VERSION 5.7 ;
  NOWIREEXTENSIONATPIN ON ;
  DIVIDERCHAR "/" ;
  BUSBITCHARS "[]" ;
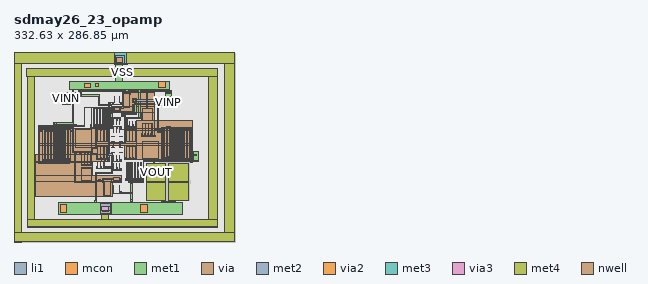
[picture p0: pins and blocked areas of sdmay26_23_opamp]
MACRO sdmay26_23_opamp
  CLASS BLOCK ;
  FOREIGN sdmay26_23_opamp ;
  ORIGIN -239.980 -7.060 ;
  SIZE 332.630 BY 286.850 ;
  PIN VINN
    ANTENNAGATEAREA 57.199997 ;
    PORT
      LAYER li1 ;
        RECT 468.290 235.120 477.470 235.240 ;
        RECT 313.390 213.970 324.780 232.110 ;
        RECT 468.120 231.680 477.470 235.120 ;
        RECT 468.290 227.210 477.470 231.680 ;
        RECT 386.770 166.690 388.770 166.860 ;
        RECT 389.060 166.690 391.060 166.860 ;
        RECT 386.770 158.990 388.770 159.160 ;
        RECT 389.060 158.990 391.060 159.160 ;
        RECT 399.120 150.270 401.120 150.440 ;
        RECT 401.410 150.270 403.410 150.440 ;
        RECT 399.120 142.570 401.120 142.740 ;
        RECT 401.410 142.570 403.410 142.740 ;
      LAYER mcon ;
        RECT 472.590 232.660 476.090 234.490 ;
        RECT 314.920 221.170 323.280 224.190 ;
        RECT 386.850 166.690 388.690 166.860 ;
        RECT 389.140 166.690 390.980 166.860 ;
        RECT 386.850 158.990 388.690 159.160 ;
        RECT 389.140 158.990 390.980 159.160 ;
        RECT 399.200 150.270 401.040 150.440 ;
        RECT 401.490 150.270 403.330 150.440 ;
        RECT 399.200 142.570 401.040 142.740 ;
        RECT 401.490 142.570 403.330 142.740 ;
      LAYER met1 ;
        RECT 468.290 235.120 477.470 235.240 ;
        RECT 313.260 214.170 324.650 232.310 ;
        RECT 336.240 229.550 342.060 233.160 ;
        RECT 468.120 231.680 477.470 235.120 ;
        RECT 367.100 229.550 369.750 229.670 ;
        RECT 335.990 226.930 369.750 229.550 ;
        RECT 468.290 227.210 477.470 231.680 ;
        RECT 336.240 226.680 342.060 226.930 ;
        RECT 367.100 214.120 369.750 226.930 ;
        RECT 366.830 212.790 387.880 214.120 ;
        RECT 366.830 212.610 387.910 212.790 ;
        RECT 367.100 212.560 369.750 212.610 ;
        RECT 387.070 202.290 387.910 212.610 ;
        RECT 387.040 201.620 387.910 202.290 ;
        RECT 387.040 201.300 387.870 201.620 ;
        RECT 385.220 195.590 388.570 201.300 ;
        RECT 385.220 184.180 386.030 195.590 ;
        RECT 385.170 184.120 386.030 184.180 ;
        RECT 385.170 179.770 385.980 184.120 ;
        RECT 382.850 178.880 385.990 179.770 ;
        RECT 382.890 157.330 383.970 178.880 ;
        RECT 386.790 166.660 388.750 166.890 ;
        RECT 389.080 166.660 391.040 166.890 ;
        RECT 386.790 159.150 388.750 159.190 ;
        RECT 389.080 159.150 391.040 159.190 ;
        RECT 386.790 158.960 391.040 159.150 ;
        RECT 382.900 156.790 383.970 157.330 ;
        RECT 387.480 158.860 388.810 158.960 ;
        RECT 387.480 156.940 387.880 158.860 ;
        RECT 387.470 156.790 387.880 156.940 ;
        RECT 399.450 156.790 400.660 157.410 ;
        RECT 382.900 156.780 388.780 156.790 ;
        RECT 397.140 156.780 400.660 156.790 ;
        RECT 382.900 156.770 400.660 156.780 ;
        RECT 382.900 156.350 400.670 156.770 ;
        RECT 382.900 156.340 397.730 156.350 ;
        RECT 382.900 156.330 388.780 156.340 ;
        RECT 399.450 156.330 400.670 156.350 ;
        RECT 382.900 156.320 384.820 156.330 ;
        RECT 399.540 153.430 400.750 154.610 ;
        RECT 399.770 153.390 400.380 153.430 ;
        RECT 399.780 152.270 400.380 153.390 ;
        RECT 399.770 151.500 400.380 152.270 ;
        RECT 399.770 150.470 400.370 151.500 ;
        RECT 399.140 150.460 401.100 150.470 ;
        RECT 401.430 150.460 403.390 150.470 ;
        RECT 399.140 150.250 403.390 150.460 ;
        RECT 399.140 150.240 401.100 150.250 ;
        RECT 401.430 150.240 403.390 150.250 ;
        RECT 399.140 142.540 401.100 142.770 ;
        RECT 401.430 142.540 403.390 142.770 ;
      LAYER via ;
        RECT 319.470 227.050 322.580 230.610 ;
        RECT 338.210 228.680 340.550 231.880 ;
        RECT 468.810 232.370 470.810 234.670 ;
        RECT 399.790 156.520 400.420 157.090 ;
        RECT 399.800 153.760 400.430 154.330 ;
      LAYER met2 ;
        RECT 337.620 233.800 471.730 235.290 ;
        RECT 337.680 233.160 340.990 233.800 ;
        RECT 317.820 232.020 324.530 232.060 ;
        RECT 336.240 232.020 342.060 233.160 ;
        RECT 317.820 228.720 342.060 232.020 ;
        RECT 468.120 231.680 471.730 233.800 ;
        RECT 317.820 225.600 324.530 228.720 ;
        RECT 336.240 226.680 342.060 228.720 ;
        RECT 399.450 155.940 400.660 157.410 ;
        RECT 399.700 154.910 400.230 155.940 ;
        RECT 399.550 154.900 400.900 154.910 ;
        RECT 399.540 154.360 400.900 154.900 ;
        RECT 399.540 153.430 400.860 154.360 ;
        RECT 399.550 153.400 400.860 153.430 ;
    END
  END VINN
  PIN VINP
    ANTENNAGATEAREA 57.199997 ;
    PORT
      LAYER li1 ;
        RECT 467.950 211.780 477.760 224.690 ;
        RECT 399.090 166.680 401.090 166.850 ;
        RECT 401.380 166.680 403.380 166.850 ;
        RECT 399.090 158.980 401.090 159.150 ;
        RECT 401.380 158.980 403.380 159.150 ;
        RECT 386.720 150.230 388.720 150.400 ;
        RECT 389.010 150.230 391.010 150.400 ;
        RECT 386.720 142.530 388.720 142.700 ;
        RECT 389.010 142.530 391.010 142.700 ;
      LAYER mcon ;
        RECT 468.710 220.920 476.500 223.600 ;
        RECT 399.170 166.680 401.010 166.850 ;
        RECT 401.460 166.680 403.300 166.850 ;
        RECT 399.170 158.980 401.010 159.150 ;
        RECT 401.460 158.980 403.300 159.150 ;
        RECT 386.800 150.230 388.640 150.400 ;
        RECT 389.090 150.230 390.930 150.400 ;
        RECT 386.800 142.530 388.640 142.700 ;
        RECT 389.090 142.530 390.930 142.700 ;
      LAYER met1 ;
        RECT 418.610 217.550 425.230 223.250 ;
        RECT 467.950 217.980 477.760 224.690 ;
        RECT 421.850 201.360 424.480 217.550 ;
        RECT 463.100 212.870 477.760 217.980 ;
        RECT 467.950 211.780 477.760 212.870 ;
        RECT 406.840 201.030 424.480 201.360 ;
        RECT 402.760 199.330 424.480 201.030 ;
        RECT 402.760 199.030 423.590 199.330 ;
        RECT 402.760 197.940 408.040 199.030 ;
        RECT 402.760 196.040 408.070 197.940 ;
        RECT 399.110 166.650 401.070 166.880 ;
        RECT 401.400 166.650 403.360 166.880 ;
        RECT 399.110 159.010 403.360 159.180 ;
        RECT 399.110 158.950 401.070 159.010 ;
        RECT 401.400 158.950 403.360 159.010 ;
        RECT 402.140 157.000 402.470 158.950 ;
        RECT 406.970 157.030 408.070 196.040 ;
        RECT 406.970 157.000 408.100 157.030 ;
        RECT 402.140 156.230 408.100 157.000 ;
        RECT 389.590 155.730 390.500 155.740 ;
        RECT 402.140 155.730 402.540 156.230 ;
        RECT 389.580 155.210 402.540 155.730 ;
        RECT 389.580 155.200 391.060 155.210 ;
        RECT 389.580 155.160 390.490 155.200 ;
        RECT 389.590 153.040 390.490 155.160 ;
        RECT 389.590 152.420 390.500 153.040 ;
        RECT 389.600 150.600 390.480 152.420 ;
        RECT 388.590 150.430 390.480 150.600 ;
        RECT 386.740 150.230 390.990 150.430 ;
        RECT 386.740 150.200 388.700 150.230 ;
        RECT 389.030 150.200 390.990 150.230 ;
        RECT 386.740 142.500 388.700 142.730 ;
        RECT 389.030 142.500 390.990 142.730 ;
      LAYER via ;
        RECT 420.280 218.840 423.400 222.370 ;
        RECT 464.600 213.710 469.040 216.560 ;
      LAYER met2 ;
        RECT 418.610 221.570 425.230 223.250 ;
        RECT 418.610 221.470 455.680 221.570 ;
        RECT 460.020 221.470 462.590 221.520 ;
        RECT 418.610 219.580 462.590 221.470 ;
        RECT 418.610 219.560 455.680 219.580 ;
        RECT 418.610 217.550 425.230 219.560 ;
        RECT 460.020 216.140 462.590 219.580 ;
        RECT 463.100 216.140 470.220 217.980 ;
        RECT 460.020 214.130 470.220 216.140 ;
        RECT 460.020 214.040 462.590 214.130 ;
        RECT 463.100 212.870 470.220 214.130 ;
    END
  END VINP
  PIN VSS
    USE GROUND ;
    ANTENNADIFFAREA 475.595184 ;
    PORT
      LAYER li1 ;
        RECT 391.225 217.115 391.395 227.155 ;
        RECT 399.805 217.115 399.975 227.155 ;
        RECT 357.360 182.170 357.530 207.920 ;
        RECT 361.940 182.170 362.110 207.920 ;
        RECT 366.520 182.170 366.690 207.920 ;
        RECT 371.100 182.170 371.270 207.920 ;
        RECT 375.680 182.170 375.850 207.920 ;
        RECT 380.260 182.170 380.430 207.920 ;
        RECT 390.640 184.290 390.810 191.470 ;
        RECT 395.220 184.290 395.390 191.470 ;
        RECT 399.800 184.290 399.970 191.470 ;
        RECT 414.420 182.200 414.590 189.380 ;
        RECT 419.000 182.200 419.170 189.380 ;
        RECT 423.580 182.200 423.750 189.380 ;
        RECT 390.640 172.450 390.810 179.630 ;
        RECT 395.220 172.450 395.390 179.630 ;
        RECT 399.800 172.450 399.970 179.630 ;
        RECT 390.640 129.780 390.810 136.960 ;
        RECT 395.220 129.780 395.390 136.960 ;
        RECT 399.800 129.780 399.970 136.960 ;
        RECT 366.540 120.020 366.710 127.200 ;
        RECT 371.120 120.020 371.290 127.200 ;
        RECT 375.700 120.020 375.870 127.200 ;
        RECT 390.640 117.940 390.810 125.120 ;
        RECT 395.220 117.940 395.390 125.120 ;
        RECT 399.800 117.940 399.970 125.120 ;
        RECT 409.730 101.510 409.900 127.260 ;
        RECT 414.310 101.510 414.480 127.260 ;
        RECT 418.890 101.510 419.060 127.260 ;
        RECT 423.470 101.510 423.640 127.260 ;
        RECT 428.050 101.510 428.220 127.260 ;
        RECT 432.630 101.510 432.800 127.260 ;
        RECT 390.645 82.245 390.815 92.285 ;
        RECT 399.225 82.245 399.395 92.285 ;
        RECT 306.930 66.710 379.870 66.860 ;
        RECT 397.480 66.730 494.780 66.860 ;
        RECT 391.610 66.710 494.780 66.730 ;
        RECT 306.930 48.590 494.780 66.710 ;
        RECT 376.920 48.580 393.320 48.590 ;
      LAYER mcon ;
        RECT 391.225 217.195 391.395 227.075 ;
        RECT 399.805 217.195 399.975 227.075 ;
        RECT 357.360 182.250 357.530 207.840 ;
        RECT 361.940 182.250 362.110 207.840 ;
        RECT 366.520 182.250 366.690 207.840 ;
        RECT 371.100 182.250 371.270 207.840 ;
        RECT 375.680 182.250 375.850 207.840 ;
        RECT 380.260 182.250 380.430 207.840 ;
        RECT 390.640 184.370 390.810 191.390 ;
        RECT 395.220 184.370 395.390 191.390 ;
        RECT 399.800 184.370 399.970 191.390 ;
        RECT 414.420 182.280 414.590 189.300 ;
        RECT 419.000 182.280 419.170 189.300 ;
        RECT 423.580 182.280 423.750 189.300 ;
        RECT 390.640 172.530 390.810 179.550 ;
        RECT 395.220 172.530 395.390 179.550 ;
        RECT 399.800 172.530 399.970 179.550 ;
        RECT 390.640 129.860 390.810 136.880 ;
        RECT 395.220 129.860 395.390 136.880 ;
        RECT 399.800 129.860 399.970 136.880 ;
        RECT 366.540 120.100 366.710 127.120 ;
        RECT 371.120 120.100 371.290 127.120 ;
        RECT 375.700 120.100 375.870 127.120 ;
        RECT 390.640 118.020 390.810 125.040 ;
        RECT 395.220 118.020 395.390 125.040 ;
        RECT 399.800 118.020 399.970 125.040 ;
        RECT 409.730 101.590 409.900 127.180 ;
        RECT 414.310 101.590 414.480 127.180 ;
        RECT 418.890 101.590 419.060 127.180 ;
        RECT 423.470 101.590 423.640 127.180 ;
        RECT 428.050 101.590 428.220 127.180 ;
        RECT 432.630 101.590 432.800 127.180 ;
        RECT 390.645 82.325 390.815 92.205 ;
        RECT 399.225 82.325 399.395 92.205 ;
        RECT 309.490 51.230 319.680 63.190 ;
        RECT 430.830 51.190 441.020 63.150 ;
      LAYER met1 ;
        RECT 391.195 217.980 391.425 227.135 ;
        RECT 384.850 217.940 391.425 217.980 ;
        RECT 383.270 217.600 391.425 217.940 ;
        RECT 382.830 217.150 391.425 217.600 ;
        RECT 382.830 215.490 385.400 217.150 ;
        RECT 389.020 214.360 389.560 217.150 ;
        RECT 391.195 217.135 391.425 217.150 ;
        RECT 399.775 218.020 400.005 227.135 ;
        RECT 399.775 217.990 401.330 218.020 ;
        RECT 399.775 217.560 401.560 217.990 ;
        RECT 399.775 217.135 400.005 217.560 ;
        RECT 400.950 214.360 401.560 217.560 ;
        RECT 389.020 214.030 401.560 214.360 ;
        RECT 390.030 214.020 401.560 214.030 ;
        RECT 355.200 183.930 356.210 184.020 ;
        RECT 355.200 183.890 356.700 183.930 ;
        RECT 357.330 183.890 357.560 207.900 ;
        RECT 355.200 182.970 357.560 183.890 ;
        RECT 355.200 182.850 356.210 182.970 ;
        RECT 356.390 182.930 357.560 182.970 ;
        RECT 355.930 182.820 356.210 182.850 ;
        RECT 355.930 182.790 356.070 182.820 ;
        RECT 357.330 182.190 357.560 182.930 ;
        RECT 361.910 183.680 362.140 207.900 ;
        RECT 362.600 183.680 363.220 183.830 ;
        RECT 361.910 183.060 363.220 183.680 ;
        RECT 366.490 183.790 366.720 207.900 ;
        RECT 367.260 183.790 367.880 183.930 ;
        RECT 366.490 183.160 367.880 183.790 ;
        RECT 371.070 183.840 371.300 207.900 ;
        RECT 371.750 183.840 372.370 183.950 ;
        RECT 371.070 183.810 372.370 183.840 ;
        RECT 375.650 183.890 375.880 207.900 ;
        RECT 380.230 185.340 380.460 207.900 ;
        RECT 395.850 194.450 397.110 194.460 ;
        RECT 387.620 193.300 401.330 194.450 ;
        RECT 387.620 191.340 389.000 193.300 ;
        RECT 395.850 193.280 397.110 193.300 ;
        RECT 390.610 191.340 390.840 191.450 ;
        RECT 387.620 191.220 390.840 191.340 ;
        RECT 387.600 189.980 390.840 191.220 ;
        RECT 382.370 185.340 384.110 186.710 ;
        RECT 380.230 184.500 384.110 185.340 ;
        RECT 380.230 184.480 381.970 184.500 ;
        RECT 382.370 184.480 384.110 184.500 ;
        RECT 376.410 183.930 377.030 184.060 ;
        RECT 376.170 183.890 377.030 183.930 ;
        RECT 371.070 183.220 372.380 183.810 ;
        RECT 375.650 183.280 377.030 183.890 ;
        RECT 375.650 183.270 376.390 183.280 ;
        RECT 366.490 183.150 367.780 183.160 ;
        RECT 361.910 183.050 363.200 183.060 ;
        RECT 361.910 182.190 362.140 183.050 ;
        RECT 366.490 182.190 366.720 183.150 ;
        RECT 371.070 182.190 371.300 183.220 ;
        RECT 371.750 183.180 372.370 183.220 ;
        RECT 375.650 182.190 375.880 183.270 ;
        RECT 380.230 182.190 380.460 184.480 ;
        RECT 387.600 181.440 389.000 189.980 ;
        RECT 390.610 184.310 390.840 189.980 ;
        RECT 395.190 190.890 395.420 191.450 ;
        RECT 399.770 191.380 400.000 191.450 ;
        RECT 400.330 191.380 401.330 193.300 ;
        RECT 395.870 190.890 396.840 191.080 ;
        RECT 395.190 190.140 396.840 190.890 ;
        RECT 399.770 190.730 401.330 191.380 ;
        RECT 395.190 190.130 396.590 190.140 ;
        RECT 395.190 184.310 395.420 190.130 ;
        RECT 399.770 184.310 400.000 190.730 ;
        RECT 414.390 183.510 414.620 189.360 ;
        RECT 412.980 183.020 414.620 183.510 ;
        RECT 387.580 179.390 389.010 181.440 ;
        RECT 412.980 180.520 413.410 183.020 ;
        RECT 414.390 182.220 414.620 183.020 ;
        RECT 418.970 183.530 419.200 189.360 ;
        RECT 419.760 183.530 420.490 183.830 ;
        RECT 418.970 183.000 420.490 183.530 ;
        RECT 418.970 182.990 420.140 183.000 ;
        RECT 418.970 182.220 419.200 182.990 ;
        RECT 423.550 182.820 423.780 189.360 ;
        RECT 424.910 182.820 425.500 182.850 ;
        RECT 423.550 182.490 425.500 182.820 ;
        RECT 423.550 182.220 423.780 182.490 ;
        RECT 419.550 180.850 420.650 181.100 ;
        RECT 424.910 180.850 425.500 182.490 ;
        RECT 413.720 180.680 415.430 180.710 ;
        RECT 419.550 180.680 425.500 180.850 ;
        RECT 413.720 180.520 425.500 180.680 ;
        RECT 412.980 180.280 425.500 180.520 ;
        RECT 412.980 180.120 420.840 180.280 ;
        RECT 424.910 180.260 425.500 180.280 ;
        RECT 412.980 179.960 415.430 180.120 ;
        RECT 413.110 179.920 415.430 179.960 ;
        RECT 390.610 179.390 390.840 179.610 ;
        RECT 387.580 178.620 390.840 179.390 ;
        RECT 388.700 178.610 390.840 178.620 ;
        RECT 390.610 172.470 390.840 178.610 ;
        RECT 395.190 179.170 395.420 179.610 ;
        RECT 395.190 179.150 396.380 179.170 ;
        RECT 395.190 178.700 396.610 179.150 ;
        RECT 395.190 172.470 395.420 178.700 ;
        RECT 395.800 178.410 396.610 178.700 ;
        RECT 399.770 179.020 400.000 179.610 ;
        RECT 413.720 179.280 415.430 179.920 ;
        RECT 401.070 179.020 402.120 179.150 ;
        RECT 399.770 178.370 402.120 179.020 ;
        RECT 399.770 172.470 400.000 178.370 ;
        RECT 401.070 178.340 402.120 178.370 ;
        RECT 387.910 130.850 389.570 130.860 ;
        RECT 387.670 130.650 389.570 130.850 ;
        RECT 387.140 130.550 389.570 130.650 ;
        RECT 390.610 130.550 390.840 136.940 ;
        RECT 387.140 130.050 390.840 130.550 ;
        RECT 387.140 129.440 389.570 130.050 ;
        RECT 390.610 129.800 390.840 130.050 ;
        RECT 395.190 131.270 395.420 136.940 ;
        RECT 395.850 131.270 396.670 131.650 ;
        RECT 395.190 130.900 396.670 131.270 ;
        RECT 395.190 129.800 395.420 130.900 ;
        RECT 395.850 130.880 396.670 130.900 ;
        RECT 399.770 131.400 400.000 136.940 ;
        RECT 400.950 131.400 401.810 131.420 ;
        RECT 399.770 130.800 401.810 131.400 ;
        RECT 399.770 129.800 400.000 130.800 ;
        RECT 400.950 130.530 401.810 130.800 ;
        RECT 366.510 120.710 366.740 127.180 ;
        RECT 364.820 120.270 366.740 120.710 ;
        RECT 364.820 118.640 365.500 120.270 ;
        RECT 366.510 120.040 366.740 120.270 ;
        RECT 371.090 121.110 371.320 127.180 ;
        RECT 371.510 121.110 372.210 121.370 ;
        RECT 371.090 120.600 372.210 121.110 ;
        RECT 371.090 120.040 371.320 120.600 ;
        RECT 375.670 120.560 375.900 127.180 ;
        RECT 387.140 120.780 388.690 129.440 ;
        RECT 376.930 120.560 388.760 120.780 ;
        RECT 375.670 120.180 388.760 120.560 ;
        RECT 375.670 120.040 375.900 120.180 ;
        RECT 376.840 118.940 388.760 120.180 ;
        RECT 390.610 118.940 390.840 125.100 ;
        RECT 395.190 119.370 395.420 125.100 ;
        RECT 395.820 119.370 396.770 119.810 ;
        RECT 371.450 118.640 372.260 118.650 ;
        RECT 376.840 118.640 390.900 118.940 ;
        RECT 395.180 118.680 396.770 119.370 ;
        RECT 395.180 118.670 396.530 118.680 ;
        RECT 364.820 118.360 390.900 118.640 ;
        RECT 364.820 118.240 377.400 118.360 ;
        RECT 371.450 117.900 372.260 118.240 ;
        RECT 387.140 118.040 390.900 118.360 ;
        RECT 387.140 115.970 388.690 118.040 ;
        RECT 390.610 117.960 390.840 118.040 ;
        RECT 395.190 117.960 395.420 118.670 ;
        RECT 399.770 118.640 400.000 125.100 ;
        RECT 401.060 118.640 401.940 118.650 ;
        RECT 399.750 118.180 401.940 118.640 ;
        RECT 399.770 117.960 400.000 118.180 ;
        RECT 401.060 116.510 401.940 118.180 ;
        RECT 401.060 115.970 401.930 116.510 ;
        RECT 387.140 115.020 401.930 115.970 ;
        RECT 387.140 112.070 388.690 115.020 ;
        RECT 363.020 111.950 388.690 112.070 ;
        RECT 362.310 109.930 388.690 111.950 ;
        RECT 362.310 71.610 364.460 109.930 ;
        RECT 387.140 109.890 388.690 109.930 ;
        RECT 409.700 102.300 409.930 127.240 ;
        RECT 408.750 102.290 409.930 102.300 ;
        RECT 408.690 101.900 409.930 102.290 ;
        RECT 408.690 100.300 409.210 101.900 ;
        RECT 409.700 101.530 409.930 101.900 ;
        RECT 414.280 102.610 414.510 127.240 ;
        RECT 414.760 102.610 415.360 102.630 ;
        RECT 414.280 102.040 415.360 102.610 ;
        RECT 418.860 102.510 419.090 127.240 ;
        RECT 419.460 102.510 420.350 102.640 ;
        RECT 418.860 102.050 420.350 102.510 ;
        RECT 423.440 102.580 423.670 127.240 ;
        RECT 424.080 102.580 424.970 102.700 ;
        RECT 423.440 102.120 424.970 102.580 ;
        RECT 414.280 102.000 415.260 102.040 ;
        RECT 414.280 101.530 414.510 102.000 ;
        RECT 418.860 101.530 419.090 102.050 ;
        RECT 423.440 101.530 423.670 102.120 ;
        RECT 424.080 102.110 424.970 102.120 ;
        RECT 428.020 102.570 428.250 127.240 ;
        RECT 428.660 102.570 429.550 102.690 ;
        RECT 428.020 102.110 429.550 102.570 ;
        RECT 428.020 101.530 428.250 102.110 ;
        RECT 428.660 102.100 429.550 102.110 ;
        RECT 432.600 102.320 432.830 127.240 ;
        RECT 433.580 102.320 433.950 102.350 ;
        RECT 432.600 101.930 433.950 102.320 ;
        RECT 432.600 101.530 432.830 101.930 ;
        RECT 414.710 100.300 415.600 100.360 ;
        RECT 419.300 100.300 420.190 100.340 ;
        RECT 424.180 100.300 425.070 100.410 ;
        RECT 428.600 100.300 429.490 100.380 ;
        RECT 433.580 100.300 433.950 101.930 ;
        RECT 408.690 99.890 433.950 100.300 ;
        RECT 408.710 99.850 433.950 99.890 ;
        RECT 408.710 99.810 433.900 99.850 ;
        RECT 414.710 99.770 415.600 99.810 ;
        RECT 416.430 99.060 418.140 99.810 ;
        RECT 419.300 99.750 420.190 99.810 ;
        RECT 428.600 99.790 429.490 99.810 ;
        RECT 416.430 97.620 418.360 99.060 ;
        RECT 416.450 95.120 418.360 97.620 ;
        RECT 388.360 83.450 388.990 83.530 ;
        RECT 390.615 83.450 390.845 92.265 ;
        RECT 388.360 82.900 390.845 83.450 ;
        RECT 388.360 80.320 388.990 82.900 ;
        RECT 390.615 82.265 390.845 82.900 ;
        RECT 399.195 83.760 399.425 92.265 ;
        RECT 401.070 83.760 401.670 83.780 ;
        RECT 399.195 83.130 401.670 83.760 ;
        RECT 399.195 82.265 399.425 83.130 ;
        RECT 401.070 81.850 401.670 83.130 ;
        RECT 416.550 81.850 418.360 95.120 ;
        RECT 401.070 80.750 418.360 81.850 ;
        RECT 401.070 80.320 401.670 80.750 ;
        RECT 388.280 80.010 401.670 80.320 ;
        RECT 416.550 71.610 418.360 80.750 ;
        RECT 362.310 70.080 364.760 71.610 ;
        RECT 416.550 71.420 418.660 71.610 ;
        RECT 362.170 66.860 364.760 70.080 ;
        RECT 416.460 68.310 418.660 71.420 ;
        RECT 416.550 68.000 418.660 68.310 ;
        RECT 416.600 67.770 418.660 68.000 ;
        RECT 416.550 67.300 418.660 67.770 ;
        RECT 416.600 66.860 418.660 67.300 ;
        RECT 306.930 66.710 379.870 66.860 ;
        RECT 397.480 66.730 494.780 66.860 ;
        RECT 391.610 66.710 494.780 66.730 ;
        RECT 306.930 48.590 494.780 66.710 ;
        RECT 376.920 48.580 393.320 48.590 ;
      LAYER via ;
        RECT 383.480 216.040 385.040 217.090 ;
        RECT 355.340 183.080 355.890 183.810 ;
        RECT 362.730 183.160 362.990 183.580 ;
        RECT 367.390 183.310 367.650 183.730 ;
        RECT 396.200 193.420 396.840 194.030 ;
        RECT 382.700 184.730 383.640 186.000 ;
        RECT 371.850 183.370 372.110 183.790 ;
        RECT 376.540 183.380 376.800 183.800 ;
        RECT 396.090 190.370 396.560 190.840 ;
        RECT 387.870 180.250 388.680 181.080 ;
        RECT 419.910 183.160 420.410 183.620 ;
        RECT 414.050 179.670 414.990 180.420 ;
        RECT 419.930 180.350 420.430 180.810 ;
        RECT 395.970 178.580 396.450 179.060 ;
        RECT 401.310 178.530 401.960 178.890 ;
        RECT 388.290 129.790 389.230 130.450 ;
        RECT 396.020 131.010 396.610 131.430 ;
        RECT 401.100 130.690 401.670 131.190 ;
        RECT 371.660 120.760 371.990 121.190 ;
        RECT 396.060 118.920 396.470 119.480 ;
        RECT 371.620 118.040 372.050 118.410 ;
        RECT 395.990 115.190 396.810 115.640 ;
        RECT 414.880 102.160 415.220 102.530 ;
        RECT 419.780 102.170 420.110 102.440 ;
        RECT 424.310 102.310 424.640 102.580 ;
        RECT 428.890 102.250 429.220 102.520 ;
        RECT 414.970 99.960 415.300 100.230 ;
        RECT 419.640 99.900 419.970 100.170 ;
        RECT 424.510 99.940 424.840 100.210 ;
        RECT 428.870 99.940 429.200 100.210 ;
        RECT 372.390 53.710 382.510 62.560 ;
        RECT 372.990 53.640 382.160 53.710 ;
      LAYER met2 ;
        RECT 382.830 215.490 385.400 217.600 ;
        RECT 395.850 193.280 397.110 194.460 ;
        RECT 396.120 191.080 396.690 193.280 ;
        RECT 395.870 190.140 396.840 191.080 ;
        RECT 382.370 184.480 384.110 186.710 ;
        RECT 355.200 182.820 356.210 184.020 ;
        RECT 362.600 183.060 363.220 183.830 ;
        RECT 367.260 183.160 367.880 183.930 ;
        RECT 371.750 183.180 372.370 183.950 ;
        RECT 376.410 183.610 377.030 184.060 ;
        RECT 376.390 183.290 377.030 183.610 ;
        RECT 355.320 180.910 356.050 182.820 ;
        RECT 355.310 180.660 356.050 180.910 ;
        RECT 355.310 180.640 356.390 180.660 ;
        RECT 362.720 180.640 363.050 183.060 ;
        RECT 367.320 180.640 367.650 183.160 ;
        RECT 371.810 180.640 372.140 183.180 ;
        RECT 376.390 180.640 376.720 183.290 ;
        RECT 419.760 183.000 420.490 183.830 ;
        RECT 395.920 181.440 396.600 181.450 ;
        RECT 397.180 181.440 402.050 181.460 ;
        RECT 387.590 180.980 402.050 181.440 ;
        RECT 419.970 181.110 420.200 183.000 ;
        RECT 419.590 181.100 420.840 181.110 ;
        RECT 387.590 180.960 397.700 180.980 ;
        RECT 387.590 180.940 396.600 180.960 ;
        RECT 378.470 180.640 380.040 180.930 ;
        RECT 355.310 179.860 380.040 180.640 ;
        RECT 387.590 180.900 396.580 180.940 ;
        RECT 387.590 180.020 388.970 180.900 ;
        RECT 395.920 180.690 396.580 180.900 ;
        RECT 355.310 179.840 361.360 179.860 ;
        RECT 356.230 179.820 361.360 179.840 ;
        RECT 378.470 179.470 380.040 179.860 ;
        RECT 395.920 179.150 396.600 180.690 ;
        RECT 401.220 179.190 402.040 180.980 ;
        RECT 407.620 180.550 408.510 180.580 ;
        RECT 413.720 180.550 415.430 180.710 ;
        RECT 407.620 179.750 415.430 180.550 ;
        RECT 419.550 180.410 420.840 181.100 ;
        RECT 419.590 180.180 420.840 180.410 ;
        RECT 401.150 179.150 402.090 179.190 ;
        RECT 395.800 178.410 396.610 179.150 ;
        RECT 401.070 178.340 402.120 179.150 ;
        RECT 401.150 177.480 402.090 178.340 ;
        RECT 407.620 178.290 408.510 179.750 ;
        RECT 413.720 179.280 415.430 179.750 ;
        RECT 407.560 177.770 408.510 178.290 ;
        RECT 407.560 177.480 408.500 177.770 ;
        RECT 401.150 176.470 408.550 177.480 ;
        RECT 407.560 176.370 408.500 176.470 ;
        RECT 382.260 141.390 384.300 143.590 ;
        RECT 382.340 140.010 383.910 141.390 ;
        RECT 382.340 138.110 389.170 140.010 ;
        RECT 387.480 136.670 389.170 138.110 ;
        RECT 387.580 134.710 389.170 136.670 ;
        RECT 387.660 130.860 389.170 134.710 ;
        RECT 395.850 130.880 396.670 131.650 ;
        RECT 387.660 129.550 389.570 130.860 ;
        RECT 387.670 129.530 389.570 129.550 ;
        RECT 387.680 129.450 389.570 129.530 ;
        RECT 387.910 129.440 389.570 129.450 ;
        RECT 388.900 128.450 389.530 129.440 ;
        RECT 388.880 128.440 390.370 128.450 ;
        RECT 396.050 128.440 396.430 130.880 ;
        RECT 400.950 130.530 401.810 131.420 ;
        RECT 401.100 128.440 401.550 130.530 ;
        RECT 388.880 127.900 401.570 128.440 ;
        RECT 390.080 127.880 401.570 127.900 ;
        RECT 401.100 127.870 401.550 127.880 ;
        RECT 371.510 120.600 372.210 121.370 ;
        RECT 371.660 118.650 372.000 120.600 ;
        RECT 395.820 118.680 396.770 119.810 ;
        RECT 371.450 117.900 372.260 118.650 ;
        RECT 395.990 116.010 396.660 118.680 ;
        RECT 395.670 115.040 397.110 116.010 ;
        RECT 414.760 102.040 415.360 102.630 ;
        RECT 419.460 102.050 420.350 102.640 ;
        RECT 424.080 102.110 424.970 102.700 ;
        RECT 414.930 100.360 415.220 102.040 ;
        RECT 414.710 99.770 415.600 100.360 ;
        RECT 419.710 100.340 420.010 102.050 ;
        RECT 424.480 100.410 424.780 102.110 ;
        RECT 428.660 102.100 429.550 102.690 ;
        RECT 419.300 99.750 420.190 100.340 ;
        RECT 424.180 99.820 425.070 100.410 ;
        RECT 428.900 100.380 429.200 102.100 ;
        RECT 428.600 99.790 429.490 100.380 ;
        RECT 370.640 60.350 385.850 64.490 ;
        RECT 370.300 53.970 385.850 60.350 ;
        RECT 370.640 50.730 385.850 53.970 ;
      LAYER via2 ;
        RECT 383.480 216.040 385.040 217.090 ;
        RECT 382.700 184.730 383.640 186.000 ;
        RECT 378.820 179.820 379.590 180.580 ;
        RECT 387.870 180.250 388.680 181.080 ;
        RECT 382.710 141.820 383.820 142.950 ;
        RECT 372.390 53.710 382.510 62.560 ;
        RECT 372.990 53.640 382.160 53.710 ;
      LAYER met3 ;
        RECT 382.830 216.260 385.400 217.600 ;
        RECT 382.810 215.490 385.400 216.260 ;
        RECT 382.810 186.710 383.920 215.490 ;
        RECT 382.370 184.480 384.110 186.710 ;
        RECT 383.110 181.400 383.950 184.480 ;
        RECT 387.210 181.400 389.050 181.460 ;
        RECT 382.880 181.130 389.050 181.400 ;
        RECT 378.470 180.520 380.040 180.930 ;
        RECT 382.790 180.520 389.050 181.130 ;
        RECT 378.470 180.000 389.050 180.520 ;
        RECT 378.470 179.540 384.380 180.000 ;
        RECT 385.830 179.970 389.050 180.000 ;
        RECT 387.210 179.960 389.050 179.970 ;
        RECT 378.470 179.470 380.040 179.540 ;
        RECT 382.790 176.180 384.350 179.540 ;
        RECT 382.760 143.590 384.350 176.180 ;
        RECT 382.260 141.840 384.350 143.590 ;
        RECT 382.260 141.390 384.300 141.840 ;
        RECT 370.570 60.350 386.530 64.980 ;
        RECT 370.300 53.970 386.530 60.350 ;
        RECT 370.570 50.520 386.530 53.970 ;
        RECT 372.690 48.160 381.490 50.520 ;
      LAYER via3 ;
        RECT 372.390 53.710 382.510 62.560 ;
      LAYER met4 ;
        RECT 259.490 268.430 547.440 268.440 ;
        RECT 259.490 256.510 547.820 268.430 ;
        RECT 259.710 40.280 270.210 256.510 ;
        RECT 370.570 50.520 386.530 64.980 ;
        RECT 371.980 40.280 382.800 50.520 ;
        RECT 533.890 40.280 547.820 256.510 ;
        RECT 259.710 30.760 547.820 40.280 ;
        RECT 259.710 30.190 547.910 30.760 ;
        RECT 259.910 29.380 547.910 30.190 ;
        RECT 536.830 29.250 547.910 29.380 ;
    END
  END VSS
  PIN VOUT
    ANTENNADIFFAREA 306.535797 ;
    PORT
      LAYER li1 ;
        RECT 359.650 182.170 359.820 207.920 ;
        RECT 364.230 182.170 364.400 207.920 ;
        RECT 368.810 182.170 368.980 207.920 ;
        RECT 373.390 182.170 373.560 207.920 ;
        RECT 377.970 182.170 378.140 207.920 ;
        RECT 285.680 131.585 285.850 176.065 ;
        RECT 290.260 131.585 290.430 176.065 ;
        RECT 294.840 131.585 295.010 176.065 ;
        RECT 299.420 131.585 299.590 176.065 ;
        RECT 304.000 131.585 304.170 176.065 ;
        RECT 308.580 131.585 308.750 176.065 ;
        RECT 313.160 131.585 313.330 176.065 ;
        RECT 317.740 131.585 317.910 176.065 ;
        RECT 322.320 131.585 322.490 176.065 ;
        RECT 467.660 133.365 467.830 177.845 ;
        RECT 472.240 133.365 472.410 177.845 ;
        RECT 476.820 133.365 476.990 177.845 ;
        RECT 481.400 133.365 481.570 177.845 ;
        RECT 485.980 133.365 486.150 177.845 ;
        RECT 490.560 133.365 490.730 177.845 ;
        RECT 495.140 133.365 495.310 177.845 ;
        RECT 499.720 133.365 499.890 177.845 ;
        RECT 504.300 133.365 504.470 177.845 ;
        RECT 511.390 130.180 518.810 143.420 ;
        RECT 510.530 129.870 518.810 130.180 ;
        RECT 508.520 129.620 518.810 129.870 ;
        RECT 508.360 128.470 518.810 129.620 ;
        RECT 508.360 128.150 516.690 128.470 ;
        RECT 511.500 128.100 516.690 128.150 ;
        RECT 412.020 101.510 412.190 127.260 ;
        RECT 416.600 101.510 416.770 127.260 ;
        RECT 421.180 101.510 421.350 127.260 ;
        RECT 425.760 101.510 425.930 127.260 ;
        RECT 430.340 101.510 430.510 127.260 ;
      LAYER mcon ;
        RECT 359.650 182.250 359.820 207.840 ;
        RECT 364.230 182.250 364.400 207.840 ;
        RECT 368.810 182.250 368.980 207.840 ;
        RECT 373.390 182.250 373.560 207.840 ;
        RECT 377.970 182.250 378.140 207.840 ;
        RECT 285.680 131.665 285.850 175.985 ;
        RECT 290.260 131.665 290.430 175.985 ;
        RECT 294.840 131.665 295.010 175.985 ;
        RECT 299.420 131.665 299.590 175.985 ;
        RECT 304.000 131.665 304.170 175.985 ;
        RECT 308.580 131.665 308.750 175.985 ;
        RECT 313.160 131.665 313.330 175.985 ;
        RECT 317.740 131.665 317.910 175.985 ;
        RECT 322.320 131.665 322.490 175.985 ;
        RECT 467.660 133.445 467.830 177.765 ;
        RECT 472.240 133.445 472.410 177.765 ;
        RECT 476.820 133.445 476.990 177.765 ;
        RECT 481.400 133.445 481.570 177.765 ;
        RECT 485.980 133.445 486.150 177.765 ;
        RECT 490.560 133.445 490.730 177.765 ;
        RECT 495.140 133.445 495.310 177.765 ;
        RECT 499.720 133.445 499.890 177.765 ;
        RECT 504.300 133.445 504.470 177.765 ;
        RECT 512.300 137.560 515.790 139.290 ;
        RECT 412.020 101.590 412.190 127.180 ;
        RECT 416.600 101.590 416.770 127.180 ;
        RECT 421.180 101.590 421.350 127.180 ;
        RECT 425.760 101.590 425.930 127.180 ;
        RECT 430.340 101.590 430.510 127.180 ;
      LAYER met1 ;
        RECT 377.070 210.170 379.520 210.450 ;
        RECT 377.070 210.160 385.060 210.170 ;
        RECT 360.570 210.150 360.870 210.160 ;
        RECT 363.560 210.150 366.780 210.160 ;
        RECT 369.610 210.150 385.060 210.160 ;
        RECT 345.860 210.030 346.840 210.080 ;
        RECT 360.570 210.030 385.060 210.150 ;
        RECT 345.860 209.550 385.060 210.030 ;
        RECT 345.860 209.520 379.570 209.550 ;
        RECT 345.860 209.400 379.520 209.520 ;
        RECT 345.860 204.350 346.840 209.400 ;
        RECT 360.600 209.230 364.940 209.400 ;
        RECT 365.750 209.390 370.510 209.400 ;
        RECT 377.070 209.350 379.520 209.400 ;
        RECT 359.620 207.430 359.850 207.900 ;
        RECT 360.320 207.430 361.240 207.600 ;
        RECT 359.580 206.580 361.240 207.430 ;
        RECT 331.950 183.200 334.990 184.610 ;
        RECT 345.790 183.200 346.840 204.350 ;
        RECT 331.950 181.270 346.840 183.200 ;
        RECT 359.620 182.190 359.850 206.580 ;
        RECT 360.320 206.450 361.240 206.580 ;
        RECT 364.200 207.470 364.430 207.900 ;
        RECT 364.990 207.470 365.910 207.650 ;
        RECT 364.200 206.620 365.910 207.470 ;
        RECT 364.200 182.190 364.430 206.620 ;
        RECT 364.990 206.500 365.910 206.620 ;
        RECT 368.780 207.310 369.010 207.900 ;
        RECT 369.380 207.310 370.300 207.560 ;
        RECT 368.780 206.460 370.300 207.310 ;
        RECT 368.780 182.190 369.010 206.460 ;
        RECT 369.380 206.410 370.300 206.460 ;
        RECT 373.360 207.350 373.590 207.900 ;
        RECT 373.970 207.350 374.890 207.540 ;
        RECT 373.360 206.500 374.890 207.350 ;
        RECT 373.360 182.190 373.590 206.500 ;
        RECT 373.970 206.390 374.890 206.500 ;
        RECT 377.940 207.430 378.170 207.900 ;
        RECT 377.940 207.420 379.260 207.430 ;
        RECT 377.940 206.580 379.510 207.420 ;
        RECT 377.940 182.190 378.170 206.580 ;
        RECT 378.590 206.270 379.510 206.580 ;
        RECT 384.260 204.970 384.970 209.550 ;
        RECT 383.970 202.310 386.070 204.970 ;
        RECT 331.950 181.240 346.420 181.270 ;
        RECT 331.950 181.170 334.990 181.240 ;
        RECT 285.650 133.190 285.880 176.045 ;
        RECT 286.310 133.190 287.300 133.600 ;
        RECT 285.650 132.380 287.300 133.190 ;
        RECT 290.230 133.230 290.460 176.045 ;
        RECT 290.850 133.230 291.840 133.580 ;
        RECT 290.230 132.380 291.840 133.230 ;
        RECT 285.650 132.340 286.910 132.380 ;
        RECT 285.650 131.605 285.880 132.340 ;
        RECT 290.230 131.605 290.460 132.380 ;
        RECT 290.850 132.360 291.840 132.380 ;
        RECT 294.810 133.210 295.040 176.045 ;
        RECT 295.560 133.210 296.410 133.600 ;
        RECT 294.810 132.360 296.410 133.210 ;
        RECT 294.810 131.605 295.040 132.360 ;
        RECT 295.560 132.290 296.410 132.360 ;
        RECT 299.390 133.230 299.620 176.045 ;
        RECT 299.940 133.230 300.790 133.650 ;
        RECT 299.390 132.380 300.790 133.230 ;
        RECT 299.390 131.605 299.620 132.380 ;
        RECT 299.940 132.340 300.790 132.380 ;
        RECT 303.970 133.350 304.200 176.045 ;
        RECT 304.480 133.350 305.330 133.790 ;
        RECT 303.970 132.500 305.330 133.350 ;
        RECT 303.970 131.605 304.200 132.500 ;
        RECT 304.480 132.480 305.330 132.500 ;
        RECT 308.550 133.320 308.780 176.045 ;
        RECT 308.990 133.320 310.180 133.500 ;
        RECT 308.550 132.470 310.180 133.320 ;
        RECT 308.550 131.605 308.780 132.470 ;
        RECT 308.990 132.410 310.180 132.470 ;
        RECT 313.130 133.350 313.360 176.045 ;
        RECT 317.710 133.480 317.940 176.045 ;
        RECT 318.420 133.480 319.180 133.800 ;
        RECT 313.690 133.350 314.880 133.420 ;
        RECT 313.130 132.500 314.880 133.350 ;
        RECT 313.130 131.605 313.360 132.500 ;
        RECT 313.690 132.330 314.880 132.500 ;
        RECT 317.710 132.590 319.180 133.480 ;
        RECT 322.290 133.760 322.520 176.045 ;
        RECT 467.630 135.050 467.860 177.825 ;
        RECT 468.230 135.050 469.050 135.280 ;
        RECT 467.630 134.380 469.050 135.050 ;
        RECT 322.290 132.690 323.790 133.760 ;
        RECT 467.630 133.385 467.860 134.380 ;
        RECT 468.230 134.370 469.050 134.380 ;
        RECT 472.210 135.200 472.440 177.825 ;
        RECT 472.950 135.200 473.770 135.390 ;
        RECT 472.210 134.530 473.770 135.200 ;
        RECT 472.210 133.385 472.440 134.530 ;
        RECT 472.950 134.480 473.770 134.530 ;
        RECT 476.790 135.210 477.020 177.825 ;
        RECT 477.410 135.210 478.230 135.410 ;
        RECT 476.790 134.540 478.230 135.210 ;
        RECT 476.790 133.385 477.020 134.540 ;
        RECT 477.410 134.500 478.230 134.540 ;
        RECT 481.370 135.250 481.600 177.825 ;
        RECT 482.070 135.250 482.890 135.460 ;
        RECT 481.370 134.580 482.890 135.250 ;
        RECT 481.370 133.385 481.600 134.580 ;
        RECT 482.070 134.550 482.890 134.580 ;
        RECT 485.950 135.290 486.180 177.825 ;
        RECT 486.520 135.290 487.340 135.530 ;
        RECT 485.950 134.620 487.340 135.290 ;
        RECT 490.530 135.320 490.760 177.825 ;
        RECT 491.070 135.320 491.890 135.590 ;
        RECT 490.530 134.680 491.890 135.320 ;
        RECT 495.110 135.450 495.340 177.825 ;
        RECT 495.680 135.450 496.500 135.670 ;
        RECT 495.110 134.780 496.500 135.450 ;
        RECT 490.530 134.650 491.720 134.680 ;
        RECT 485.950 133.385 486.180 134.620 ;
        RECT 490.530 133.385 490.760 134.650 ;
        RECT 495.110 133.385 495.340 134.780 ;
        RECT 495.680 134.760 496.500 134.780 ;
        RECT 499.690 135.480 499.920 177.825 ;
        RECT 500.350 135.480 501.170 135.690 ;
        RECT 499.690 134.810 501.170 135.480 ;
        RECT 499.690 133.385 499.920 134.810 ;
        RECT 500.350 134.780 501.170 134.810 ;
        RECT 504.270 135.600 504.500 177.825 ;
        RECT 504.870 135.600 505.690 135.730 ;
        RECT 504.270 134.930 505.690 135.600 ;
        RECT 504.270 133.385 504.500 134.930 ;
        RECT 504.870 134.820 505.690 134.930 ;
        RECT 317.710 132.570 318.790 132.590 ;
        RECT 317.710 132.560 318.710 132.570 ;
        RECT 317.710 131.605 317.940 132.560 ;
        RECT 322.290 131.605 322.520 132.690 ;
        RECT 506.640 130.290 509.170 130.340 ;
        RECT 506.600 129.870 509.170 130.290 ;
        RECT 511.390 130.180 518.810 143.420 ;
        RECT 510.530 129.870 518.810 130.180 ;
        RECT 506.600 128.470 518.810 129.870 ;
        RECT 506.600 128.160 516.690 128.470 ;
        RECT 506.600 127.400 509.170 128.160 ;
        RECT 511.500 128.100 516.690 128.160 ;
        RECT 506.600 127.380 509.130 127.400 ;
        RECT 411.990 102.690 412.220 127.240 ;
        RECT 412.520 102.690 413.300 102.900 ;
        RECT 411.990 102.050 413.300 102.690 ;
        RECT 411.990 101.530 412.220 102.050 ;
        RECT 412.520 102.000 413.300 102.050 ;
        RECT 416.570 102.710 416.800 127.240 ;
        RECT 417.080 102.710 418.000 102.980 ;
        RECT 416.570 102.300 418.000 102.710 ;
        RECT 416.570 101.530 416.800 102.300 ;
        RECT 417.080 102.210 418.000 102.300 ;
        RECT 421.150 102.660 421.380 127.240 ;
        RECT 421.730 102.660 422.650 102.830 ;
        RECT 421.150 102.250 422.650 102.660 ;
        RECT 421.150 101.530 421.380 102.250 ;
        RECT 421.730 102.060 422.650 102.250 ;
        RECT 425.730 102.660 425.960 127.240 ;
        RECT 426.440 102.660 427.360 102.850 ;
        RECT 425.730 102.250 427.360 102.660 ;
        RECT 425.730 101.530 425.960 102.250 ;
        RECT 426.440 102.080 427.360 102.250 ;
        RECT 430.310 102.570 430.540 127.240 ;
        RECT 431.050 102.570 431.970 102.900 ;
        RECT 430.310 102.160 431.970 102.570 ;
        RECT 430.310 101.530 430.540 102.160 ;
        RECT 431.050 102.130 431.970 102.160 ;
      LAYER via ;
        RECT 377.550 209.610 379.000 210.090 ;
        RECT 360.530 206.720 360.930 207.400 ;
        RECT 332.930 181.870 334.300 183.870 ;
        RECT 365.160 206.720 365.560 207.400 ;
        RECT 369.600 206.640 370.000 207.320 ;
        RECT 374.180 206.580 374.580 207.260 ;
        RECT 378.830 206.580 379.230 207.260 ;
        RECT 384.400 203.120 385.640 204.690 ;
        RECT 286.470 132.730 287.070 133.300 ;
        RECT 291.020 132.660 291.620 133.230 ;
        RECT 295.620 132.570 296.220 133.140 ;
        RECT 300.190 132.570 300.790 133.140 ;
        RECT 304.640 132.770 305.240 133.340 ;
        RECT 309.420 132.680 309.900 133.290 ;
        RECT 314.060 132.610 314.540 133.220 ;
        RECT 318.490 132.780 319.090 133.350 ;
        RECT 468.370 134.490 468.750 135.050 ;
        RECT 322.940 132.880 323.590 133.490 ;
        RECT 473.220 134.650 473.600 135.210 ;
        RECT 477.580 134.700 477.960 135.260 ;
        RECT 482.250 134.750 482.630 135.310 ;
        RECT 486.670 134.820 487.050 135.380 ;
        RECT 491.330 134.860 491.710 135.420 ;
        RECT 495.810 134.920 496.190 135.480 ;
        RECT 500.590 135.010 500.970 135.570 ;
        RECT 505.120 135.030 505.500 135.590 ;
        RECT 507.210 128.100 508.450 129.280 ;
        RECT 412.670 102.150 413.060 102.630 ;
        RECT 417.270 102.370 417.740 102.690 ;
        RECT 421.910 102.300 422.380 102.620 ;
        RECT 426.680 102.270 427.150 102.590 ;
        RECT 431.290 102.270 431.760 102.590 ;
      LAYER met2 ;
        RECT 454.650 215.410 458.100 215.420 ;
        RECT 421.360 215.400 458.100 215.410 ;
        RECT 418.670 214.600 458.100 215.400 ;
        RECT 377.070 210.160 379.520 210.450 ;
        RECT 360.500 210.150 360.870 210.160 ;
        RECT 363.560 210.150 379.570 210.160 ;
        RECT 360.500 209.260 379.570 210.150 ;
        RECT 360.550 209.230 364.940 209.260 ;
        RECT 360.550 207.600 361.030 209.230 ;
        RECT 365.140 207.650 365.820 209.260 ;
        RECT 360.320 206.450 361.240 207.600 ;
        RECT 364.990 206.500 365.910 207.650 ;
        RECT 369.670 207.560 370.350 209.260 ;
        RECT 369.380 206.880 370.350 207.560 ;
        RECT 374.180 207.540 374.860 209.260 ;
        RECT 369.380 206.410 370.300 206.880 ;
        RECT 373.970 206.390 374.890 207.540 ;
        RECT 378.860 207.420 379.540 209.260 ;
        RECT 378.590 206.770 379.540 207.420 ;
        RECT 378.590 206.270 379.510 206.770 ;
        RECT 383.970 203.800 386.070 204.970 ;
        RECT 418.670 203.800 419.850 214.600 ;
        RECT 456.500 214.560 458.100 214.600 ;
        RECT 456.530 209.170 458.060 214.560 ;
        RECT 383.970 202.950 419.850 203.800 ;
        RECT 383.970 202.880 419.810 202.950 ;
        RECT 383.970 202.310 386.070 202.880 ;
        RECT 331.950 182.960 334.990 184.610 ;
        RECT 282.960 182.930 334.990 182.960 ;
        RECT 276.480 181.870 334.990 182.930 ;
        RECT 276.480 181.840 327.710 181.870 ;
        RECT 276.550 127.590 277.880 181.840 ;
        RECT 331.950 181.170 334.990 181.870 ;
        RECT 456.430 178.580 458.060 209.170 ;
        RECT 456.430 173.650 457.960 178.580 ;
        RECT 456.430 173.640 458.170 173.650 ;
        RECT 456.430 172.290 463.370 173.640 ;
        RECT 456.430 172.220 457.960 172.290 ;
        RECT 286.310 132.380 287.300 133.600 ;
        RECT 286.640 127.590 287.190 132.380 ;
        RECT 290.850 132.360 291.840 133.580 ;
        RECT 291.290 127.590 291.840 132.360 ;
        RECT 295.560 132.290 296.410 133.600 ;
        RECT 299.940 132.340 300.790 133.650 ;
        RECT 304.480 132.480 305.330 133.790 ;
        RECT 295.600 127.590 296.150 132.290 ;
        RECT 300.190 127.590 300.740 132.340 ;
        RECT 304.750 127.590 305.300 132.480 ;
        RECT 308.990 132.410 310.180 133.500 ;
        RECT 309.410 127.590 309.960 132.410 ;
        RECT 313.690 132.330 314.880 133.420 ;
        RECT 318.420 132.590 319.180 133.800 ;
        RECT 322.770 132.650 323.800 133.740 ;
        RECT 314.110 127.590 314.660 132.330 ;
        RECT 318.560 127.590 319.110 132.590 ;
        RECT 323.060 127.590 323.610 132.650 ;
        RECT 450.200 129.480 453.250 129.730 ;
        RECT 450.200 129.370 456.330 129.480 ;
        RECT 462.020 129.370 463.370 172.290 ;
        RECT 468.230 134.370 469.050 135.280 ;
        RECT 472.950 134.480 473.770 135.390 ;
        RECT 477.410 134.500 478.230 135.410 ;
        RECT 482.070 134.550 482.890 135.460 ;
        RECT 486.520 134.620 487.340 135.530 ;
        RECT 491.070 134.680 491.890 135.590 ;
        RECT 495.680 134.760 496.500 135.670 ;
        RECT 500.350 134.780 501.170 135.690 ;
        RECT 504.870 134.820 505.690 135.730 ;
        RECT 468.390 129.470 468.940 134.370 ;
        RECT 473.040 129.470 473.590 134.480 ;
        RECT 477.610 129.470 478.160 134.500 ;
        RECT 482.220 129.470 482.770 134.550 ;
        RECT 486.560 129.470 487.110 134.620 ;
        RECT 491.230 129.470 491.780 134.680 ;
        RECT 495.830 129.470 496.380 134.760 ;
        RECT 500.510 129.470 501.060 134.780 ;
        RECT 504.890 129.470 505.440 134.820 ;
        RECT 468.310 129.450 505.450 129.470 ;
        RECT 506.640 129.450 509.170 130.340 ;
        RECT 468.310 129.370 509.170 129.450 ;
        RECT 435.290 128.230 509.170 129.370 ;
        RECT 276.550 126.330 323.730 127.590 ;
        RECT 276.860 126.300 323.730 126.330 ;
        RECT 412.520 102.000 413.300 102.900 ;
        RECT 417.080 102.210 418.000 102.980 ;
        RECT 412.700 98.130 413.140 102.000 ;
        RECT 417.300 98.130 417.980 102.210 ;
        RECT 421.730 102.060 422.650 102.830 ;
        RECT 426.440 102.080 427.360 102.850 ;
        RECT 431.050 102.830 431.970 102.900 ;
        RECT 431.050 102.130 431.990 102.830 ;
        RECT 421.880 98.130 422.560 102.060 ;
        RECT 426.570 98.130 427.250 102.080 ;
        RECT 431.310 98.130 431.990 102.130 ;
        RECT 435.290 98.130 435.980 128.230 ;
        RECT 450.200 127.990 453.250 128.230 ;
        RECT 468.310 128.210 509.170 128.230 ;
        RECT 468.310 128.170 472.210 128.210 ;
        RECT 476.660 128.170 509.170 128.210 ;
        RECT 471.660 128.160 472.210 128.170 ;
        RECT 503.200 128.140 509.170 128.170 ;
        RECT 506.640 127.400 509.170 128.140 ;
        RECT 412.700 97.590 435.980 98.130 ;
        RECT 412.730 97.560 435.980 97.590 ;
        RECT 412.730 97.540 435.960 97.560 ;
      LAYER via2 ;
        RECT 450.860 128.490 452.510 129.330 ;
      LAYER met3 ;
        RECT 450.200 127.990 453.250 129.730 ;
      LAYER via3 ;
        RECT 450.860 128.490 452.510 129.330 ;
      LAYER met4 ;
        RECT 450.200 127.990 453.250 129.730 ;
        RECT 450.800 127.110 452.230 127.990 ;
        RECT 450.870 125.255 452.230 127.110 ;
        RECT 439.645 98.645 469.255 125.255 ;
        RECT 457.920 96.505 463.040 98.645 ;
        RECT 473.695 98.555 503.305 125.165 ;
        RECT 439.665 69.895 469.275 96.505 ;
        RECT 486.500 96.385 490.740 98.555 ;
        RECT 462.170 68.730 463.750 69.895 ;
        RECT 473.735 69.775 503.345 96.385 ;
        RECT 481.500 68.730 483.620 69.775 ;
        RECT 462.050 67.610 483.620 68.730 ;
    END
  END VOUT
  PIN VDD
    USE POWER ;
    ANTENNADIFFAREA 617.268005 ;
    PORT
      LAYER nwell ;
        RECT 404.490 233.510 415.970 234.460 ;
        RECT 404.490 232.840 448.830 233.510 ;
        RECT 404.490 211.440 451.620 232.840 ;
        RECT 387.970 203.180 451.620 211.440 ;
        RECT 411.430 202.990 451.620 203.180 ;
        RECT 432.640 189.780 451.620 202.990 ;
        RECT 345.790 178.720 384.720 178.870 ;
        RECT 276.560 156.010 384.720 178.720 ;
        RECT 425.170 178.120 509.710 189.780 ;
        RECT 407.230 176.120 509.710 178.120 ;
        RECT 406.990 156.010 509.710 176.120 ;
        RECT 276.560 152.450 509.710 156.010 ;
        RECT 276.560 138.510 384.720 152.450 ;
        RECT 273.090 128.770 384.720 138.510 ;
        RECT 406.990 131.460 509.710 152.450 ;
        RECT 406.990 131.150 428.350 131.460 ;
        RECT 273.090 126.510 358.610 128.770 ;
        RECT 273.090 107.100 358.670 126.510 ;
        RECT 273.090 106.850 394.290 107.100 ;
        RECT 273.090 97.880 403.000 106.850 ;
        RECT 273.090 75.870 388.770 97.880 ;
        RECT 273.090 75.670 371.820 75.870 ;
        RECT 273.090 75.110 355.490 75.670 ;
      LAYER li1 ;
        RECT 324.420 249.880 474.060 250.090 ;
        RECT 324.420 237.120 474.460 249.880 ;
        RECT 325.190 236.900 474.460 237.120 ;
        RECT 409.620 232.100 412.830 236.900 ;
        RECT 404.900 231.930 414.790 232.100 ;
        RECT 404.900 210.440 405.070 231.930 ;
        RECT 409.620 231.910 412.830 231.930 ;
        RECT 405.470 211.165 405.640 231.205 ;
        RECT 414.050 211.165 414.220 231.205 ;
        RECT 414.620 210.440 414.790 231.930 ;
        RECT 440.070 214.570 442.080 236.900 ;
        RECT 404.900 210.270 414.790 210.440 ;
        RECT 390.650 209.740 400.540 209.910 ;
        RECT 390.650 204.850 390.820 209.740 ;
        RECT 391.220 205.575 391.390 209.015 ;
        RECT 399.800 205.575 399.970 209.015 ;
        RECT 400.370 204.850 400.540 209.740 ;
        RECT 440.100 209.030 442.030 214.570 ;
        RECT 390.650 204.680 400.540 204.850 ;
        RECT 433.730 208.860 448.780 209.030 ;
        RECT 433.730 190.700 433.900 208.860 ;
        RECT 448.610 190.700 448.780 208.860 ;
        RECT 433.730 190.530 448.780 190.700 ;
        RECT 299.060 183.990 304.070 187.450 ;
        RECT 433.730 186.000 448.780 186.170 ;
        RECT 299.090 176.960 301.580 183.990 ;
        RECT 282.820 176.790 325.350 176.960 ;
        RECT 282.820 130.860 282.990 176.790 ;
        RECT 283.390 131.585 283.560 176.065 ;
        RECT 287.970 131.585 288.140 176.065 ;
        RECT 292.550 131.585 292.720 176.065 ;
        RECT 297.130 131.585 297.300 176.065 ;
        RECT 301.710 131.585 301.880 176.065 ;
        RECT 306.290 131.585 306.460 176.065 ;
        RECT 310.870 131.585 311.040 176.065 ;
        RECT 315.450 131.585 315.620 176.065 ;
        RECT 320.030 131.585 320.200 176.065 ;
        RECT 324.610 131.585 324.780 176.065 ;
        RECT 325.180 130.860 325.350 176.790 ;
        RECT 332.220 176.800 356.430 176.970 ;
        RECT 332.220 150.310 332.390 176.800 ;
        RECT 356.260 150.310 356.430 176.800 ;
        RECT 365.960 176.800 381.010 176.970 ;
        RECT 365.960 158.640 366.130 176.800 ;
        RECT 366.530 159.365 366.700 176.075 ;
        RECT 371.110 159.365 371.280 176.075 ;
        RECT 375.690 159.365 375.860 176.075 ;
        RECT 380.270 159.365 380.440 176.075 ;
        RECT 380.840 158.640 381.010 176.800 ;
        RECT 365.960 158.470 381.010 158.640 ;
        RECT 409.270 176.820 424.320 176.990 ;
        RECT 409.270 158.660 409.440 176.820 ;
        RECT 409.840 159.385 410.010 176.095 ;
        RECT 414.420 159.385 414.590 176.095 ;
        RECT 419.000 159.385 419.170 176.095 ;
        RECT 423.580 159.385 423.750 176.095 ;
        RECT 424.150 158.660 424.320 176.820 ;
        RECT 433.730 167.840 433.900 186.000 ;
        RECT 434.300 168.565 434.470 185.275 ;
        RECT 438.880 168.565 439.050 185.275 ;
        RECT 443.460 168.565 443.630 185.275 ;
        RECT 448.040 168.565 448.210 185.275 ;
        RECT 448.610 167.840 448.780 186.000 ;
        RECT 433.730 167.670 448.780 167.840 ;
        RECT 464.800 178.570 507.330 178.740 ;
        RECT 409.270 158.490 424.320 158.660 ;
        RECT 433.730 159.130 457.940 159.300 ;
        RECT 332.220 150.140 356.430 150.310 ;
        RECT 365.970 150.740 381.020 150.910 ;
        RECT 282.820 130.690 325.350 130.860 ;
        RECT 341.380 141.610 356.430 141.780 ;
        RECT 341.380 123.450 341.550 141.610 ;
        RECT 341.950 124.175 342.120 140.885 ;
        RECT 346.530 124.175 346.700 140.885 ;
        RECT 351.110 124.175 351.280 140.885 ;
        RECT 355.690 124.175 355.860 140.885 ;
        RECT 356.260 123.450 356.430 141.610 ;
        RECT 365.970 132.580 366.140 150.740 ;
        RECT 366.540 133.305 366.710 150.015 ;
        RECT 371.120 133.305 371.290 150.015 ;
        RECT 375.700 133.305 375.870 150.015 ;
        RECT 380.280 133.305 380.450 150.015 ;
        RECT 380.850 132.580 381.020 150.740 ;
        RECT 365.970 132.410 381.020 132.580 ;
        RECT 409.160 150.800 424.210 150.970 ;
        RECT 409.160 132.640 409.330 150.800 ;
        RECT 409.730 133.365 409.900 150.075 ;
        RECT 414.310 133.365 414.480 150.075 ;
        RECT 418.890 133.365 419.060 150.075 ;
        RECT 423.470 133.365 423.640 150.075 ;
        RECT 424.040 132.640 424.210 150.800 ;
        RECT 409.160 132.470 424.210 132.640 ;
        RECT 433.730 132.640 433.900 159.130 ;
        RECT 457.770 132.640 457.940 159.130 ;
        RECT 433.730 132.470 457.940 132.640 ;
        RECT 464.800 132.640 464.970 178.570 ;
        RECT 465.370 133.365 465.540 177.845 ;
        RECT 469.950 133.365 470.120 177.845 ;
        RECT 474.530 133.365 474.700 177.845 ;
        RECT 479.110 133.365 479.280 177.845 ;
        RECT 483.690 133.365 483.860 177.845 ;
        RECT 488.270 133.365 488.440 177.845 ;
        RECT 492.850 133.365 493.020 177.845 ;
        RECT 497.430 133.365 497.600 177.845 ;
        RECT 502.010 133.365 502.180 177.845 ;
        RECT 506.590 133.365 506.760 177.845 ;
        RECT 507.160 132.640 507.330 178.570 ;
        RECT 464.800 132.470 507.330 132.640 ;
        RECT 341.380 123.280 356.430 123.450 ;
        RECT 341.380 118.750 356.430 118.920 ;
        RECT 341.380 100.590 341.550 118.750 ;
        RECT 356.260 100.590 356.430 118.750 ;
        RECT 341.380 100.420 356.430 100.590 ;
        RECT 390.070 104.560 399.960 104.730 ;
        RECT 390.070 99.670 390.240 104.560 ;
        RECT 390.640 100.395 390.810 103.835 ;
        RECT 399.220 100.395 399.390 103.835 ;
        RECT 399.790 99.670 399.960 104.560 ;
        RECT 390.070 99.500 399.960 99.670 ;
        RECT 375.830 98.960 385.720 99.130 ;
        RECT 375.830 77.470 376.000 98.960 ;
        RECT 376.400 78.195 376.570 98.235 ;
        RECT 384.980 78.195 385.150 98.235 ;
        RECT 385.550 77.470 385.720 98.960 ;
        RECT 375.830 77.300 385.720 77.470 ;
      LAYER mcon ;
        RECT 346.940 240.200 355.890 246.200 ;
        RECT 363.400 241.110 367.570 246.870 ;
        RECT 458.750 240.150 469.220 249.070 ;
        RECT 405.470 211.245 405.640 231.125 ;
        RECT 414.050 211.245 414.220 231.125 ;
        RECT 440.290 211.270 441.880 211.990 ;
        RECT 391.220 205.655 391.390 208.935 ;
        RECT 399.800 205.655 399.970 208.935 ;
        RECT 300.000 184.590 301.030 186.900 ;
        RECT 283.390 131.665 283.560 175.985 ;
        RECT 287.970 131.665 288.140 175.985 ;
        RECT 292.550 131.665 292.720 175.985 ;
        RECT 297.130 131.665 297.300 175.985 ;
        RECT 301.710 131.665 301.880 175.985 ;
        RECT 306.290 131.665 306.460 175.985 ;
        RECT 310.870 131.665 311.040 175.985 ;
        RECT 315.450 131.665 315.620 175.985 ;
        RECT 320.030 131.665 320.200 175.985 ;
        RECT 324.610 131.665 324.780 175.985 ;
        RECT 366.530 159.445 366.700 175.995 ;
        RECT 371.110 159.445 371.280 175.995 ;
        RECT 375.690 159.445 375.860 175.995 ;
        RECT 380.270 159.445 380.440 175.995 ;
        RECT 409.840 159.465 410.010 176.015 ;
        RECT 414.420 159.465 414.590 176.015 ;
        RECT 419.000 159.465 419.170 176.015 ;
        RECT 423.580 159.465 423.750 176.015 ;
        RECT 434.300 168.645 434.470 185.195 ;
        RECT 438.880 168.645 439.050 185.195 ;
        RECT 443.460 168.645 443.630 185.195 ;
        RECT 448.040 168.645 448.210 185.195 ;
        RECT 341.950 124.255 342.120 140.805 ;
        RECT 346.530 124.255 346.700 140.805 ;
        RECT 351.110 124.255 351.280 140.805 ;
        RECT 355.690 124.255 355.860 140.805 ;
        RECT 366.540 133.385 366.710 149.935 ;
        RECT 371.120 133.385 371.290 149.935 ;
        RECT 375.700 133.385 375.870 149.935 ;
        RECT 380.280 133.385 380.450 149.935 ;
        RECT 409.730 133.445 409.900 149.995 ;
        RECT 414.310 133.445 414.480 149.995 ;
        RECT 418.890 133.445 419.060 149.995 ;
        RECT 423.470 133.445 423.640 149.995 ;
        RECT 465.370 133.445 465.540 177.765 ;
        RECT 469.950 133.445 470.120 177.765 ;
        RECT 474.530 133.445 474.700 177.765 ;
        RECT 479.110 133.445 479.280 177.765 ;
        RECT 483.690 133.445 483.860 177.765 ;
        RECT 488.270 133.445 488.440 177.765 ;
        RECT 492.850 133.445 493.020 177.765 ;
        RECT 497.430 133.445 497.600 177.765 ;
        RECT 502.010 133.445 502.180 177.765 ;
        RECT 506.590 133.445 506.760 177.765 ;
        RECT 390.640 100.475 390.810 103.755 ;
        RECT 399.220 100.475 399.390 103.755 ;
        RECT 376.400 78.275 376.570 98.155 ;
        RECT 384.980 78.275 385.150 98.155 ;
      LAYER met1 ;
        RECT 392.850 274.680 406.330 288.170 ;
        RECT 392.850 250.090 403.520 274.680 ;
        RECT 324.420 249.880 474.060 250.090 ;
        RECT 324.420 237.120 474.460 249.880 ;
        RECT 325.190 236.900 474.460 237.120 ;
        RECT 327.640 231.700 329.800 236.900 ;
        RECT 408.770 234.720 412.830 236.900 ;
        RECT 327.590 215.130 329.800 231.700 ;
        RECT 403.610 234.400 416.100 234.720 ;
        RECT 403.610 230.940 404.260 234.400 ;
        RECT 409.620 231.910 412.830 234.400 ;
        RECT 405.440 230.940 405.670 231.185 ;
        RECT 414.020 231.060 414.250 231.185 ;
        RECT 415.480 231.060 416.080 234.400 ;
        RECT 403.610 229.910 405.670 230.940 ;
        RECT 413.990 230.310 416.080 231.060 ;
        RECT 403.950 229.890 405.670 229.910 ;
        RECT 299.060 187.430 304.070 187.450 ;
        RECT 327.610 187.430 329.690 215.130 ;
        RECT 405.440 213.110 405.670 229.890 ;
        RECT 389.740 211.320 401.890 211.830 ;
        RECT 389.740 208.590 390.170 211.320 ;
        RECT 391.190 208.590 391.420 208.995 ;
        RECT 399.770 208.710 400.000 208.995 ;
        RECT 401.290 208.750 401.890 211.320 ;
        RECT 404.890 211.185 405.670 213.110 ;
        RECT 414.020 211.185 414.250 230.310 ;
        RECT 404.890 211.170 405.540 211.185 ;
        RECT 401.290 208.710 402.450 208.750 ;
        RECT 404.890 208.710 405.340 211.170 ;
        RECT 389.740 207.760 391.440 208.590 ;
        RECT 389.900 207.650 391.440 207.760 ;
        RECT 399.770 207.870 405.340 208.710 ;
        RECT 391.190 205.595 391.420 207.650 ;
        RECT 399.770 205.595 400.000 207.870 ;
        RECT 299.060 184.020 329.690 187.430 ;
        RECT 299.060 183.990 304.070 184.020 ;
        RECT 280.150 179.340 281.020 179.370 ;
        RECT 327.610 179.340 329.690 184.020 ;
        RECT 280.150 178.210 329.690 179.340 ;
        RECT 409.480 195.470 411.540 195.570 ;
        RECT 427.650 195.470 430.310 236.900 ;
        RECT 440.070 216.370 442.080 236.900 ;
        RECT 450.690 232.180 452.570 236.900 ;
        RECT 451.410 216.370 452.570 232.180 ;
        RECT 440.070 214.570 442.180 216.370 ;
        RECT 440.110 211.150 442.180 214.570 ;
        RECT 451.410 213.520 452.630 216.370 ;
        RECT 409.480 193.630 430.310 195.470 ;
        RECT 409.480 193.520 429.800 193.630 ;
        RECT 280.150 174.850 281.020 178.210 ;
        RECT 283.360 174.850 283.590 176.045 ;
        RECT 280.120 173.250 283.610 174.850 ;
        RECT 287.940 174.610 288.170 176.045 ;
        RECT 288.610 174.610 289.580 174.860 ;
        RECT 287.940 173.590 289.580 174.610 ;
        RECT 292.520 174.670 292.750 176.045 ;
        RECT 293.280 174.670 294.250 174.900 ;
        RECT 292.520 173.640 294.250 174.670 ;
        RECT 287.940 173.580 289.400 173.590 ;
        RECT 283.360 131.605 283.590 173.250 ;
        RECT 287.940 131.605 288.170 173.580 ;
        RECT 292.520 131.605 292.750 173.640 ;
        RECT 293.280 173.630 294.250 173.640 ;
        RECT 297.100 174.690 297.330 176.045 ;
        RECT 297.800 174.690 298.770 174.880 ;
        RECT 297.100 173.660 298.770 174.690 ;
        RECT 297.100 131.605 297.330 173.660 ;
        RECT 297.800 173.610 298.770 173.660 ;
        RECT 301.680 174.670 301.910 176.045 ;
        RECT 302.350 174.670 303.320 174.830 ;
        RECT 301.680 173.640 303.320 174.670 ;
        RECT 301.680 131.605 301.910 173.640 ;
        RECT 302.350 173.560 303.320 173.640 ;
        RECT 306.260 174.740 306.490 176.045 ;
        RECT 306.970 174.740 307.940 175.050 ;
        RECT 306.260 173.780 307.940 174.740 ;
        RECT 310.840 174.670 311.070 176.045 ;
        RECT 311.450 174.670 312.420 174.810 ;
        RECT 306.260 173.710 307.710 173.780 ;
        RECT 306.260 131.605 306.490 173.710 ;
        RECT 310.840 173.640 312.420 174.670 ;
        RECT 310.840 131.605 311.070 173.640 ;
        RECT 311.450 173.540 312.420 173.640 ;
        RECT 315.420 174.560 315.650 176.045 ;
        RECT 316.130 174.560 317.100 174.800 ;
        RECT 315.420 173.530 317.100 174.560 ;
        RECT 320.000 174.540 320.230 176.045 ;
        RECT 324.580 175.740 324.810 176.045 ;
        RECT 327.610 175.740 329.690 178.210 ;
        RECT 320.720 174.540 321.690 174.710 ;
        RECT 315.420 131.605 315.650 173.530 ;
        RECT 320.000 173.510 321.690 174.540 ;
        RECT 320.000 131.605 320.230 173.510 ;
        RECT 320.720 173.440 321.690 173.510 ;
        RECT 324.580 173.860 329.690 175.740 ;
        RECT 324.580 131.605 324.810 173.860 ;
        RECT 327.610 143.820 329.690 173.860 ;
        RECT 363.620 177.870 381.940 178.980 ;
        RECT 409.480 178.960 411.540 193.520 ;
        RECT 409.490 178.520 411.540 178.960 ;
        RECT 363.620 177.840 365.660 177.870 ;
        RECT 366.790 177.860 381.940 177.870 ;
        RECT 363.620 177.260 364.940 177.840 ;
        RECT 371.730 177.830 372.800 177.860 ;
        RECT 376.200 177.850 377.710 177.860 ;
        RECT 376.240 177.840 377.620 177.850 ;
        RECT 363.620 176.040 364.930 177.260 ;
        RECT 363.620 176.010 365.660 176.040 ;
        RECT 366.500 176.010 366.730 176.055 ;
        RECT 363.620 175.240 366.730 176.010 ;
        RECT 363.620 174.560 364.680 175.240 ;
        RECT 363.620 151.700 364.660 174.560 ;
        RECT 366.500 159.385 366.730 175.240 ;
        RECT 371.080 175.560 371.310 176.055 ;
        RECT 371.600 175.560 372.430 175.830 ;
        RECT 371.080 175.220 372.430 175.560 ;
        RECT 371.080 159.385 371.310 175.220 ;
        RECT 371.600 175.070 372.430 175.220 ;
        RECT 375.660 175.530 375.890 176.055 ;
        RECT 380.240 175.950 380.470 176.055 ;
        RECT 381.300 175.950 381.940 177.860 ;
        RECT 376.220 175.530 377.050 175.870 ;
        RECT 375.660 175.220 377.050 175.530 ;
        RECT 380.240 175.500 381.940 175.950 ;
        RECT 408.690 178.490 411.540 178.520 ;
        RECT 419.820 178.490 420.640 178.530 ;
        RECT 408.690 177.720 425.660 178.490 ;
        RECT 408.690 177.710 409.800 177.720 ;
        RECT 415.010 177.710 415.830 177.720 ;
        RECT 419.820 177.710 420.640 177.720 ;
        RECT 408.690 176.590 409.110 177.710 ;
        RECT 408.690 175.900 409.070 176.590 ;
        RECT 409.810 175.900 410.040 176.075 ;
        RECT 408.690 175.530 410.040 175.900 ;
        RECT 408.690 175.520 409.070 175.530 ;
        RECT 375.660 175.190 376.650 175.220 ;
        RECT 375.660 159.385 375.890 175.190 ;
        RECT 380.240 159.385 380.470 175.500 ;
        RECT 381.460 175.490 381.940 175.500 ;
        RECT 409.810 159.405 410.040 175.530 ;
        RECT 414.390 175.770 414.620 176.075 ;
        RECT 415.070 175.770 415.770 175.860 ;
        RECT 414.390 175.380 415.770 175.770 ;
        RECT 414.390 159.405 414.620 175.380 ;
        RECT 415.070 175.230 415.770 175.380 ;
        RECT 418.970 175.770 419.200 176.075 ;
        RECT 419.840 175.770 420.540 175.870 ;
        RECT 418.970 175.380 420.540 175.770 ;
        RECT 418.970 159.405 419.200 175.380 ;
        RECT 419.840 175.240 420.540 175.380 ;
        RECT 423.550 175.500 423.780 176.075 ;
        RECT 424.800 175.500 425.640 177.720 ;
        RECT 423.550 174.570 425.640 175.500 ;
        RECT 423.550 159.405 423.780 174.570 ;
        RECT 363.620 150.140 364.540 151.700 ;
        RECT 363.620 149.570 364.500 150.140 ;
        RECT 363.340 149.540 364.500 149.570 ;
        RECT 360.890 149.500 364.500 149.540 ;
        RECT 356.850 148.320 364.500 149.500 ;
        RECT 356.910 148.290 358.250 148.320 ;
        RECT 360.890 148.290 364.500 148.320 ;
        RECT 356.910 145.110 358.220 148.290 ;
        RECT 356.980 144.550 358.220 145.110 ;
        RECT 327.610 143.550 329.700 143.820 ;
        RECT 331.530 143.550 334.420 144.430 ;
        RECT 327.610 143.520 334.420 143.550 ;
        RECT 347.330 143.540 348.260 143.790 ;
        RECT 351.960 143.540 352.890 143.800 ;
        RECT 356.980 143.540 358.260 144.550 ;
        RECT 341.700 143.520 358.260 143.540 ;
        RECT 327.610 142.860 358.260 143.520 ;
        RECT 327.610 142.740 358.210 142.860 ;
        RECT 327.610 142.200 340.800 142.740 ;
        RECT 331.530 141.310 334.420 142.200 ;
        RECT 339.530 140.530 340.800 142.200 ;
        RECT 341.920 140.530 342.150 140.865 ;
        RECT 339.530 139.570 342.150 140.530 ;
        RECT 340.970 139.520 342.150 139.570 ;
        RECT 341.920 124.195 342.150 139.520 ;
        RECT 346.500 140.220 346.730 140.865 ;
        RECT 347.260 140.220 348.200 140.470 ;
        RECT 346.500 139.480 348.200 140.220 ;
        RECT 351.080 140.150 351.310 140.865 ;
        RECT 351.760 140.150 352.700 140.390 ;
        RECT 346.500 124.195 346.730 139.480 ;
        RECT 351.080 139.410 352.700 140.150 ;
        RECT 351.080 124.195 351.310 139.410 ;
        RECT 351.760 139.400 352.700 139.410 ;
        RECT 355.660 140.280 355.890 140.865 ;
        RECT 357.290 140.320 358.210 142.740 ;
        RECT 357.030 140.290 364.180 140.320 ;
        RECT 357.030 140.280 364.590 140.290 ;
        RECT 355.660 139.610 364.590 140.280 ;
        RECT 355.660 139.570 357.860 139.610 ;
        RECT 355.660 124.195 355.890 139.570 ;
        RECT 363.940 136.470 364.590 139.610 ;
        RECT 366.510 136.490 366.740 149.995 ;
        RECT 365.860 136.480 366.740 136.490 ;
        RECT 365.000 136.470 366.740 136.480 ;
        RECT 363.940 135.620 366.740 136.470 ;
        RECT 364.330 135.020 366.740 135.620 ;
        RECT 364.330 131.510 365.390 135.020 ;
        RECT 366.510 133.325 366.740 135.020 ;
        RECT 371.090 135.040 371.320 149.995 ;
        RECT 371.630 135.040 372.540 135.260 ;
        RECT 371.090 134.400 372.540 135.040 ;
        RECT 371.090 133.325 371.320 134.400 ;
        RECT 371.630 134.360 372.540 134.400 ;
        RECT 375.670 134.880 375.900 149.995 ;
        RECT 376.390 134.880 377.300 135.140 ;
        RECT 375.670 134.240 377.300 134.880 ;
        RECT 380.250 134.860 380.480 149.995 ;
        RECT 381.560 134.860 382.850 134.920 ;
        RECT 380.250 134.240 382.850 134.860 ;
        RECT 375.670 133.325 375.900 134.240 ;
        RECT 380.250 133.325 380.480 134.240 ;
        RECT 381.560 133.720 382.850 134.240 ;
        RECT 407.350 134.340 408.350 134.660 ;
        RECT 409.700 134.380 409.930 150.055 ;
        RECT 409.400 134.340 409.930 134.380 ;
        RECT 407.350 133.890 409.930 134.340 ;
        RECT 407.350 133.530 408.350 133.890 ;
        RECT 409.400 133.870 409.930 133.890 ;
        RECT 409.700 133.385 409.930 133.870 ;
        RECT 414.280 134.750 414.510 150.055 ;
        RECT 414.280 134.740 414.790 134.750 ;
        RECT 414.280 133.760 415.270 134.740 ;
        RECT 418.860 134.640 419.090 150.055 ;
        RECT 423.440 134.900 423.670 150.055 ;
        RECT 424.800 148.170 425.640 174.570 ;
        RECT 432.640 170.420 433.380 170.440 ;
        RECT 434.270 170.420 434.500 185.255 ;
        RECT 432.640 169.480 434.500 170.420 ;
        RECT 432.640 167.230 433.380 169.480 ;
        RECT 434.270 168.585 434.500 169.480 ;
        RECT 437.240 170.130 438.250 170.420 ;
        RECT 438.850 170.130 439.080 185.255 ;
        RECT 437.240 169.400 439.080 170.130 ;
        RECT 441.790 170.210 442.830 170.430 ;
        RECT 443.430 170.210 443.660 185.255 ;
        RECT 441.790 170.090 443.660 170.210 ;
        RECT 446.460 170.190 447.500 170.520 ;
        RECT 448.010 170.190 448.240 185.255 ;
        RECT 446.460 170.160 448.240 170.190 ;
        RECT 437.240 169.280 438.250 169.400 ;
        RECT 437.240 169.270 438.150 169.280 ;
        RECT 438.850 168.585 439.080 169.400 ;
        RECT 441.760 169.480 443.660 170.090 ;
        RECT 441.760 169.290 442.830 169.480 ;
        RECT 443.430 168.585 443.660 169.480 ;
        RECT 446.430 169.460 448.240 170.160 ;
        RECT 446.430 169.380 447.500 169.460 ;
        RECT 446.430 169.360 447.320 169.380 ;
        RECT 448.010 168.585 448.240 169.460 ;
        RECT 451.510 177.580 452.630 213.520 ;
        RECT 470.070 180.460 475.980 181.270 ;
        RECT 470.070 180.400 476.750 180.460 ;
        RECT 462.540 179.860 508.680 180.400 ;
        RECT 462.540 177.580 463.280 179.860 ;
        RECT 471.870 179.760 476.750 179.860 ;
        RECT 465.340 177.580 465.570 177.825 ;
        RECT 451.510 176.460 465.590 177.580 ;
        RECT 469.920 177.300 470.150 177.825 ;
        RECT 470.650 177.300 471.580 177.560 ;
        RECT 451.510 168.120 452.630 176.460 ;
        RECT 451.030 167.230 452.900 168.120 ;
        RECT 432.640 166.510 452.900 167.230 ;
        RECT 432.640 166.470 433.380 166.510 ;
        RECT 451.030 166.410 452.900 166.510 ;
        RECT 424.800 147.230 425.430 148.170 ;
        RECT 424.510 134.900 425.430 147.230 ;
        RECT 423.440 134.870 425.430 134.900 ;
        RECT 418.860 134.630 419.310 134.640 ;
        RECT 418.860 134.030 419.810 134.630 ;
        RECT 423.440 134.220 425.440 134.870 ;
        RECT 423.440 134.210 424.420 134.220 ;
        RECT 414.280 133.750 414.790 133.760 ;
        RECT 414.280 133.385 414.510 133.750 ;
        RECT 418.860 133.385 419.090 134.030 ;
        RECT 423.440 133.385 423.670 134.210 ;
        RECT 424.800 132.120 425.440 134.220 ;
        RECT 465.340 133.385 465.570 176.460 ;
        RECT 469.920 176.330 471.580 177.300 ;
        RECT 469.920 133.385 470.150 176.330 ;
        RECT 470.650 176.280 471.580 176.330 ;
        RECT 474.500 177.070 474.730 177.825 ;
        RECT 475.340 177.070 476.270 177.510 ;
        RECT 474.500 176.230 476.270 177.070 ;
        RECT 479.080 177.080 479.310 177.825 ;
        RECT 479.840 177.080 480.900 177.480 ;
        RECT 479.080 176.280 480.900 177.080 ;
        RECT 483.660 177.000 483.890 177.825 ;
        RECT 484.510 177.000 485.570 177.300 ;
        RECT 488.240 177.000 488.470 177.825 ;
        RECT 489.050 177.000 490.110 177.340 ;
        RECT 479.080 176.240 480.570 176.280 ;
        RECT 474.500 133.385 474.730 176.230 ;
        RECT 479.080 133.385 479.310 176.240 ;
        RECT 483.660 176.160 485.570 177.000 ;
        RECT 488.160 176.160 490.110 177.000 ;
        RECT 483.660 133.385 483.890 176.160 ;
        RECT 484.510 176.100 485.570 176.160 ;
        RECT 488.240 133.385 488.470 176.160 ;
        RECT 489.050 176.140 490.110 176.160 ;
        RECT 492.820 177.000 493.050 177.825 ;
        RECT 493.520 177.000 494.580 177.340 ;
        RECT 492.820 176.160 494.580 177.000 ;
        RECT 492.820 133.385 493.050 176.160 ;
        RECT 493.520 176.140 494.580 176.160 ;
        RECT 497.400 176.900 497.630 177.825 ;
        RECT 498.190 176.900 499.250 177.250 ;
        RECT 497.400 176.060 499.250 176.900 ;
        RECT 497.400 133.385 497.630 176.060 ;
        RECT 498.190 176.050 499.250 176.060 ;
        RECT 501.980 177.020 502.210 177.825 ;
        RECT 502.790 177.020 503.850 177.260 ;
        RECT 501.980 176.180 503.850 177.020 ;
        RECT 501.980 133.385 502.210 176.180 ;
        RECT 502.790 176.060 503.850 176.180 ;
        RECT 506.560 177.230 506.790 177.825 ;
        RECT 507.970 177.230 508.680 179.860 ;
        RECT 506.560 176.760 508.680 177.230 ;
        RECT 506.560 133.385 506.790 176.760 ;
        RECT 507.970 176.740 508.680 176.760 ;
        RECT 381.630 131.530 382.920 131.790 ;
        RECT 424.810 131.600 425.440 132.120 ;
        RECT 371.630 131.510 372.540 131.520 ;
        RECT 380.710 131.510 382.920 131.530 ;
        RECT 364.330 130.900 382.920 131.510 ;
        RECT 407.490 131.020 425.440 131.600 ;
        RECT 407.490 130.980 423.710 131.020 ;
        RECT 407.520 130.970 423.710 130.980 ;
        RECT 366.710 130.890 382.920 130.900 ;
        RECT 371.630 130.620 372.540 130.890 ;
        RECT 376.490 130.600 377.400 130.890 ;
        RECT 380.710 130.870 382.920 130.890 ;
        RECT 381.630 130.590 382.920 130.870 ;
        RECT 374.030 102.880 387.940 102.910 ;
        RECT 390.610 102.880 390.840 103.815 ;
        RECT 374.030 102.790 390.840 102.880 ;
        RECT 374.030 102.730 390.910 102.790 ;
        RECT 373.810 101.800 390.910 102.730 ;
        RECT 399.190 102.480 399.420 103.815 ;
        RECT 400.770 102.480 401.880 102.600 ;
        RECT 399.190 101.860 401.880 102.480 ;
        RECT 373.810 101.770 387.440 101.800 ;
        RECT 368.070 100.450 369.960 101.190 ;
        RECT 373.810 100.450 375.230 101.770 ;
        RECT 368.070 99.350 375.230 100.450 ;
        RECT 368.070 98.920 369.960 99.350 ;
        RECT 373.810 97.400 375.230 99.350 ;
        RECT 386.660 99.580 387.440 101.770 ;
        RECT 390.610 100.415 390.840 101.800 ;
        RECT 399.190 100.415 399.420 101.860 ;
        RECT 386.660 98.290 387.480 99.580 ;
        RECT 400.770 98.290 401.880 101.860 ;
        RECT 376.370 97.400 376.600 98.215 ;
        RECT 373.810 96.190 376.660 97.400 ;
        RECT 384.950 97.180 385.180 98.215 ;
        RECT 386.660 98.200 401.950 98.290 ;
        RECT 386.660 97.920 402.000 98.200 ;
        RECT 386.660 97.610 401.950 97.920 ;
        RECT 386.660 97.180 387.560 97.610 ;
        RECT 384.950 96.220 387.560 97.180 ;
        RECT 373.810 96.150 375.230 96.190 ;
        RECT 376.370 78.215 376.600 96.190 ;
        RECT 384.950 78.215 385.180 96.220 ;
      LAYER via ;
        RECT 394.680 277.250 404.190 285.840 ;
        RECT 318.210 178.540 320.600 179.110 ;
        RECT 288.710 173.790 289.260 174.540 ;
        RECT 293.650 173.810 294.200 174.560 ;
        RECT 298.050 173.780 298.600 174.530 ;
        RECT 302.570 173.780 303.120 174.530 ;
        RECT 307.320 173.940 307.870 174.690 ;
        RECT 311.800 173.730 312.350 174.480 ;
        RECT 316.430 173.740 316.980 174.490 ;
        RECT 320.950 173.640 321.500 174.390 ;
        RECT 371.880 178.050 372.630 178.530 ;
        RECT 376.460 177.970 377.020 178.590 ;
        RECT 371.840 175.170 372.210 175.670 ;
        RECT 376.420 175.320 376.790 175.820 ;
        RECT 415.150 177.860 415.600 178.220 ;
        RECT 419.970 177.950 420.420 178.310 ;
        RECT 415.190 175.350 415.660 175.680 ;
        RECT 420.010 175.390 420.480 175.720 ;
        RECT 331.930 142.220 334.060 143.880 ;
        RECT 347.580 142.910 348.060 143.310 ;
        RECT 352.290 142.930 352.770 143.330 ;
        RECT 347.520 139.850 348.020 140.330 ;
        RECT 352.050 139.670 352.550 140.150 ;
        RECT 371.760 134.550 372.330 135.030 ;
        RECT 376.570 134.480 377.140 134.960 ;
        RECT 381.880 134.000 382.460 134.560 ;
        RECT 407.580 134.330 408.060 134.410 ;
        RECT 407.580 133.810 408.090 134.330 ;
        RECT 407.660 133.790 408.090 133.810 ;
        RECT 414.600 134.020 415.010 134.560 ;
        RECT 437.470 169.430 437.920 170.090 ;
        RECT 442.040 169.480 442.490 170.140 ;
        RECT 446.850 169.560 447.300 170.220 ;
        RECT 472.890 180.100 474.820 180.890 ;
        RECT 470.880 176.540 471.360 177.280 ;
        RECT 451.530 166.780 452.620 167.540 ;
        RECT 419.310 134.140 419.730 134.500 ;
        RECT 475.540 176.510 476.020 177.250 ;
        RECT 480.150 176.540 480.630 177.280 ;
        RECT 484.790 176.410 485.270 177.150 ;
        RECT 489.390 176.390 489.870 177.130 ;
        RECT 493.760 176.380 494.240 177.120 ;
        RECT 498.520 176.330 499.000 177.070 ;
        RECT 503.150 176.260 503.630 177.000 ;
        RECT 371.850 130.870 372.430 131.430 ;
        RECT 376.680 130.750 377.260 131.310 ;
        RECT 382.090 130.910 382.670 131.470 ;
        RECT 407.690 131.200 408.100 131.470 ;
        RECT 414.700 131.170 415.260 131.520 ;
        RECT 419.170 131.210 419.960 131.530 ;
        RECT 368.550 99.510 369.260 100.510 ;
      LAYER met2 ;
        RECT 392.850 274.680 406.330 288.170 ;
        RECT 470.070 180.460 475.980 181.270 ;
        RECT 470.070 180.430 476.750 180.460 ;
        RECT 480.060 180.430 480.390 180.450 ;
        RECT 470.070 179.990 504.140 180.430 ;
        RECT 470.140 179.760 504.140 179.990 ;
        RECT 307.310 179.270 307.800 179.310 ;
        RECT 321.070 179.270 321.560 179.290 ;
        RECT 288.760 179.070 321.560 179.270 ;
        RECT 288.730 178.240 321.560 179.070 ;
        RECT 288.730 174.860 289.220 178.240 ;
        RECT 293.500 174.900 293.990 178.240 ;
        RECT 288.610 173.590 289.580 174.860 ;
        RECT 293.280 173.630 294.250 174.900 ;
        RECT 298.100 174.880 298.590 178.240 ;
        RECT 297.800 173.610 298.770 174.880 ;
        RECT 302.570 174.830 303.060 178.240 ;
        RECT 307.310 175.050 307.800 178.240 ;
        RECT 302.350 173.560 303.320 174.830 ;
        RECT 306.970 173.780 307.940 175.050 ;
        RECT 311.700 174.810 312.190 178.240 ;
        RECT 311.450 173.540 312.420 174.810 ;
        RECT 316.470 174.800 316.960 178.240 ;
        RECT 316.130 173.530 317.100 174.800 ;
        RECT 321.070 174.710 321.560 178.240 ;
        RECT 371.730 177.830 372.800 178.920 ;
        RECT 376.230 177.850 377.250 178.870 ;
        RECT 371.920 175.830 372.310 177.830 ;
        RECT 376.440 175.870 376.800 177.850 ;
        RECT 415.010 177.710 415.830 178.420 ;
        RECT 419.820 177.710 420.640 178.530 ;
        RECT 371.600 175.070 372.430 175.830 ;
        RECT 376.220 175.220 377.050 175.870 ;
        RECT 415.220 175.830 415.660 177.710 ;
        RECT 420.010 175.860 420.450 177.710 ;
        RECT 470.970 177.560 471.300 179.760 ;
        RECT 475.620 179.450 475.960 179.760 ;
        RECT 470.650 176.280 471.580 177.560 ;
        RECT 475.630 177.510 475.960 179.450 ;
        RECT 475.340 176.230 476.270 177.510 ;
        RECT 480.060 177.480 480.390 179.760 ;
        RECT 479.840 176.280 480.900 177.480 ;
        RECT 484.770 177.300 485.100 179.760 ;
        RECT 489.410 177.340 489.740 179.760 ;
        RECT 493.750 177.340 494.080 179.760 ;
        RECT 484.510 176.100 485.570 177.300 ;
        RECT 489.050 176.140 490.110 177.340 ;
        RECT 493.520 176.140 494.580 177.340 ;
        RECT 498.560 177.250 498.890 179.760 ;
        RECT 503.250 177.260 503.580 179.760 ;
        RECT 498.190 176.050 499.250 177.250 ;
        RECT 502.790 176.060 503.850 177.260 ;
        RECT 415.060 175.200 415.760 175.830 ;
        RECT 419.840 175.230 420.540 175.860 ;
        RECT 320.720 173.440 321.690 174.710 ;
        RECT 437.240 169.280 438.250 170.420 ;
        RECT 441.790 169.290 442.830 170.430 ;
        RECT 446.460 169.380 447.500 170.520 ;
        RECT 437.440 167.190 437.960 169.280 ;
        RECT 441.970 167.190 442.490 169.290 ;
        RECT 446.790 167.190 447.310 169.380 ;
        RECT 437.420 167.120 447.310 167.190 ;
        RECT 451.030 167.120 452.900 168.120 ;
        RECT 437.420 166.500 452.900 167.120 ;
        RECT 437.420 166.470 447.280 166.500 ;
        RECT 451.030 166.410 452.900 166.500 ;
        RECT 331.530 141.310 334.420 144.430 ;
        RECT 347.330 142.770 348.260 143.790 ;
        RECT 351.960 142.780 352.890 143.800 ;
        RECT 331.530 136.720 332.990 141.310 ;
        RECT 347.500 140.470 347.970 142.770 ;
        RECT 347.260 139.480 348.200 140.470 ;
        RECT 352.030 140.390 352.500 142.780 ;
        RECT 351.760 139.400 352.700 140.390 ;
        RECT 331.370 135.910 332.990 136.720 ;
        RECT 331.470 135.690 332.990 135.910 ;
        RECT 331.470 97.300 332.710 135.690 ;
        RECT 371.630 134.360 372.540 135.260 ;
        RECT 371.940 131.520 372.360 134.360 ;
        RECT 376.390 134.240 377.300 135.140 ;
        RECT 371.630 130.620 372.540 131.520 ;
        RECT 376.770 131.500 377.190 134.240 ;
        RECT 381.560 133.720 382.850 134.920 ;
        RECT 414.530 134.670 415.160 134.700 ;
        RECT 407.440 133.720 408.280 134.460 ;
        RECT 414.530 133.730 415.240 134.670 ;
        RECT 419.200 134.630 419.610 134.650 ;
        RECT 419.200 134.040 419.810 134.630 ;
        RECT 419.210 134.030 419.810 134.040 ;
        RECT 419.210 134.010 419.770 134.030 ;
        RECT 381.960 131.790 382.710 133.720 ;
        RECT 376.490 130.600 377.400 131.500 ;
        RECT 381.630 130.590 382.920 131.790 ;
        RECT 407.510 131.650 408.120 133.720 ;
        RECT 414.550 133.360 415.070 133.730 ;
        RECT 419.260 133.360 419.770 134.010 ;
        RECT 414.550 132.630 415.050 133.360 ;
        RECT 419.260 132.630 419.760 133.360 ;
        RECT 414.550 131.860 415.070 132.630 ;
        RECT 419.260 132.400 419.770 132.630 ;
        RECT 414.570 131.650 415.070 131.860 ;
        RECT 419.280 131.650 419.770 132.400 ;
        RECT 407.500 130.990 408.170 131.650 ;
        RECT 414.460 130.990 415.390 131.650 ;
        RECT 419.000 130.990 419.960 131.650 ;
        RECT 363.140 100.290 364.320 100.440 ;
        RECT 368.070 100.420 369.960 101.190 ;
        RECT 367.070 100.290 369.960 100.420 ;
        RECT 363.080 98.980 369.960 100.290 ;
        RECT 363.140 97.360 364.320 98.980 ;
        RECT 368.070 98.920 369.960 98.980 ;
        RECT 355.490 97.300 364.440 97.360 ;
        RECT 331.470 96.710 364.440 97.300 ;
        RECT 331.530 96.520 364.440 96.710 ;
        RECT 355.490 96.300 364.440 96.520 ;
      LAYER via2 ;
        RECT 394.520 277.330 404.220 285.920 ;
        RECT 394.680 277.250 404.190 277.330 ;
      LAYER met3 ;
        RECT 391.080 274.910 409.880 293.910 ;
        RECT 392.850 274.680 406.330 274.910 ;
      LAYER via3 ;
        RECT 394.520 277.330 404.220 285.920 ;
        RECT 394.680 277.250 404.190 277.330 ;
      LAYER met4 ;
        RECT 391.080 293.610 409.880 293.910 ;
        RECT 557.960 293.610 572.310 293.810 ;
        RECT 239.980 277.030 572.610 293.610 ;
        RECT 239.980 20.810 250.790 277.030 ;
        RECT 391.080 274.910 410.590 277.030 ;
        RECT 557.960 20.810 572.310 277.030 ;
        RECT 239.980 7.370 572.310 20.810 ;
        RECT 239.980 7.060 250.790 7.370 ;
    END
  END VDD
  OBS
      LAYER pwell ;
        RECT 239.980 7.060 574.650 292 ;
        RECT 390.475 216.085 400.725 228.185 ;
        RECT 356.610 181.140 381.180 208.950 ;
        RECT 389.890 183.260 400.720 192.500 ;
        RECT 413.670 181.170 424.500 190.410 ;
        RECT 389.890 171.420 400.720 180.660 ;
        RECT 385.790 158.300 392.040 167.550 ;
        RECT 398.110 158.290 404.360 167.540 ;
        RECT 385.740 141.840 391.990 151.090 ;
        RECT 398.140 141.880 404.390 151.130 ;
        RECT 389.890 128.750 400.720 137.990 ;
        RECT 365.790 118.990 376.620 128.230 ;
        RECT 389.890 116.910 400.720 126.150 ;
        RECT 408.980 100.480 433.550 128.290 ;
        RECT 389.895 81.215 400.145 93.315 ;
      LAYER li1 ;
        RECT 239.980 7.060 574.650 292 ;
        RECT 405.700 231.420 409.700 231.590 ;
        RECT 409.990 231.420 413.990 231.590 ;
        RECT 390.655 227.835 400.545 228.005 ;
        RECT 390.655 216.435 390.825 227.835 ;
        RECT 391.455 227.325 395.455 227.495 ;
        RECT 395.745 227.325 399.745 227.495 ;
        RECT 395.515 217.115 395.685 227.155 ;
        RECT 391.455 216.775 395.455 216.945 ;
        RECT 395.745 216.775 399.745 216.945 ;
        RECT 400.375 216.435 400.545 227.835 ;
        RECT 390.655 216.265 400.545 216.435 ;
        RECT 409.760 211.165 409.930 231.205 ;
        RECT 405.700 210.780 409.700 210.950 ;
        RECT 409.990 210.780 413.990 210.950 ;
        RECT 391.450 209.230 395.450 209.400 ;
        RECT 395.740 209.230 399.740 209.400 ;
        RECT 356.790 208.600 381.000 208.770 ;
        RECT 356.790 181.490 356.960 208.600 ;
        RECT 357.590 208.090 359.590 208.260 ;
        RECT 359.880 208.090 361.880 208.260 ;
        RECT 362.170 208.090 364.170 208.260 ;
        RECT 364.460 208.090 366.460 208.260 ;
        RECT 366.750 208.090 368.750 208.260 ;
        RECT 369.040 208.090 371.040 208.260 ;
        RECT 371.330 208.090 373.330 208.260 ;
        RECT 373.620 208.090 375.620 208.260 ;
        RECT 375.910 208.090 377.910 208.260 ;
        RECT 378.200 208.090 380.200 208.260 ;
        RECT 357.590 181.830 359.590 182.000 ;
        RECT 359.880 181.830 361.880 182.000 ;
        RECT 362.170 181.830 364.170 182.000 ;
        RECT 364.460 181.830 366.460 182.000 ;
        RECT 366.750 181.830 368.750 182.000 ;
        RECT 369.040 181.830 371.040 182.000 ;
        RECT 371.330 181.830 373.330 182.000 ;
        RECT 373.620 181.830 375.620 182.000 ;
        RECT 375.910 181.830 377.910 182.000 ;
        RECT 378.200 181.830 380.200 182.000 ;
        RECT 380.830 181.490 381.000 208.600 ;
        RECT 395.510 205.575 395.680 209.015 ;
        RECT 434.530 208.350 436.530 208.520 ;
        RECT 436.820 208.350 438.820 208.520 ;
        RECT 439.110 208.350 441.110 208.520 ;
        RECT 441.400 208.350 443.400 208.520 ;
        RECT 443.690 208.350 445.690 208.520 ;
        RECT 445.980 208.350 447.980 208.520 ;
        RECT 391.450 205.190 395.450 205.360 ;
        RECT 395.740 205.190 399.740 205.360 ;
        RECT 390.070 192.150 400.540 192.320 ;
        RECT 390.070 183.610 390.240 192.150 ;
        RECT 390.870 191.640 392.870 191.810 ;
        RECT 393.160 191.640 395.160 191.810 ;
        RECT 395.450 191.640 397.450 191.810 ;
        RECT 397.740 191.640 399.740 191.810 ;
        RECT 392.930 184.290 393.100 191.470 ;
        RECT 397.510 184.290 397.680 191.470 ;
        RECT 390.870 183.950 392.870 184.120 ;
        RECT 393.160 183.950 395.160 184.120 ;
        RECT 395.450 183.950 397.450 184.120 ;
        RECT 397.740 183.950 399.740 184.120 ;
        RECT 400.370 183.610 400.540 192.150 ;
        RECT 434.300 191.425 434.470 208.135 ;
        RECT 436.590 191.425 436.760 208.135 ;
        RECT 438.880 191.425 439.050 208.135 ;
        RECT 441.170 191.425 441.340 208.135 ;
        RECT 443.460 191.425 443.630 208.135 ;
        RECT 445.750 191.425 445.920 208.135 ;
        RECT 448.040 191.425 448.210 208.135 ;
        RECT 434.530 191.040 436.530 191.210 ;
        RECT 436.820 191.040 438.820 191.210 ;
        RECT 439.110 191.040 441.110 191.210 ;
        RECT 441.400 191.040 443.400 191.210 ;
        RECT 443.690 191.040 445.690 191.210 ;
        RECT 445.980 191.040 447.980 191.210 ;
        RECT 390.070 183.440 400.540 183.610 ;
        RECT 413.850 190.060 424.320 190.230 ;
        RECT 356.790 181.320 381.000 181.490 ;
        RECT 413.850 181.520 414.020 190.060 ;
        RECT 414.650 189.550 416.650 189.720 ;
        RECT 416.940 189.550 418.940 189.720 ;
        RECT 419.230 189.550 421.230 189.720 ;
        RECT 421.520 189.550 423.520 189.720 ;
        RECT 416.710 182.200 416.880 189.380 ;
        RECT 421.290 182.200 421.460 189.380 ;
        RECT 414.650 181.860 416.650 182.030 ;
        RECT 416.940 181.860 418.940 182.030 ;
        RECT 419.230 181.860 421.230 182.030 ;
        RECT 421.520 181.860 423.520 182.030 ;
        RECT 424.150 181.520 424.320 190.060 ;
        RECT 434.530 185.490 436.530 185.660 ;
        RECT 436.820 185.490 438.820 185.660 ;
        RECT 439.110 185.490 441.110 185.660 ;
        RECT 441.400 185.490 443.400 185.660 ;
        RECT 443.690 185.490 445.690 185.660 ;
        RECT 445.980 185.490 447.980 185.660 ;
        RECT 413.850 181.350 424.320 181.520 ;
        RECT 390.070 180.310 400.540 180.480 ;
        RECT 283.620 176.280 285.620 176.450 ;
        RECT 285.910 176.280 287.910 176.450 ;
        RECT 288.200 176.280 290.200 176.450 ;
        RECT 290.490 176.280 292.490 176.450 ;
        RECT 292.780 176.280 294.780 176.450 ;
        RECT 295.070 176.280 297.070 176.450 ;
        RECT 297.360 176.280 299.360 176.450 ;
        RECT 299.650 176.280 301.650 176.450 ;
        RECT 301.940 176.280 303.940 176.450 ;
        RECT 304.230 176.280 306.230 176.450 ;
        RECT 306.520 176.280 308.520 176.450 ;
        RECT 308.810 176.280 310.810 176.450 ;
        RECT 311.100 176.280 313.100 176.450 ;
        RECT 313.390 176.280 315.390 176.450 ;
        RECT 315.680 176.280 317.680 176.450 ;
        RECT 317.970 176.280 319.970 176.450 ;
        RECT 320.260 176.280 322.260 176.450 ;
        RECT 322.550 176.280 324.550 176.450 ;
        RECT 333.020 176.290 335.020 176.460 ;
        RECT 335.310 176.290 337.310 176.460 ;
        RECT 337.600 176.290 339.600 176.460 ;
        RECT 339.890 176.290 341.890 176.460 ;
        RECT 342.180 176.290 344.180 176.460 ;
        RECT 344.470 176.290 346.470 176.460 ;
        RECT 346.760 176.290 348.760 176.460 ;
        RECT 349.050 176.290 351.050 176.460 ;
        RECT 351.340 176.290 353.340 176.460 ;
        RECT 353.630 176.290 355.630 176.460 ;
        RECT 366.760 176.290 368.760 176.460 ;
        RECT 369.050 176.290 371.050 176.460 ;
        RECT 371.340 176.290 373.340 176.460 ;
        RECT 373.630 176.290 375.630 176.460 ;
        RECT 375.920 176.290 377.920 176.460 ;
        RECT 378.210 176.290 380.210 176.460 ;
        RECT 332.790 151.035 332.960 176.075 ;
        RECT 335.080 151.035 335.250 176.075 ;
        RECT 337.370 151.035 337.540 176.075 ;
        RECT 339.660 151.035 339.830 176.075 ;
        RECT 341.950 151.035 342.120 176.075 ;
        RECT 344.240 151.035 344.410 176.075 ;
        RECT 346.530 151.035 346.700 176.075 ;
        RECT 348.820 151.035 348.990 176.075 ;
        RECT 351.110 151.035 351.280 176.075 ;
        RECT 353.400 151.035 353.570 176.075 ;
        RECT 355.690 151.035 355.860 176.075 ;
        RECT 368.820 159.365 368.990 176.075 ;
        RECT 373.400 159.365 373.570 176.075 ;
        RECT 377.980 159.365 378.150 176.075 ;
        RECT 390.070 171.770 390.240 180.310 ;
        RECT 390.870 179.800 392.870 179.970 ;
        RECT 393.160 179.800 395.160 179.970 ;
        RECT 395.450 179.800 397.450 179.970 ;
        RECT 397.740 179.800 399.740 179.970 ;
        RECT 392.930 172.450 393.100 179.630 ;
        RECT 397.510 172.450 397.680 179.630 ;
        RECT 390.870 172.110 392.870 172.280 ;
        RECT 393.160 172.110 395.160 172.280 ;
        RECT 395.450 172.110 397.450 172.280 ;
        RECT 397.740 172.110 399.740 172.280 ;
        RECT 400.370 171.770 400.540 180.310 ;
        RECT 410.070 176.310 412.070 176.480 ;
        RECT 412.360 176.310 414.360 176.480 ;
        RECT 414.650 176.310 416.650 176.480 ;
        RECT 416.940 176.310 418.940 176.480 ;
        RECT 419.230 176.310 421.230 176.480 ;
        RECT 421.520 176.310 423.520 176.480 ;
        RECT 390.070 171.600 400.540 171.770 ;
        RECT 385.970 167.200 391.860 167.370 ;
        RECT 366.760 158.980 368.760 159.150 ;
        RECT 369.050 158.980 371.050 159.150 ;
        RECT 371.340 158.980 373.340 159.150 ;
        RECT 373.630 158.980 375.630 159.150 ;
        RECT 375.920 158.980 377.920 159.150 ;
        RECT 378.210 158.980 380.210 159.150 ;
        RECT 385.970 158.650 386.140 167.200 ;
        RECT 386.540 159.330 386.710 166.520 ;
        RECT 388.830 159.330 389.000 166.520 ;
        RECT 391.120 159.330 391.290 166.520 ;
        RECT 391.690 158.650 391.860 167.200 ;
        RECT 385.970 158.480 391.860 158.650 ;
        RECT 398.290 167.190 404.180 167.360 ;
        RECT 398.290 158.640 398.460 167.190 ;
        RECT 398.860 159.320 399.030 166.510 ;
        RECT 401.150 159.320 401.320 166.510 ;
        RECT 403.440 159.320 403.610 166.510 ;
        RECT 404.010 158.640 404.180 167.190 ;
        RECT 412.130 159.385 412.300 176.095 ;
        RECT 416.710 159.385 416.880 176.095 ;
        RECT 421.290 159.385 421.460 176.095 ;
        RECT 436.590 168.565 436.760 185.275 ;
        RECT 441.170 168.565 441.340 185.275 ;
        RECT 445.750 168.565 445.920 185.275 ;
        RECT 465.600 178.060 467.600 178.230 ;
        RECT 467.890 178.060 469.890 178.230 ;
        RECT 470.180 178.060 472.180 178.230 ;
        RECT 472.470 178.060 474.470 178.230 ;
        RECT 474.760 178.060 476.760 178.230 ;
        RECT 477.050 178.060 479.050 178.230 ;
        RECT 479.340 178.060 481.340 178.230 ;
        RECT 481.630 178.060 483.630 178.230 ;
        RECT 483.920 178.060 485.920 178.230 ;
        RECT 486.210 178.060 488.210 178.230 ;
        RECT 488.500 178.060 490.500 178.230 ;
        RECT 490.790 178.060 492.790 178.230 ;
        RECT 493.080 178.060 495.080 178.230 ;
        RECT 495.370 178.060 497.370 178.230 ;
        RECT 497.660 178.060 499.660 178.230 ;
        RECT 499.950 178.060 501.950 178.230 ;
        RECT 502.240 178.060 504.240 178.230 ;
        RECT 504.530 178.060 506.530 178.230 ;
        RECT 434.530 168.180 436.530 168.350 ;
        RECT 436.820 168.180 438.820 168.350 ;
        RECT 439.110 168.180 441.110 168.350 ;
        RECT 441.400 168.180 443.400 168.350 ;
        RECT 443.690 168.180 445.690 168.350 ;
        RECT 445.980 168.180 447.980 168.350 ;
        RECT 410.070 159.000 412.070 159.170 ;
        RECT 412.360 159.000 414.360 159.170 ;
        RECT 414.650 159.000 416.650 159.170 ;
        RECT 416.940 159.000 418.940 159.170 ;
        RECT 419.230 159.000 421.230 159.170 ;
        RECT 421.520 159.000 423.520 159.170 ;
        RECT 398.290 158.470 404.180 158.640 ;
        RECT 434.530 158.620 436.530 158.790 ;
        RECT 436.820 158.620 438.820 158.790 ;
        RECT 439.110 158.620 441.110 158.790 ;
        RECT 441.400 158.620 443.400 158.790 ;
        RECT 443.690 158.620 445.690 158.790 ;
        RECT 445.980 158.620 447.980 158.790 ;
        RECT 448.270 158.620 450.270 158.790 ;
        RECT 450.560 158.620 452.560 158.790 ;
        RECT 452.850 158.620 454.850 158.790 ;
        RECT 455.140 158.620 457.140 158.790 ;
        RECT 333.020 150.650 335.020 150.820 ;
        RECT 335.310 150.650 337.310 150.820 ;
        RECT 337.600 150.650 339.600 150.820 ;
        RECT 339.890 150.650 341.890 150.820 ;
        RECT 342.180 150.650 344.180 150.820 ;
        RECT 344.470 150.650 346.470 150.820 ;
        RECT 346.760 150.650 348.760 150.820 ;
        RECT 349.050 150.650 351.050 150.820 ;
        RECT 351.340 150.650 353.340 150.820 ;
        RECT 353.630 150.650 355.630 150.820 ;
        RECT 385.920 150.740 391.810 150.910 ;
        RECT 366.770 150.230 368.770 150.400 ;
        RECT 369.060 150.230 371.060 150.400 ;
        RECT 371.350 150.230 373.350 150.400 ;
        RECT 373.640 150.230 375.640 150.400 ;
        RECT 375.930 150.230 377.930 150.400 ;
        RECT 378.220 150.230 380.220 150.400 ;
        RECT 342.180 141.100 344.180 141.270 ;
        RECT 344.470 141.100 346.470 141.270 ;
        RECT 346.760 141.100 348.760 141.270 ;
        RECT 349.050 141.100 351.050 141.270 ;
        RECT 351.340 141.100 353.340 141.270 ;
        RECT 353.630 141.100 355.630 141.270 ;
        RECT 283.620 131.200 285.620 131.370 ;
        RECT 285.910 131.200 287.910 131.370 ;
        RECT 288.200 131.200 290.200 131.370 ;
        RECT 290.490 131.200 292.490 131.370 ;
        RECT 292.780 131.200 294.780 131.370 ;
        RECT 295.070 131.200 297.070 131.370 ;
        RECT 297.360 131.200 299.360 131.370 ;
        RECT 299.650 131.200 301.650 131.370 ;
        RECT 301.940 131.200 303.940 131.370 ;
        RECT 304.230 131.200 306.230 131.370 ;
        RECT 306.520 131.200 308.520 131.370 ;
        RECT 308.810 131.200 310.810 131.370 ;
        RECT 311.100 131.200 313.100 131.370 ;
        RECT 313.390 131.200 315.390 131.370 ;
        RECT 315.680 131.200 317.680 131.370 ;
        RECT 317.970 131.200 319.970 131.370 ;
        RECT 320.260 131.200 322.260 131.370 ;
        RECT 322.550 131.200 324.550 131.370 ;
        RECT 344.240 124.175 344.410 140.885 ;
        RECT 348.820 124.175 348.990 140.885 ;
        RECT 353.400 124.175 353.570 140.885 ;
        RECT 368.830 133.305 369.000 150.015 ;
        RECT 373.410 133.305 373.580 150.015 ;
        RECT 377.990 133.305 378.160 150.015 ;
        RECT 385.920 142.190 386.090 150.740 ;
        RECT 386.490 142.870 386.660 150.060 ;
        RECT 388.780 142.870 388.950 150.060 ;
        RECT 391.070 142.870 391.240 150.060 ;
        RECT 391.640 142.190 391.810 150.740 ;
        RECT 385.920 142.020 391.810 142.190 ;
        RECT 398.320 150.780 404.210 150.950 ;
        RECT 398.320 142.230 398.490 150.780 ;
        RECT 398.890 142.910 399.060 150.100 ;
        RECT 401.180 142.910 401.350 150.100 ;
        RECT 403.470 142.910 403.640 150.100 ;
        RECT 404.040 142.230 404.210 150.780 ;
        RECT 409.960 150.440 411.960 150.460 ;
        RECT 412.250 150.440 414.250 150.460 ;
        RECT 414.540 150.440 416.540 150.460 ;
        RECT 416.830 150.440 418.830 150.460 ;
        RECT 419.120 150.440 421.120 150.460 ;
        RECT 421.410 150.440 423.410 150.460 ;
        RECT 409.960 150.290 423.410 150.440 ;
        RECT 410.050 150.270 423.320 150.290 ;
        RECT 398.320 142.060 404.210 142.230 ;
        RECT 390.070 137.640 400.540 137.810 ;
        RECT 366.770 132.920 368.770 133.090 ;
        RECT 369.060 132.920 371.060 133.090 ;
        RECT 371.350 132.920 373.350 133.090 ;
        RECT 373.640 132.920 375.640 133.090 ;
        RECT 375.930 132.920 377.930 133.090 ;
        RECT 378.220 132.920 380.220 133.090 ;
        RECT 390.070 129.100 390.240 137.640 ;
        RECT 390.870 137.130 392.870 137.300 ;
        RECT 393.160 137.130 395.160 137.300 ;
        RECT 395.450 137.130 397.450 137.300 ;
        RECT 397.740 137.130 399.740 137.300 ;
        RECT 392.930 129.780 393.100 136.960 ;
        RECT 397.510 129.780 397.680 136.960 ;
        RECT 390.870 129.440 392.870 129.610 ;
        RECT 393.160 129.440 395.160 129.610 ;
        RECT 395.450 129.440 397.450 129.610 ;
        RECT 397.740 129.440 399.740 129.610 ;
        RECT 400.370 129.100 400.540 137.640 ;
        RECT 412.020 133.365 412.190 150.075 ;
        RECT 416.600 133.365 416.770 150.075 ;
        RECT 421.180 133.365 421.350 150.075 ;
        RECT 434.300 133.365 434.470 158.405 ;
        RECT 436.590 133.365 436.760 158.405 ;
        RECT 438.880 133.365 439.050 158.405 ;
        RECT 441.170 133.365 441.340 158.405 ;
        RECT 443.460 133.365 443.630 158.405 ;
        RECT 445.750 133.365 445.920 158.405 ;
        RECT 448.040 133.365 448.210 158.405 ;
        RECT 450.330 133.365 450.500 158.405 ;
        RECT 452.620 133.365 452.790 158.405 ;
        RECT 454.910 133.365 455.080 158.405 ;
        RECT 457.200 133.365 457.370 158.405 ;
        RECT 409.960 132.980 411.960 133.150 ;
        RECT 412.250 132.980 414.250 133.150 ;
        RECT 414.540 132.980 416.540 133.150 ;
        RECT 416.830 132.980 418.830 133.150 ;
        RECT 419.120 132.980 421.120 133.150 ;
        RECT 421.410 132.980 423.410 133.150 ;
        RECT 434.530 132.980 436.530 133.150 ;
        RECT 436.820 132.980 438.820 133.150 ;
        RECT 439.110 132.980 441.110 133.150 ;
        RECT 441.400 132.980 443.400 133.150 ;
        RECT 443.690 132.980 445.690 133.150 ;
        RECT 445.980 132.980 447.980 133.150 ;
        RECT 448.270 132.980 450.270 133.150 ;
        RECT 450.560 132.980 452.560 133.150 ;
        RECT 452.850 132.980 454.850 133.150 ;
        RECT 455.140 132.980 457.140 133.150 ;
        RECT 465.600 132.980 467.600 133.150 ;
        RECT 467.890 132.980 469.890 133.150 ;
        RECT 470.180 132.980 472.180 133.150 ;
        RECT 472.470 132.980 474.470 133.150 ;
        RECT 474.760 132.980 476.760 133.150 ;
        RECT 477.050 132.980 479.050 133.150 ;
        RECT 479.340 132.980 481.340 133.150 ;
        RECT 481.630 132.980 483.630 133.150 ;
        RECT 483.920 132.980 485.920 133.150 ;
        RECT 486.210 132.980 488.210 133.150 ;
        RECT 488.500 132.980 490.500 133.150 ;
        RECT 490.790 132.980 492.790 133.150 ;
        RECT 493.080 132.980 495.080 133.150 ;
        RECT 495.370 132.980 497.370 133.150 ;
        RECT 497.660 132.980 499.660 133.150 ;
        RECT 499.950 132.980 501.950 133.150 ;
        RECT 502.240 132.980 504.240 133.150 ;
        RECT 504.530 132.980 506.530 133.150 ;
        RECT 390.070 128.930 400.540 129.100 ;
        RECT 365.970 127.880 376.440 128.050 ;
        RECT 342.180 123.790 344.180 123.960 ;
        RECT 344.470 123.790 346.470 123.960 ;
        RECT 346.760 123.790 348.760 123.960 ;
        RECT 349.050 123.790 351.050 123.960 ;
        RECT 351.340 123.790 353.340 123.960 ;
        RECT 353.630 123.790 355.630 123.960 ;
        RECT 365.970 119.340 366.140 127.880 ;
        RECT 366.770 127.370 368.770 127.540 ;
        RECT 369.060 127.370 371.060 127.540 ;
        RECT 371.350 127.370 373.350 127.540 ;
        RECT 373.640 127.370 375.640 127.540 ;
        RECT 368.830 120.020 369.000 127.200 ;
        RECT 373.410 120.020 373.580 127.200 ;
        RECT 366.770 119.680 368.770 119.850 ;
        RECT 369.060 119.680 371.060 119.850 ;
        RECT 371.350 119.680 373.350 119.850 ;
        RECT 373.640 119.680 375.640 119.850 ;
        RECT 376.270 119.340 376.440 127.880 ;
        RECT 409.160 127.940 433.370 128.110 ;
        RECT 365.970 119.170 376.440 119.340 ;
        RECT 390.070 125.800 400.540 125.970 ;
        RECT 342.180 118.240 344.180 118.410 ;
        RECT 344.470 118.240 346.470 118.410 ;
        RECT 346.760 118.240 348.760 118.410 ;
        RECT 349.050 118.240 351.050 118.410 ;
        RECT 351.340 118.240 353.340 118.410 ;
        RECT 353.630 118.240 355.630 118.410 ;
        RECT 341.950 101.315 342.120 118.025 ;
        RECT 344.240 101.315 344.410 118.025 ;
        RECT 346.530 101.315 346.700 118.025 ;
        RECT 348.820 101.315 348.990 118.025 ;
        RECT 351.110 101.315 351.280 118.025 ;
        RECT 353.400 101.315 353.570 118.025 ;
        RECT 355.690 101.315 355.860 118.025 ;
        RECT 390.070 117.260 390.240 125.800 ;
        RECT 390.870 125.290 392.870 125.460 ;
        RECT 393.160 125.290 395.160 125.460 ;
        RECT 395.450 125.290 397.450 125.460 ;
        RECT 397.740 125.290 399.740 125.460 ;
        RECT 392.930 117.940 393.100 125.120 ;
        RECT 397.510 117.940 397.680 125.120 ;
        RECT 390.870 117.600 392.870 117.770 ;
        RECT 393.160 117.600 395.160 117.770 ;
        RECT 395.450 117.600 397.450 117.770 ;
        RECT 397.740 117.600 399.740 117.770 ;
        RECT 400.370 117.260 400.540 125.800 ;
        RECT 390.070 117.090 400.540 117.260 ;
        RECT 397.450 110.210 403.920 111.440 ;
        RECT 397.450 107.980 403.980 110.210 ;
        RECT 397.450 106.850 403.920 107.980 ;
        RECT 390.870 104.050 394.870 104.220 ;
        RECT 395.160 104.050 399.160 104.220 ;
        RECT 342.180 100.930 344.180 101.100 ;
        RECT 344.470 100.930 346.470 101.100 ;
        RECT 346.760 100.930 348.760 101.100 ;
        RECT 349.050 100.930 351.050 101.100 ;
        RECT 351.340 100.930 353.340 101.100 ;
        RECT 353.630 100.930 355.630 101.100 ;
        RECT 394.930 100.395 395.100 103.835 ;
        RECT 409.160 100.830 409.330 127.940 ;
        RECT 409.960 127.430 411.960 127.600 ;
        RECT 412.250 127.430 414.250 127.600 ;
        RECT 414.540 127.430 416.540 127.600 ;
        RECT 416.830 127.430 418.830 127.600 ;
        RECT 419.120 127.430 421.120 127.600 ;
        RECT 421.410 127.430 423.410 127.600 ;
        RECT 423.700 127.430 425.700 127.600 ;
        RECT 425.990 127.430 427.990 127.600 ;
        RECT 428.280 127.430 430.280 127.600 ;
        RECT 430.570 127.430 432.570 127.600 ;
        RECT 409.960 101.170 411.960 101.340 ;
        RECT 412.250 101.170 414.250 101.340 ;
        RECT 414.540 101.170 416.540 101.340 ;
        RECT 416.830 101.170 418.830 101.340 ;
        RECT 419.120 101.170 421.120 101.340 ;
        RECT 421.410 101.170 423.410 101.340 ;
        RECT 423.700 101.170 425.700 101.340 ;
        RECT 425.990 101.170 427.990 101.340 ;
        RECT 428.280 101.170 430.280 101.340 ;
        RECT 430.570 101.170 432.570 101.340 ;
        RECT 433.200 100.830 433.370 127.940 ;
        RECT 409.160 100.660 433.370 100.830 ;
        RECT 390.870 100.010 394.870 100.180 ;
        RECT 395.160 100.010 399.160 100.180 ;
        RECT 376.630 98.450 380.630 98.620 ;
        RECT 380.920 98.450 384.920 98.620 ;
        RECT 380.690 78.195 380.860 98.235 ;
        RECT 390.075 92.965 399.965 93.135 ;
        RECT 390.075 81.565 390.245 92.965 ;
        RECT 390.875 92.455 394.875 92.625 ;
        RECT 395.165 92.455 399.165 92.625 ;
        RECT 394.935 82.245 395.105 92.285 ;
        RECT 390.875 81.905 394.875 82.075 ;
        RECT 395.165 81.905 399.165 82.075 ;
        RECT 399.795 81.565 399.965 92.965 ;
        RECT 390.075 81.395 399.965 81.565 ;
        RECT 376.630 77.810 380.630 77.980 ;
        RECT 380.920 77.810 384.920 77.980 ;
      LAYER mcon ;
        RECT 239.980 7.060 574.650 292 ;
        RECT 405.780 231.420 409.620 231.590 ;
        RECT 410.070 231.420 413.910 231.590 ;
        RECT 391.535 227.325 395.375 227.495 ;
        RECT 395.825 227.325 399.665 227.495 ;
        RECT 395.515 217.195 395.685 227.075 ;
        RECT 391.535 216.775 395.375 216.945 ;
        RECT 395.825 216.775 399.665 216.945 ;
        RECT 409.760 211.245 409.930 231.125 ;
        RECT 405.780 210.780 409.620 210.950 ;
        RECT 410.070 210.780 413.910 210.950 ;
        RECT 391.530 209.230 395.370 209.400 ;
        RECT 395.820 209.230 399.660 209.400 ;
        RECT 357.670 208.090 359.510 208.260 ;
        RECT 359.960 208.090 361.800 208.260 ;
        RECT 362.250 208.090 364.090 208.260 ;
        RECT 364.540 208.090 366.380 208.260 ;
        RECT 366.830 208.090 368.670 208.260 ;
        RECT 369.120 208.090 370.960 208.260 ;
        RECT 371.410 208.090 373.250 208.260 ;
        RECT 373.700 208.090 375.540 208.260 ;
        RECT 375.990 208.090 377.830 208.260 ;
        RECT 378.280 208.090 380.120 208.260 ;
        RECT 357.670 181.830 359.510 182.000 ;
        RECT 359.960 181.830 361.800 182.000 ;
        RECT 362.250 181.830 364.090 182.000 ;
        RECT 364.540 181.830 366.380 182.000 ;
        RECT 366.830 181.830 368.670 182.000 ;
        RECT 369.120 181.830 370.960 182.000 ;
        RECT 371.410 181.830 373.250 182.000 ;
        RECT 373.700 181.830 375.540 182.000 ;
        RECT 375.990 181.830 377.830 182.000 ;
        RECT 378.280 181.830 380.120 182.000 ;
        RECT 395.510 205.655 395.680 208.935 ;
        RECT 434.610 208.350 436.450 208.520 ;
        RECT 436.900 208.350 438.740 208.520 ;
        RECT 439.190 208.350 441.030 208.520 ;
        RECT 441.480 208.350 443.320 208.520 ;
        RECT 443.770 208.350 445.610 208.520 ;
        RECT 446.060 208.350 447.900 208.520 ;
        RECT 391.530 205.190 395.370 205.360 ;
        RECT 395.820 205.190 399.660 205.360 ;
        RECT 390.950 191.640 392.790 191.810 ;
        RECT 393.240 191.640 395.080 191.810 ;
        RECT 395.530 191.640 397.370 191.810 ;
        RECT 397.820 191.640 399.660 191.810 ;
        RECT 392.930 184.370 393.100 191.390 ;
        RECT 397.510 184.370 397.680 191.390 ;
        RECT 390.950 183.950 392.790 184.120 ;
        RECT 393.240 183.950 395.080 184.120 ;
        RECT 395.530 183.950 397.370 184.120 ;
        RECT 397.820 183.950 399.660 184.120 ;
        RECT 434.300 191.505 434.470 208.055 ;
        RECT 436.590 191.505 436.760 208.055 ;
        RECT 438.880 191.505 439.050 208.055 ;
        RECT 441.170 191.505 441.340 208.055 ;
        RECT 443.460 191.505 443.630 208.055 ;
        RECT 445.750 191.505 445.920 208.055 ;
        RECT 448.040 191.505 448.210 208.055 ;
        RECT 434.610 191.040 436.450 191.210 ;
        RECT 436.900 191.040 438.740 191.210 ;
        RECT 439.190 191.040 441.030 191.210 ;
        RECT 441.480 191.040 443.320 191.210 ;
        RECT 443.770 191.040 445.610 191.210 ;
        RECT 446.060 191.040 447.900 191.210 ;
        RECT 414.730 189.550 416.570 189.720 ;
        RECT 417.020 189.550 418.860 189.720 ;
        RECT 419.310 189.550 421.150 189.720 ;
        RECT 421.600 189.550 423.440 189.720 ;
        RECT 416.710 182.280 416.880 189.300 ;
        RECT 421.290 182.280 421.460 189.300 ;
        RECT 414.730 181.860 416.570 182.030 ;
        RECT 417.020 181.860 418.860 182.030 ;
        RECT 419.310 181.860 421.150 182.030 ;
        RECT 421.600 181.860 423.440 182.030 ;
        RECT 434.610 185.490 436.450 185.660 ;
        RECT 436.900 185.490 438.740 185.660 ;
        RECT 439.190 185.490 441.030 185.660 ;
        RECT 441.480 185.490 443.320 185.660 ;
        RECT 443.770 185.490 445.610 185.660 ;
        RECT 446.060 185.490 447.900 185.660 ;
        RECT 283.700 176.280 285.540 176.450 ;
        RECT 285.990 176.280 287.830 176.450 ;
        RECT 288.280 176.280 290.120 176.450 ;
        RECT 290.570 176.280 292.410 176.450 ;
        RECT 292.860 176.280 294.700 176.450 ;
        RECT 295.150 176.280 296.990 176.450 ;
        RECT 297.440 176.280 299.280 176.450 ;
        RECT 299.730 176.280 301.570 176.450 ;
        RECT 302.020 176.280 303.860 176.450 ;
        RECT 304.310 176.280 306.150 176.450 ;
        RECT 306.600 176.280 308.440 176.450 ;
        RECT 308.890 176.280 310.730 176.450 ;
        RECT 311.180 176.280 313.020 176.450 ;
        RECT 313.470 176.280 315.310 176.450 ;
        RECT 315.760 176.280 317.600 176.450 ;
        RECT 318.050 176.280 319.890 176.450 ;
        RECT 320.340 176.280 322.180 176.450 ;
        RECT 322.630 176.280 324.470 176.450 ;
        RECT 333.100 176.290 334.940 176.460 ;
        RECT 335.390 176.290 337.230 176.460 ;
        RECT 337.680 176.290 339.520 176.460 ;
        RECT 339.970 176.290 341.810 176.460 ;
        RECT 342.260 176.290 344.100 176.460 ;
        RECT 344.550 176.290 346.390 176.460 ;
        RECT 346.840 176.290 348.680 176.460 ;
        RECT 349.130 176.290 350.970 176.460 ;
        RECT 351.420 176.290 353.260 176.460 ;
        RECT 353.710 176.290 355.550 176.460 ;
        RECT 366.840 176.290 368.680 176.460 ;
        RECT 369.130 176.290 370.970 176.460 ;
        RECT 371.420 176.290 373.260 176.460 ;
        RECT 373.710 176.290 375.550 176.460 ;
        RECT 376.000 176.290 377.840 176.460 ;
        RECT 378.290 176.290 380.130 176.460 ;
        RECT 332.790 151.115 332.960 175.995 ;
        RECT 335.080 151.115 335.250 175.995 ;
        RECT 337.370 151.115 337.540 175.995 ;
        RECT 339.660 151.115 339.830 175.995 ;
        RECT 341.950 151.115 342.120 175.995 ;
        RECT 344.240 151.115 344.410 175.995 ;
        RECT 346.530 151.115 346.700 175.995 ;
        RECT 348.820 151.115 348.990 175.995 ;
        RECT 351.110 151.115 351.280 175.995 ;
        RECT 353.400 151.115 353.570 175.995 ;
        RECT 355.690 151.115 355.860 175.995 ;
        RECT 368.820 159.445 368.990 175.995 ;
        RECT 373.400 159.445 373.570 175.995 ;
        RECT 377.980 159.445 378.150 175.995 ;
        RECT 390.950 179.800 392.790 179.970 ;
        RECT 393.240 179.800 395.080 179.970 ;
        RECT 395.530 179.800 397.370 179.970 ;
        RECT 397.820 179.800 399.660 179.970 ;
        RECT 392.930 172.530 393.100 179.550 ;
        RECT 397.510 172.530 397.680 179.550 ;
        RECT 390.950 172.110 392.790 172.280 ;
        RECT 393.240 172.110 395.080 172.280 ;
        RECT 395.530 172.110 397.370 172.280 ;
        RECT 397.820 172.110 399.660 172.280 ;
        RECT 410.150 176.310 411.990 176.480 ;
        RECT 412.440 176.310 414.280 176.480 ;
        RECT 414.730 176.310 416.570 176.480 ;
        RECT 417.020 176.310 418.860 176.480 ;
        RECT 419.310 176.310 421.150 176.480 ;
        RECT 421.600 176.310 423.440 176.480 ;
        RECT 366.840 158.980 368.680 159.150 ;
        RECT 369.130 158.980 370.970 159.150 ;
        RECT 371.420 158.980 373.260 159.150 ;
        RECT 373.710 158.980 375.550 159.150 ;
        RECT 376.000 158.980 377.840 159.150 ;
        RECT 378.290 158.980 380.130 159.150 ;
        RECT 386.540 159.410 386.710 166.440 ;
        RECT 388.830 159.410 389.000 166.440 ;
        RECT 391.120 159.410 391.290 166.440 ;
        RECT 398.860 159.400 399.030 166.430 ;
        RECT 401.150 159.400 401.320 166.430 ;
        RECT 403.440 159.400 403.610 166.430 ;
        RECT 412.130 159.465 412.300 176.015 ;
        RECT 416.710 159.465 416.880 176.015 ;
        RECT 421.290 159.465 421.460 176.015 ;
        RECT 436.590 168.645 436.760 185.195 ;
        RECT 441.170 168.645 441.340 185.195 ;
        RECT 445.750 168.645 445.920 185.195 ;
        RECT 465.680 178.060 467.520 178.230 ;
        RECT 467.970 178.060 469.810 178.230 ;
        RECT 470.260 178.060 472.100 178.230 ;
        RECT 472.550 178.060 474.390 178.230 ;
        RECT 474.840 178.060 476.680 178.230 ;
        RECT 477.130 178.060 478.970 178.230 ;
        RECT 479.420 178.060 481.260 178.230 ;
        RECT 481.710 178.060 483.550 178.230 ;
        RECT 484.000 178.060 485.840 178.230 ;
        RECT 486.290 178.060 488.130 178.230 ;
        RECT 488.580 178.060 490.420 178.230 ;
        RECT 490.870 178.060 492.710 178.230 ;
        RECT 493.160 178.060 495.000 178.230 ;
        RECT 495.450 178.060 497.290 178.230 ;
        RECT 497.740 178.060 499.580 178.230 ;
        RECT 500.030 178.060 501.870 178.230 ;
        RECT 502.320 178.060 504.160 178.230 ;
        RECT 504.610 178.060 506.450 178.230 ;
        RECT 434.610 168.180 436.450 168.350 ;
        RECT 436.900 168.180 438.740 168.350 ;
        RECT 439.190 168.180 441.030 168.350 ;
        RECT 441.480 168.180 443.320 168.350 ;
        RECT 443.770 168.180 445.610 168.350 ;
        RECT 446.060 168.180 447.900 168.350 ;
        RECT 410.150 159.000 411.990 159.170 ;
        RECT 412.440 159.000 414.280 159.170 ;
        RECT 414.730 159.000 416.570 159.170 ;
        RECT 417.020 159.000 418.860 159.170 ;
        RECT 419.310 159.000 421.150 159.170 ;
        RECT 421.600 159.000 423.440 159.170 ;
        RECT 434.610 158.620 436.450 158.790 ;
        RECT 436.900 158.620 438.740 158.790 ;
        RECT 439.190 158.620 441.030 158.790 ;
        RECT 441.480 158.620 443.320 158.790 ;
        RECT 443.770 158.620 445.610 158.790 ;
        RECT 446.060 158.620 447.900 158.790 ;
        RECT 448.350 158.620 450.190 158.790 ;
        RECT 450.640 158.620 452.480 158.790 ;
        RECT 452.930 158.620 454.770 158.790 ;
        RECT 455.220 158.620 457.060 158.790 ;
        RECT 333.100 150.650 334.940 150.820 ;
        RECT 335.390 150.650 337.230 150.820 ;
        RECT 337.680 150.650 339.520 150.820 ;
        RECT 339.970 150.650 341.810 150.820 ;
        RECT 342.260 150.650 344.100 150.820 ;
        RECT 344.550 150.650 346.390 150.820 ;
        RECT 346.840 150.650 348.680 150.820 ;
        RECT 349.130 150.650 350.970 150.820 ;
        RECT 351.420 150.650 353.260 150.820 ;
        RECT 353.710 150.650 355.550 150.820 ;
        RECT 366.850 150.230 368.690 150.400 ;
        RECT 369.140 150.230 370.980 150.400 ;
        RECT 371.430 150.230 373.270 150.400 ;
        RECT 373.720 150.230 375.560 150.400 ;
        RECT 376.010 150.230 377.850 150.400 ;
        RECT 378.300 150.230 380.140 150.400 ;
        RECT 342.260 141.100 344.100 141.270 ;
        RECT 344.550 141.100 346.390 141.270 ;
        RECT 346.840 141.100 348.680 141.270 ;
        RECT 349.130 141.100 350.970 141.270 ;
        RECT 351.420 141.100 353.260 141.270 ;
        RECT 353.710 141.100 355.550 141.270 ;
        RECT 283.700 131.200 285.540 131.370 ;
        RECT 285.990 131.200 287.830 131.370 ;
        RECT 288.280 131.200 290.120 131.370 ;
        RECT 290.570 131.200 292.410 131.370 ;
        RECT 292.860 131.200 294.700 131.370 ;
        RECT 295.150 131.200 296.990 131.370 ;
        RECT 297.440 131.200 299.280 131.370 ;
        RECT 299.730 131.200 301.570 131.370 ;
        RECT 302.020 131.200 303.860 131.370 ;
        RECT 304.310 131.200 306.150 131.370 ;
        RECT 306.600 131.200 308.440 131.370 ;
        RECT 308.890 131.200 310.730 131.370 ;
        RECT 311.180 131.200 313.020 131.370 ;
        RECT 313.470 131.200 315.310 131.370 ;
        RECT 315.760 131.200 317.600 131.370 ;
        RECT 318.050 131.200 319.890 131.370 ;
        RECT 320.340 131.200 322.180 131.370 ;
        RECT 322.630 131.200 324.470 131.370 ;
        RECT 344.240 124.255 344.410 140.805 ;
        RECT 348.820 124.255 348.990 140.805 ;
        RECT 353.400 124.255 353.570 140.805 ;
        RECT 368.830 133.385 369.000 149.935 ;
        RECT 373.410 133.385 373.580 149.935 ;
        RECT 377.990 133.385 378.160 149.935 ;
        RECT 386.490 142.950 386.660 149.980 ;
        RECT 388.780 142.950 388.950 149.980 ;
        RECT 391.070 142.950 391.240 149.980 ;
        RECT 398.890 142.990 399.060 150.020 ;
        RECT 401.180 142.990 401.350 150.020 ;
        RECT 403.470 142.990 403.640 150.020 ;
        RECT 410.040 150.290 411.880 150.460 ;
        RECT 412.330 150.290 414.170 150.460 ;
        RECT 414.620 150.290 416.460 150.460 ;
        RECT 416.910 150.290 418.750 150.460 ;
        RECT 419.200 150.290 421.040 150.460 ;
        RECT 421.490 150.290 423.330 150.460 ;
        RECT 366.850 132.920 368.690 133.090 ;
        RECT 369.140 132.920 370.980 133.090 ;
        RECT 371.430 132.920 373.270 133.090 ;
        RECT 373.720 132.920 375.560 133.090 ;
        RECT 376.010 132.920 377.850 133.090 ;
        RECT 378.300 132.920 380.140 133.090 ;
        RECT 390.950 137.130 392.790 137.300 ;
        RECT 393.240 137.130 395.080 137.300 ;
        RECT 395.530 137.130 397.370 137.300 ;
        RECT 397.820 137.130 399.660 137.300 ;
        RECT 392.930 129.860 393.100 136.880 ;
        RECT 397.510 129.860 397.680 136.880 ;
        RECT 390.950 129.440 392.790 129.610 ;
        RECT 393.240 129.440 395.080 129.610 ;
        RECT 395.530 129.440 397.370 129.610 ;
        RECT 397.820 129.440 399.660 129.610 ;
        RECT 412.020 133.445 412.190 149.995 ;
        RECT 416.600 133.445 416.770 149.995 ;
        RECT 421.180 133.445 421.350 149.995 ;
        RECT 434.300 133.445 434.470 158.325 ;
        RECT 436.590 133.445 436.760 158.325 ;
        RECT 438.880 133.445 439.050 158.325 ;
        RECT 441.170 133.445 441.340 158.325 ;
        RECT 443.460 133.445 443.630 158.325 ;
        RECT 445.750 133.445 445.920 158.325 ;
        RECT 448.040 133.445 448.210 158.325 ;
        RECT 450.330 133.445 450.500 158.325 ;
        RECT 452.620 133.445 452.790 158.325 ;
        RECT 454.910 133.445 455.080 158.325 ;
        RECT 457.200 133.445 457.370 158.325 ;
        RECT 410.040 132.980 411.880 133.150 ;
        RECT 412.330 132.980 414.170 133.150 ;
        RECT 414.620 132.980 416.460 133.150 ;
        RECT 416.910 132.980 418.750 133.150 ;
        RECT 419.200 132.980 421.040 133.150 ;
        RECT 421.490 132.980 423.330 133.150 ;
        RECT 434.610 132.980 436.450 133.150 ;
        RECT 436.900 132.980 438.740 133.150 ;
        RECT 439.190 132.980 441.030 133.150 ;
        RECT 441.480 132.980 443.320 133.150 ;
        RECT 443.770 132.980 445.610 133.150 ;
        RECT 446.060 132.980 447.900 133.150 ;
        RECT 448.350 132.980 450.190 133.150 ;
        RECT 450.640 132.980 452.480 133.150 ;
        RECT 452.930 132.980 454.770 133.150 ;
        RECT 455.220 132.980 457.060 133.150 ;
        RECT 465.680 132.980 467.520 133.150 ;
        RECT 467.970 132.980 469.810 133.150 ;
        RECT 470.260 132.980 472.100 133.150 ;
        RECT 472.550 132.980 474.390 133.150 ;
        RECT 474.840 132.980 476.680 133.150 ;
        RECT 477.130 132.980 478.970 133.150 ;
        RECT 479.420 132.980 481.260 133.150 ;
        RECT 481.710 132.980 483.550 133.150 ;
        RECT 484.000 132.980 485.840 133.150 ;
        RECT 486.290 132.980 488.130 133.150 ;
        RECT 488.580 132.980 490.420 133.150 ;
        RECT 490.870 132.980 492.710 133.150 ;
        RECT 493.160 132.980 495.000 133.150 ;
        RECT 495.450 132.980 497.290 133.150 ;
        RECT 497.740 132.980 499.580 133.150 ;
        RECT 500.030 132.980 501.870 133.150 ;
        RECT 502.320 132.980 504.160 133.150 ;
        RECT 504.610 132.980 506.450 133.150 ;
        RECT 342.260 123.790 344.100 123.960 ;
        RECT 344.550 123.790 346.390 123.960 ;
        RECT 346.840 123.790 348.680 123.960 ;
        RECT 349.130 123.790 350.970 123.960 ;
        RECT 351.420 123.790 353.260 123.960 ;
        RECT 353.710 123.790 355.550 123.960 ;
        RECT 366.850 127.370 368.690 127.540 ;
        RECT 369.140 127.370 370.980 127.540 ;
        RECT 371.430 127.370 373.270 127.540 ;
        RECT 373.720 127.370 375.560 127.540 ;
        RECT 368.830 120.100 369.000 127.120 ;
        RECT 373.410 120.100 373.580 127.120 ;
        RECT 366.850 119.680 368.690 119.850 ;
        RECT 369.140 119.680 370.980 119.850 ;
        RECT 371.430 119.680 373.270 119.850 ;
        RECT 373.720 119.680 375.560 119.850 ;
        RECT 342.260 118.240 344.100 118.410 ;
        RECT 344.550 118.240 346.390 118.410 ;
        RECT 346.840 118.240 348.680 118.410 ;
        RECT 349.130 118.240 350.970 118.410 ;
        RECT 351.420 118.240 353.260 118.410 ;
        RECT 353.710 118.240 355.550 118.410 ;
        RECT 341.950 101.395 342.120 117.945 ;
        RECT 344.240 101.395 344.410 117.945 ;
        RECT 346.530 101.395 346.700 117.945 ;
        RECT 348.820 101.395 348.990 117.945 ;
        RECT 351.110 101.395 351.280 117.945 ;
        RECT 353.400 101.395 353.570 117.945 ;
        RECT 355.690 101.395 355.860 117.945 ;
        RECT 390.950 125.290 392.790 125.460 ;
        RECT 393.240 125.290 395.080 125.460 ;
        RECT 395.530 125.290 397.370 125.460 ;
        RECT 397.820 125.290 399.660 125.460 ;
        RECT 392.930 118.020 393.100 125.040 ;
        RECT 397.510 118.020 397.680 125.040 ;
        RECT 390.950 117.600 392.790 117.770 ;
        RECT 393.240 117.600 395.080 117.770 ;
        RECT 395.530 117.600 397.370 117.770 ;
        RECT 397.820 117.600 399.660 117.770 ;
        RECT 399.610 108.640 402.630 109.350 ;
        RECT 390.950 104.050 394.790 104.220 ;
        RECT 395.240 104.050 399.080 104.220 ;
        RECT 342.260 100.930 344.100 101.100 ;
        RECT 344.550 100.930 346.390 101.100 ;
        RECT 346.840 100.930 348.680 101.100 ;
        RECT 349.130 100.930 350.970 101.100 ;
        RECT 351.420 100.930 353.260 101.100 ;
        RECT 353.710 100.930 355.550 101.100 ;
        RECT 394.930 100.475 395.100 103.755 ;
        RECT 410.040 127.430 411.880 127.600 ;
        RECT 412.330 127.430 414.170 127.600 ;
        RECT 414.620 127.430 416.460 127.600 ;
        RECT 416.910 127.430 418.750 127.600 ;
        RECT 419.200 127.430 421.040 127.600 ;
        RECT 421.490 127.430 423.330 127.600 ;
        RECT 423.780 127.430 425.620 127.600 ;
        RECT 426.070 127.430 427.910 127.600 ;
        RECT 428.360 127.430 430.200 127.600 ;
        RECT 430.650 127.430 432.490 127.600 ;
        RECT 410.040 101.170 411.880 101.340 ;
        RECT 412.330 101.170 414.170 101.340 ;
        RECT 414.620 101.170 416.460 101.340 ;
        RECT 416.910 101.170 418.750 101.340 ;
        RECT 419.200 101.170 421.040 101.340 ;
        RECT 421.490 101.170 423.330 101.340 ;
        RECT 423.780 101.170 425.620 101.340 ;
        RECT 426.070 101.170 427.910 101.340 ;
        RECT 428.360 101.170 430.200 101.340 ;
        RECT 430.650 101.170 432.490 101.340 ;
        RECT 390.950 100.010 394.790 100.180 ;
        RECT 395.240 100.010 399.080 100.180 ;
        RECT 376.710 98.450 380.550 98.620 ;
        RECT 381.000 98.450 384.840 98.620 ;
        RECT 380.690 78.275 380.860 98.155 ;
        RECT 390.955 92.455 394.795 92.625 ;
        RECT 395.245 92.455 399.085 92.625 ;
        RECT 394.935 82.325 395.105 92.205 ;
        RECT 390.955 81.905 394.795 82.075 ;
        RECT 395.245 81.905 399.085 82.075 ;
        RECT 376.710 77.810 380.550 77.980 ;
        RECT 381.000 77.810 384.840 77.980 ;
      LAYER met1 ;
        RECT 239.980 7.060 574.650 292 ;
        RECT 395.090 229.840 397.400 231.860 ;
        RECT 405.720 231.390 409.680 231.620 ;
        RECT 410.010 231.390 413.970 231.620 ;
        RECT 395.150 227.580 396.170 229.840 ;
        RECT 407.800 228.390 409.200 228.490 ;
        RECT 409.730 228.390 409.960 231.185 ;
        RECT 394.980 227.570 396.340 227.580 ;
        RECT 394.750 227.525 396.340 227.570 ;
        RECT 391.475 227.295 399.725 227.525 ;
        RECT 394.750 227.230 396.340 227.295 ;
        RECT 394.980 226.330 396.340 227.230 ;
        RECT 407.790 227.110 409.970 228.390 ;
        RECT 395.485 217.135 395.715 226.330 ;
        RECT 391.475 216.745 395.435 216.975 ;
        RECT 395.765 216.745 399.725 216.975 ;
        RECT 409.730 212.260 409.960 227.110 ;
        RECT 409.210 210.980 411.040 212.260 ;
        RECT 405.720 210.950 413.970 210.980 ;
        RECT 395.370 210.860 396.510 210.940 ;
        RECT 395.340 210.240 396.510 210.860 ;
        RECT 405.720 210.750 414.010 210.950 ;
        RECT 391.470 209.280 399.770 210.240 ;
        RECT 405.760 210.230 414.010 210.750 ;
        RECT 408.930 210.010 414.010 210.230 ;
        RECT 391.470 209.210 399.720 209.280 ;
        RECT 391.470 209.200 395.430 209.210 ;
        RECT 395.760 209.200 399.720 209.210 ;
        RECT 357.610 208.060 359.570 208.290 ;
        RECT 359.900 208.060 361.860 208.290 ;
        RECT 362.190 208.060 364.150 208.290 ;
        RECT 364.480 208.060 366.440 208.290 ;
        RECT 366.770 208.060 368.730 208.290 ;
        RECT 369.060 208.060 371.020 208.290 ;
        RECT 371.350 208.060 373.310 208.290 ;
        RECT 373.640 208.060 375.600 208.290 ;
        RECT 375.930 208.060 377.890 208.290 ;
        RECT 378.220 208.060 380.180 208.290 ;
        RECT 395.480 206.830 395.710 208.995 ;
        RECT 408.930 208.650 411.070 210.010 ;
        RECT 433.330 209.650 447.980 210.740 ;
        RECT 434.550 208.550 447.950 209.650 ;
        RECT 434.550 208.340 447.960 208.550 ;
        RECT 434.550 208.320 436.510 208.340 ;
        RECT 436.840 208.320 438.800 208.340 ;
        RECT 439.130 208.320 441.090 208.340 ;
        RECT 441.420 208.320 443.380 208.340 ;
        RECT 443.710 208.320 445.670 208.340 ;
        RECT 446.000 208.320 447.960 208.340 ;
        RECT 396.400 206.830 397.610 207.590 ;
        RECT 395.480 206.250 397.640 206.830 ;
        RECT 395.480 205.595 395.710 206.250 ;
        RECT 396.400 206.170 397.610 206.250 ;
        RECT 401.460 205.430 403.700 207.030 ;
        RECT 391.470 205.160 395.430 205.390 ;
        RECT 395.760 205.160 399.720 205.390 ;
        RECT 401.960 202.920 402.920 205.430 ;
        RECT 396.980 202.840 402.990 202.920 ;
        RECT 395.380 202.120 402.990 202.840 ;
        RECT 395.380 202.060 397.280 202.120 ;
        RECT 401.960 202.060 402.920 202.120 ;
        RECT 395.380 198.370 396.570 202.060 ;
        RECT 395.380 198.070 396.530 198.370 ;
        RECT 395.420 196.240 396.530 198.070 ;
        RECT 395.420 196.020 396.540 196.240 ;
        RECT 395.430 195.810 396.540 196.020 ;
        RECT 393.660 195.040 396.570 195.810 ;
        RECT 390.890 191.610 392.850 191.840 ;
        RECT 393.180 191.610 395.140 191.840 ;
        RECT 395.470 191.610 397.430 191.840 ;
        RECT 397.760 191.610 399.720 191.840 ;
        RECT 392.900 186.180 393.130 191.450 ;
        RECT 392.900 186.160 393.900 186.180 ;
        RECT 392.900 185.700 394.150 186.160 ;
        RECT 392.900 184.310 393.130 185.700 ;
        RECT 393.370 185.490 394.150 185.700 ;
        RECT 397.480 186.080 397.710 191.450 ;
        RECT 413.900 191.290 415.500 192.680 ;
        RECT 434.270 192.060 434.500 208.115 ;
        RECT 432.970 191.620 434.500 192.060 ;
        RECT 414.950 189.770 415.470 191.290 ;
        RECT 432.970 189.970 433.400 191.620 ;
        RECT 434.270 191.445 434.500 191.620 ;
        RECT 436.560 207.580 436.790 208.115 ;
        RECT 437.170 207.580 438.130 207.700 ;
        RECT 436.560 206.890 438.130 207.580 ;
        RECT 436.560 191.445 436.790 206.890 ;
        RECT 437.170 206.880 438.130 206.890 ;
        RECT 438.850 192.680 439.080 208.115 ;
        RECT 441.140 207.460 441.370 208.115 ;
        RECT 441.860 207.460 442.820 207.620 ;
        RECT 441.140 206.800 442.820 207.460 ;
        RECT 441.140 206.770 442.560 206.800 ;
        RECT 439.350 192.680 440.080 192.770 ;
        RECT 438.850 192.120 440.080 192.680 ;
        RECT 438.850 191.445 439.080 192.120 ;
        RECT 441.140 191.445 441.370 206.770 ;
        RECT 443.430 192.850 443.660 208.115 ;
        RECT 445.720 207.320 445.950 208.115 ;
        RECT 446.350 207.320 447.310 207.450 ;
        RECT 445.720 206.630 447.310 207.320 ;
        RECT 443.870 192.850 444.600 192.920 ;
        RECT 443.430 192.290 444.600 192.850 ;
        RECT 443.430 191.445 443.660 192.290 ;
        RECT 443.870 192.270 444.600 192.290 ;
        RECT 445.720 191.445 445.950 206.630 ;
        RECT 448.010 192.270 448.240 208.115 ;
        RECT 448.010 192.260 449.240 192.270 ;
        RECT 448.010 191.830 449.350 192.260 ;
        RECT 448.010 191.445 448.240 191.830 ;
        RECT 434.550 191.010 436.510 191.240 ;
        RECT 436.840 191.010 438.800 191.240 ;
        RECT 439.130 191.010 441.090 191.240 ;
        RECT 441.420 191.010 443.380 191.240 ;
        RECT 443.710 191.010 445.670 191.240 ;
        RECT 446.000 191.010 447.960 191.240 ;
        RECT 429.110 189.930 433.500 189.970 ;
        RECT 439.440 189.930 440.170 190.030 ;
        RECT 443.910 189.930 444.870 190.120 ;
        RECT 448.990 189.930 449.350 191.830 ;
        RECT 414.950 189.750 422.730 189.770 ;
        RECT 414.670 189.540 423.500 189.750 ;
        RECT 414.670 189.520 416.630 189.540 ;
        RECT 416.960 189.520 418.920 189.540 ;
        RECT 419.250 189.520 421.210 189.540 ;
        RECT 421.540 189.520 423.500 189.540 ;
        RECT 429.110 189.440 449.380 189.930 ;
        RECT 429.110 189.430 433.500 189.440 ;
        RECT 397.480 185.600 398.860 186.080 ;
        RECT 397.480 184.310 397.710 185.600 ;
        RECT 398.110 185.140 398.860 185.600 ;
        RECT 390.890 184.120 392.850 184.150 ;
        RECT 393.180 184.120 395.140 184.150 ;
        RECT 395.470 184.120 397.430 184.150 ;
        RECT 397.760 184.130 399.720 184.150 ;
        RECT 401.350 184.130 402.370 184.410 ;
        RECT 397.760 184.120 404.350 184.130 ;
        RECT 390.890 183.950 404.350 184.120 ;
        RECT 390.890 183.920 404.370 183.950 ;
        RECT 390.910 183.520 404.370 183.920 ;
        RECT 401.350 183.480 402.370 183.520 ;
        RECT 357.610 182.020 359.570 182.030 ;
        RECT 359.900 182.020 361.860 182.030 ;
        RECT 362.190 182.020 364.150 182.030 ;
        RECT 364.480 182.020 366.440 182.030 ;
        RECT 366.770 182.020 368.730 182.030 ;
        RECT 369.060 182.020 371.020 182.030 ;
        RECT 371.350 182.020 373.310 182.030 ;
        RECT 373.640 182.020 375.600 182.030 ;
        RECT 375.930 182.020 377.890 182.030 ;
        RECT 378.220 182.020 380.180 182.030 ;
        RECT 381.350 182.020 382.790 183.360 ;
        RECT 357.610 181.800 382.790 182.020 ;
        RECT 357.680 181.630 382.790 181.800 ;
        RECT 379.890 181.620 382.790 181.630 ;
        RECT 403.620 181.190 404.370 183.520 ;
        RECT 416.680 183.310 416.910 189.360 ;
        RECT 417.380 183.310 417.970 183.520 ;
        RECT 416.680 183.000 417.970 183.310 ;
        RECT 416.680 182.220 416.910 183.000 ;
        RECT 417.380 182.860 417.970 183.000 ;
        RECT 421.260 183.280 421.490 189.360 ;
        RECT 429.110 189.220 429.870 189.430 ;
        RECT 429.140 186.940 429.870 189.220 ;
        RECT 433.890 187.630 434.390 189.440 ;
        RECT 439.440 189.380 440.170 189.440 ;
        RECT 443.910 189.380 444.870 189.440 ;
        RECT 429.140 185.140 429.930 186.940 ;
        RECT 433.850 186.860 434.400 187.630 ;
        RECT 433.840 186.620 434.400 186.860 ;
        RECT 435.220 186.620 436.250 187.390 ;
        RECT 439.590 186.990 440.680 187.590 ;
        RECT 444.200 186.990 445.290 187.600 ;
        RECT 439.000 186.620 441.110 186.990 ;
        RECT 443.690 186.620 445.830 186.990 ;
        RECT 433.840 186.610 445.830 186.620 ;
        RECT 433.840 186.100 446.800 186.610 ;
        RECT 434.580 185.970 446.800 186.100 ;
        RECT 435.120 185.690 446.800 185.970 ;
        RECT 434.550 185.480 447.960 185.690 ;
        RECT 434.550 185.460 436.510 185.480 ;
        RECT 436.840 185.460 438.800 185.480 ;
        RECT 439.130 185.460 441.090 185.480 ;
        RECT 441.420 185.460 443.380 185.480 ;
        RECT 443.710 185.460 445.670 185.480 ;
        RECT 446.000 185.460 447.960 185.480 ;
        RECT 429.140 183.700 430.010 185.140 ;
        RECT 435.350 184.780 436.070 184.990 ;
        RECT 436.560 184.780 436.790 185.255 ;
        RECT 435.350 184.370 436.810 184.780 ;
        RECT 439.630 184.610 440.530 184.820 ;
        RECT 441.140 184.610 441.370 185.255 ;
        RECT 439.630 184.500 441.370 184.610 ;
        RECT 435.350 184.250 436.070 184.370 ;
        RECT 422.050 183.280 422.640 183.450 ;
        RECT 421.260 182.970 422.640 183.280 ;
        RECT 421.260 182.220 421.490 182.970 ;
        RECT 422.050 182.790 422.640 182.970 ;
        RECT 414.670 181.830 416.630 182.060 ;
        RECT 416.960 181.830 418.920 182.060 ;
        RECT 419.250 181.830 421.210 182.060 ;
        RECT 421.540 181.830 423.500 182.060 ;
        RECT 403.590 180.630 406.320 181.190 ;
        RECT 399.400 180.610 406.320 180.630 ;
        RECT 398.420 180.150 406.320 180.610 ;
        RECT 390.880 179.810 406.320 180.150 ;
        RECT 390.880 179.800 399.720 179.810 ;
        RECT 390.890 179.790 399.720 179.800 ;
        RECT 390.890 179.770 392.850 179.790 ;
        RECT 393.180 179.770 395.140 179.790 ;
        RECT 395.470 179.770 397.430 179.790 ;
        RECT 397.760 179.770 399.720 179.790 ;
        RECT 337.900 178.200 339.110 178.580 ;
        RECT 331.140 177.900 357.480 178.200 ;
        RECT 331.110 177.660 357.480 177.900 ;
        RECT 331.110 177.630 356.070 177.660 ;
        RECT 283.640 176.250 285.600 176.480 ;
        RECT 285.930 176.250 287.890 176.480 ;
        RECT 288.220 176.250 290.180 176.480 ;
        RECT 290.510 176.250 292.470 176.480 ;
        RECT 292.800 176.250 294.760 176.480 ;
        RECT 295.090 176.250 297.050 176.480 ;
        RECT 297.380 176.250 299.340 176.480 ;
        RECT 299.670 176.250 301.630 176.480 ;
        RECT 301.960 176.250 303.920 176.480 ;
        RECT 304.250 176.250 306.210 176.480 ;
        RECT 306.540 176.250 308.500 176.480 ;
        RECT 308.830 176.250 310.790 176.480 ;
        RECT 311.120 176.250 313.080 176.480 ;
        RECT 313.410 176.250 315.370 176.480 ;
        RECT 315.700 176.250 317.660 176.480 ;
        RECT 317.990 176.250 319.950 176.480 ;
        RECT 320.280 176.250 322.240 176.480 ;
        RECT 322.570 176.250 324.530 176.480 ;
        RECT 331.110 176.020 331.710 177.630 ;
        RECT 337.900 177.590 339.110 177.630 ;
        RECT 355.770 177.620 356.070 177.630 ;
        RECT 333.040 176.260 335.000 176.490 ;
        RECT 335.330 176.260 337.290 176.490 ;
        RECT 337.620 176.260 339.580 176.490 ;
        RECT 339.910 176.260 341.870 176.490 ;
        RECT 342.200 176.260 344.160 176.490 ;
        RECT 344.490 176.260 346.450 176.490 ;
        RECT 346.780 176.260 348.740 176.490 ;
        RECT 349.070 176.260 351.030 176.490 ;
        RECT 351.360 176.260 353.320 176.490 ;
        RECT 353.650 176.260 355.610 176.490 ;
        RECT 332.760 176.020 332.990 176.055 ;
        RECT 331.110 175.220 332.990 176.020 ;
        RECT 331.400 175.160 332.990 175.220 ;
        RECT 332.760 151.055 332.990 175.160 ;
        RECT 335.050 152.690 335.280 176.055 ;
        RECT 337.340 175.700 337.570 176.055 ;
        RECT 338.010 175.700 339.040 175.820 ;
        RECT 337.340 174.830 339.040 175.700 ;
        RECT 335.700 152.690 336.520 153.130 ;
        RECT 335.050 152.120 336.520 152.690 ;
        RECT 335.050 152.110 336.300 152.120 ;
        RECT 335.050 151.055 335.280 152.110 ;
        RECT 337.340 151.055 337.570 174.830 ;
        RECT 339.630 152.760 339.860 176.055 ;
        RECT 341.920 175.770 342.150 176.055 ;
        RECT 342.660 175.770 343.690 175.860 ;
        RECT 341.920 174.900 343.690 175.770 ;
        RECT 340.240 152.760 341.060 153.150 ;
        RECT 339.630 152.180 341.060 152.760 ;
        RECT 339.630 151.055 339.860 152.180 ;
        RECT 340.240 152.140 341.060 152.180 ;
        RECT 341.920 151.055 342.150 174.900 ;
        RECT 342.660 174.870 343.690 174.900 ;
        RECT 344.210 152.850 344.440 176.055 ;
        RECT 346.500 175.640 346.730 176.055 ;
        RECT 347.240 175.640 348.270 175.850 ;
        RECT 346.500 174.860 348.270 175.640 ;
        RECT 346.500 174.770 347.770 174.860 ;
        RECT 344.810 152.850 345.630 153.280 ;
        RECT 344.210 152.270 345.630 152.850 ;
        RECT 344.210 151.055 344.440 152.270 ;
        RECT 346.500 151.055 346.730 174.770 ;
        RECT 348.790 152.860 349.020 176.055 ;
        RECT 351.080 175.600 351.310 176.055 ;
        RECT 351.880 175.600 352.910 175.690 ;
        RECT 351.060 174.730 352.910 175.600 ;
        RECT 349.580 152.860 350.400 153.260 ;
        RECT 348.790 152.280 350.400 152.860 ;
        RECT 348.790 151.055 349.020 152.280 ;
        RECT 349.580 152.250 350.400 152.280 ;
        RECT 351.080 151.055 351.310 174.730 ;
        RECT 351.880 174.700 352.910 174.730 ;
        RECT 353.370 152.960 353.600 176.055 ;
        RECT 355.660 175.670 355.890 176.055 ;
        RECT 356.970 175.670 357.480 177.660 ;
        RECT 366.780 176.260 368.740 176.490 ;
        RECT 369.070 176.260 371.030 176.490 ;
        RECT 371.360 176.260 373.320 176.490 ;
        RECT 373.650 176.260 375.610 176.490 ;
        RECT 375.940 176.260 377.900 176.490 ;
        RECT 378.230 176.260 380.190 176.490 ;
        RECT 355.660 174.900 357.480 175.670 ;
        RECT 353.970 152.960 354.790 153.420 ;
        RECT 353.370 152.410 354.790 152.960 ;
        RECT 353.370 152.380 354.650 152.410 ;
        RECT 353.370 151.055 353.600 152.380 ;
        RECT 355.660 151.055 355.890 174.900 ;
        RECT 368.790 160.780 369.020 176.055 ;
        RECT 368.780 159.980 370.130 160.780 ;
        RECT 373.370 160.750 373.600 176.055 ;
        RECT 377.950 160.780 378.180 176.055 ;
        RECT 392.900 174.430 393.130 179.610 ;
        RECT 393.380 174.430 394.170 174.590 ;
        RECT 392.900 173.860 394.170 174.430 ;
        RECT 392.900 172.470 393.130 173.860 ;
        RECT 393.380 173.750 394.170 173.860 ;
        RECT 397.480 174.460 397.710 179.610 ;
        RECT 403.590 179.490 406.320 179.810 ;
        RECT 410.090 176.280 412.050 176.510 ;
        RECT 412.380 176.280 414.340 176.510 ;
        RECT 414.670 176.280 416.630 176.510 ;
        RECT 416.960 176.280 418.920 176.510 ;
        RECT 419.250 176.280 421.210 176.510 ;
        RECT 421.540 176.280 423.500 176.510 ;
        RECT 397.910 174.460 398.700 174.600 ;
        RECT 397.480 173.890 398.700 174.460 ;
        RECT 397.480 172.470 397.710 173.890 ;
        RECT 397.910 173.760 398.700 173.890 ;
        RECT 390.890 172.080 392.850 172.310 ;
        RECT 393.180 172.080 395.140 172.310 ;
        RECT 395.470 172.080 397.430 172.310 ;
        RECT 397.760 172.080 399.720 172.310 ;
        RECT 385.510 170.820 387.600 171.260 ;
        RECT 393.410 170.950 394.190 171.150 ;
        RECT 397.810 170.950 398.840 171.070 ;
        RECT 385.510 169.850 387.580 170.820 ;
        RECT 393.410 170.490 398.840 170.950 ;
        RECT 393.410 170.360 394.190 170.490 ;
        RECT 393.420 170.350 394.190 170.360 ;
        RECT 394.600 170.020 395.500 170.490 ;
        RECT 397.810 170.450 398.840 170.490 ;
        RECT 404.940 170.030 406.290 170.940 ;
        RECT 385.510 169.450 387.590 169.850 ;
        RECT 385.510 168.850 393.470 169.450 ;
        RECT 385.510 168.760 387.600 168.850 ;
        RECT 389.410 168.150 389.840 168.200 ;
        RECT 392.770 168.150 393.470 168.850 ;
        RECT 394.370 168.830 395.650 170.020 ;
        RECT 404.930 169.950 406.290 170.030 ;
        RECT 404.930 169.720 406.300 169.950 ;
        RECT 396.140 169.130 406.300 169.720 ;
        RECT 389.360 167.790 393.470 168.150 ;
        RECT 389.410 167.780 389.840 167.790 ;
        RECT 373.370 160.060 374.950 160.750 ;
        RECT 377.950 160.090 379.510 160.780 ;
        RECT 373.370 160.000 374.680 160.060 ;
        RECT 368.790 159.385 369.020 159.980 ;
        RECT 373.370 159.385 373.600 160.000 ;
        RECT 377.950 159.385 378.180 160.090 ;
        RECT 386.510 159.980 386.740 166.500 ;
        RECT 384.830 159.360 386.740 159.980 ;
        RECT 373.480 159.180 374.680 159.230 ;
        RECT 366.780 159.160 368.740 159.180 ;
        RECT 369.070 159.160 371.030 159.180 ;
        RECT 371.360 159.160 373.320 159.180 ;
        RECT 373.480 159.160 375.610 159.180 ;
        RECT 375.940 159.160 377.900 159.180 ;
        RECT 378.230 159.160 380.190 159.180 ;
        RECT 366.770 158.950 380.190 159.160 ;
        RECT 366.770 158.940 380.180 158.950 ;
        RECT 333.040 150.830 335.000 150.850 ;
        RECT 335.330 150.830 339.580 150.850 ;
        RECT 339.910 150.830 341.870 150.850 ;
        RECT 342.200 150.830 344.160 150.850 ;
        RECT 344.490 150.830 346.450 150.850 ;
        RECT 346.780 150.830 348.740 150.850 ;
        RECT 349.070 150.830 351.030 150.850 ;
        RECT 351.360 150.830 353.320 150.850 ;
        RECT 353.650 150.830 355.610 150.850 ;
        RECT 333.030 150.620 355.610 150.830 ;
        RECT 333.030 150.610 355.580 150.620 ;
        RECT 336.080 150.550 337.790 150.610 ;
        RECT 336.080 146.010 337.210 150.550 ;
        RECT 372.970 150.430 374.110 158.940 ;
        RECT 384.830 158.510 385.470 159.360 ;
        RECT 386.510 159.350 386.740 159.360 ;
        RECT 388.800 166.350 389.030 166.500 ;
        RECT 389.410 166.350 389.780 166.360 ;
        RECT 388.800 166.060 389.780 166.350 ;
        RECT 388.800 159.350 389.030 166.060 ;
        RECT 391.090 159.820 391.320 166.500 ;
        RECT 392.770 161.760 393.470 167.790 ;
        RECT 396.140 167.160 396.760 169.130 ;
        RECT 397.590 168.490 403.660 168.500 ;
        RECT 397.590 167.950 405.250 168.490 ;
        RECT 397.590 167.930 404.430 167.950 ;
        RECT 396.140 165.490 396.750 167.160 ;
        RECT 397.590 166.470 397.960 167.930 ;
        RECT 398.830 166.470 399.060 166.490 ;
        RECT 397.590 166.210 399.070 166.470 ;
        RECT 397.590 166.180 398.420 166.210 ;
        RECT 395.970 164.870 396.750 165.490 ;
        RECT 395.970 164.840 396.690 164.870 ;
        RECT 392.770 161.730 394.100 161.760 ;
        RECT 392.770 161.220 397.610 161.730 ;
        RECT 392.780 161.210 397.610 161.220 ;
        RECT 391.090 159.450 394.620 159.820 ;
        RECT 391.090 159.430 392.470 159.450 ;
        RECT 391.090 159.350 391.320 159.430 ;
        RECT 393.820 159.000 394.620 159.450 ;
        RECT 384.560 157.300 385.620 158.510 ;
        RECT 397.010 157.920 397.610 161.210 ;
        RECT 398.830 159.340 399.060 166.210 ;
        RECT 400.190 165.440 400.740 165.780 ;
        RECT 401.120 165.440 401.350 166.490 ;
        RECT 400.190 164.920 401.350 165.440 ;
        RECT 401.120 159.340 401.350 164.920 ;
        RECT 403.410 163.600 403.640 166.490 ;
        RECT 404.810 163.600 405.230 167.950 ;
        RECT 403.410 162.860 405.230 163.600 ;
        RECT 403.410 159.920 403.640 162.860 ;
        RECT 404.470 162.840 405.230 162.860 ;
        RECT 412.100 160.860 412.330 176.075 ;
        RECT 416.680 161.170 416.910 176.075 ;
        RECT 416.680 161.160 417.810 161.170 ;
        RECT 412.500 160.860 413.400 160.980 ;
        RECT 412.100 160.070 413.400 160.860 ;
        RECT 404.900 159.920 405.610 160.070 ;
        RECT 403.410 159.480 405.610 159.920 ;
        RECT 403.410 159.340 403.640 159.480 ;
        RECT 404.900 159.250 405.610 159.480 ;
        RECT 412.100 159.405 412.330 160.070 ;
        RECT 412.500 160.050 413.400 160.070 ;
        RECT 416.680 160.380 418.180 161.160 ;
        RECT 416.680 159.405 416.910 160.380 ;
        RECT 417.280 160.230 418.180 160.380 ;
        RECT 421.260 160.960 421.490 176.075 ;
        RECT 421.950 160.960 422.850 161.100 ;
        RECT 421.260 160.170 422.850 160.960 ;
        RECT 421.260 159.405 421.490 160.170 ;
        RECT 410.090 159.160 412.050 159.200 ;
        RECT 412.380 159.160 414.340 159.200 ;
        RECT 414.670 159.160 416.630 159.200 ;
        RECT 416.960 159.160 418.920 159.200 ;
        RECT 419.250 159.160 421.210 159.200 ;
        RECT 421.540 159.160 423.500 159.200 ;
        RECT 410.090 158.970 423.500 159.160 ;
        RECT 410.150 158.960 423.440 158.970 ;
        RECT 397.010 156.990 398.090 157.920 ;
        RECT 404.800 154.630 406.080 155.770 ;
        RECT 393.450 153.870 394.650 153.950 ;
        RECT 393.450 153.140 394.740 153.870 ;
        RECT 405.030 153.710 405.830 154.630 ;
        RECT 379.870 150.640 381.570 150.670 ;
        RECT 379.870 150.430 382.110 150.640 ;
        RECT 366.790 150.410 368.750 150.430 ;
        RECT 369.080 150.410 371.040 150.430 ;
        RECT 371.370 150.410 375.620 150.430 ;
        RECT 375.950 150.410 377.910 150.430 ;
        RECT 378.240 150.410 382.110 150.430 ;
        RECT 366.770 150.240 382.110 150.410 ;
        RECT 366.770 150.200 380.200 150.240 ;
        RECT 368.800 149.510 369.030 149.995 ;
        RECT 369.280 149.510 369.960 149.630 ;
        RECT 368.780 148.950 369.960 149.510 ;
        RECT 336.080 145.980 337.790 146.010 ;
        RECT 335.410 144.120 338.960 145.980 ;
        RECT 342.200 141.070 344.160 141.300 ;
        RECT 344.490 141.070 346.450 141.300 ;
        RECT 346.780 141.070 348.740 141.300 ;
        RECT 349.070 141.070 351.030 141.300 ;
        RECT 351.360 141.070 353.320 141.300 ;
        RECT 353.650 141.070 355.610 141.300 ;
        RECT 327.860 132.560 330.310 135.070 ;
        RECT 327.890 131.680 330.310 132.560 ;
        RECT 327.890 131.410 329.600 131.680 ;
        RECT 283.580 130.140 329.600 131.410 ;
        RECT 283.580 130.000 329.570 130.140 ;
        RECT 326.140 129.970 329.570 130.000 ;
        RECT 343.010 125.750 343.680 126.030 ;
        RECT 344.210 125.750 344.440 140.865 ;
        RECT 343.010 125.240 344.440 125.750 ;
        RECT 347.080 125.850 347.830 126.130 ;
        RECT 348.790 125.850 349.020 140.865 ;
        RECT 347.080 125.380 349.020 125.850 ;
        RECT 347.080 125.250 347.830 125.380 ;
        RECT 344.210 124.195 344.440 125.240 ;
        RECT 348.790 124.195 349.020 125.380 ;
        RECT 351.730 126.160 352.510 126.200 ;
        RECT 353.370 126.160 353.600 140.865 ;
        RECT 368.800 133.325 369.030 148.950 ;
        RECT 369.280 148.940 369.960 148.950 ;
        RECT 373.380 149.200 373.610 149.995 ;
        RECT 374.070 149.200 374.750 149.320 ;
        RECT 373.380 148.640 374.750 149.200 ;
        RECT 373.380 133.325 373.610 148.640 ;
        RECT 374.070 148.630 374.750 148.640 ;
        RECT 377.960 149.130 378.190 149.995 ;
        RECT 378.780 149.130 379.460 149.230 ;
        RECT 377.960 148.570 379.460 149.130 ;
        RECT 377.960 133.325 378.190 148.570 ;
        RECT 378.780 148.540 379.460 148.570 ;
        RECT 381.460 137.520 382.110 150.240 ;
        RECT 386.040 143.260 386.270 143.270 ;
        RECT 386.460 143.260 386.690 150.040 ;
        RECT 386.020 142.880 386.690 143.260 ;
        RECT 388.750 149.490 388.980 150.040 ;
        RECT 388.750 148.450 390.020 149.490 ;
        RECT 388.750 142.890 388.980 148.450 ;
        RECT 391.040 143.350 391.270 150.040 ;
        RECT 393.450 146.730 394.650 153.140 ;
        RECT 397.560 152.090 398.460 152.380 ;
        RECT 397.530 151.530 398.460 152.090 ;
        RECT 397.560 151.480 398.460 151.530 ;
        RECT 405.030 150.100 405.790 153.710 ;
        RECT 407.770 152.980 409.620 154.320 ;
        RECT 407.650 152.580 409.620 152.980 ;
        RECT 416.220 152.590 417.320 158.960 ;
        RECT 407.650 150.610 408.330 152.580 ;
        RECT 416.220 151.480 417.940 152.590 ;
        RECT 403.480 150.080 405.810 150.100 ;
        RECT 395.820 148.360 397.080 149.650 ;
        RECT 398.860 146.800 399.090 150.080 ;
        RECT 398.540 146.730 399.090 146.800 ;
        RECT 393.450 146.090 399.090 146.730 ;
        RECT 392.350 143.350 392.690 143.360 ;
        RECT 391.040 142.970 392.700 143.350 ;
        RECT 391.040 142.890 391.270 142.970 ;
        RECT 386.040 141.310 386.270 142.880 ;
        RECT 392.350 141.310 392.690 142.970 ;
        RECT 398.480 142.930 399.090 146.090 ;
        RECT 401.150 149.860 401.380 150.080 ;
        RECT 401.700 149.880 402.060 149.910 ;
        RECT 401.690 149.860 402.240 149.880 ;
        RECT 401.150 149.600 402.240 149.860 ;
        RECT 401.150 142.930 401.380 149.600 ;
        RECT 401.690 149.380 402.240 149.600 ;
        RECT 403.440 149.540 405.810 150.080 ;
        RECT 403.440 143.420 403.670 149.540 ;
        RECT 407.190 149.450 408.560 150.610 ;
        RECT 416.220 150.490 417.320 151.480 ;
        RECT 409.980 150.440 411.940 150.490 ;
        RECT 412.270 150.440 414.230 150.490 ;
        RECT 414.560 150.440 418.810 150.490 ;
        RECT 419.140 150.440 421.100 150.490 ;
        RECT 421.430 150.440 423.390 150.490 ;
        RECT 409.980 150.270 423.390 150.440 ;
        RECT 409.980 150.260 411.940 150.270 ;
        RECT 412.270 150.260 414.230 150.270 ;
        RECT 414.560 150.260 416.520 150.270 ;
        RECT 416.850 150.260 418.810 150.270 ;
        RECT 419.140 150.260 421.100 150.270 ;
        RECT 421.430 150.260 423.390 150.270 ;
        RECT 411.990 149.500 412.220 150.055 ;
        RECT 407.390 149.420 408.230 149.450 ;
        RECT 411.990 148.870 413.160 149.500 ;
        RECT 416.570 149.430 416.800 150.055 ;
        RECT 421.150 149.460 421.380 150.055 ;
        RECT 429.140 149.660 430.030 183.700 ;
        RECT 436.560 168.585 436.790 184.370 ;
        RECT 439.600 183.950 441.370 184.500 ;
        RECT 439.600 183.870 440.530 183.950 ;
        RECT 439.630 183.860 440.530 183.870 ;
        RECT 441.140 168.585 441.370 183.950 ;
        RECT 444.430 184.660 445.310 184.830 ;
        RECT 445.720 184.660 445.950 185.255 ;
        RECT 444.430 184.000 445.950 184.660 ;
        RECT 444.430 183.870 445.310 184.000 ;
        RECT 444.430 183.850 444.850 183.870 ;
        RECT 445.720 168.585 445.950 184.000 ;
        RECT 465.620 178.030 467.580 178.260 ;
        RECT 467.910 178.030 469.870 178.260 ;
        RECT 470.200 178.030 472.160 178.260 ;
        RECT 472.490 178.030 474.450 178.260 ;
        RECT 474.780 178.030 476.740 178.260 ;
        RECT 477.070 178.030 479.030 178.260 ;
        RECT 479.360 178.030 481.320 178.260 ;
        RECT 481.650 178.030 483.610 178.260 ;
        RECT 483.940 178.030 485.900 178.260 ;
        RECT 486.230 178.030 488.190 178.260 ;
        RECT 488.520 178.030 490.480 178.260 ;
        RECT 490.810 178.030 492.770 178.260 ;
        RECT 493.100 178.030 495.060 178.260 ;
        RECT 495.390 178.030 497.350 178.260 ;
        RECT 497.680 178.030 499.640 178.260 ;
        RECT 499.970 178.030 501.930 178.260 ;
        RECT 502.260 178.030 504.220 178.260 ;
        RECT 504.550 178.030 506.510 178.260 ;
        RECT 434.550 168.150 436.510 168.380 ;
        RECT 436.840 168.150 438.800 168.380 ;
        RECT 439.130 168.150 441.090 168.380 ;
        RECT 441.420 168.150 443.380 168.380 ;
        RECT 443.710 168.150 445.670 168.380 ;
        RECT 446.000 168.150 447.960 168.380 ;
        RECT 454.720 161.590 456.390 161.740 ;
        RECT 446.650 161.560 458.690 161.590 ;
        RECT 432.980 161.140 458.690 161.560 ;
        RECT 432.980 160.980 433.350 161.140 ;
        RECT 454.710 161.040 458.690 161.140 ;
        RECT 454.710 160.980 458.670 161.040 ;
        RECT 432.980 158.160 433.320 160.980 ;
        RECT 435.380 159.780 436.700 160.770 ;
        RECT 454.720 160.660 458.670 160.980 ;
        RECT 454.720 160.250 456.390 160.660 ;
        RECT 435.760 158.820 436.340 159.780 ;
        RECT 434.550 158.800 436.510 158.820 ;
        RECT 436.840 158.800 438.800 158.820 ;
        RECT 439.130 158.800 441.090 158.820 ;
        RECT 441.420 158.800 443.380 158.820 ;
        RECT 443.710 158.800 445.670 158.820 ;
        RECT 446.000 158.800 447.960 158.820 ;
        RECT 448.290 158.800 450.250 158.820 ;
        RECT 450.580 158.800 452.540 158.820 ;
        RECT 452.870 158.800 454.830 158.820 ;
        RECT 455.160 158.800 457.120 158.820 ;
        RECT 434.550 158.590 457.120 158.800 ;
        RECT 434.270 158.160 434.500 158.385 ;
        RECT 432.980 157.520 434.500 158.160 ;
        RECT 432.990 157.390 434.500 157.520 ;
        RECT 404.520 143.420 404.920 143.430 ;
        RECT 403.440 142.950 404.920 143.420 ;
        RECT 403.440 142.930 403.670 142.950 ;
        RECT 386.040 141.110 386.280 141.310 ;
        RECT 392.350 141.220 392.700 141.310 ;
        RECT 386.050 140.880 386.280 141.110 ;
        RECT 391.820 140.880 392.700 141.220 ;
        RECT 386.050 140.480 392.710 140.880 ;
        RECT 386.050 140.470 386.280 140.480 ;
        RECT 391.820 140.470 392.700 140.480 ;
        RECT 391.820 140.430 392.680 140.470 ;
        RECT 391.850 139.560 392.710 140.020 ;
        RECT 394.430 140.010 396.170 141.620 ;
        RECT 398.480 141.510 398.900 142.930 ;
        RECT 398.480 141.310 398.960 141.510 ;
        RECT 404.510 141.310 404.920 142.950 ;
        RECT 398.480 141.300 398.970 141.310 ;
        RECT 398.190 140.970 399.050 141.300 ;
        RECT 404.510 141.110 404.930 141.310 ;
        RECT 404.520 140.970 404.930 141.110 ;
        RECT 398.180 140.520 404.930 140.970 ;
        RECT 398.190 140.510 399.050 140.520 ;
        RECT 391.550 139.550 392.710 139.560 ;
        RECT 391.000 139.360 392.710 139.550 ;
        RECT 383.620 139.150 392.710 139.360 ;
        RECT 383.620 138.960 391.560 139.150 ;
        RECT 391.850 139.140 392.710 139.150 ;
        RECT 383.620 138.950 391.550 138.960 ;
        RECT 383.620 137.520 384.620 138.950 ;
        RECT 394.670 138.590 395.490 140.010 ;
        RECT 398.110 139.670 399.060 139.940 ;
        RECT 398.110 139.350 399.430 139.670 ;
        RECT 398.110 139.270 406.310 139.350 ;
        RECT 398.910 138.980 406.310 139.270 ;
        RECT 398.910 138.960 399.430 138.980 ;
        RECT 398.030 138.590 398.790 138.620 ;
        RECT 393.460 138.580 395.490 138.590 ;
        RECT 395.840 138.580 398.790 138.590 ;
        RECT 393.460 138.230 398.790 138.580 ;
        RECT 393.460 137.970 394.200 138.230 ;
        RECT 398.030 138.000 398.790 138.230 ;
        RECT 381.460 136.610 384.620 137.520 ;
        RECT 390.890 137.100 392.850 137.330 ;
        RECT 393.180 137.100 395.140 137.330 ;
        RECT 395.470 137.100 397.430 137.330 ;
        RECT 397.760 137.100 399.720 137.330 ;
        RECT 381.460 136.560 382.110 136.610 ;
        RECT 366.790 132.890 368.750 133.120 ;
        RECT 369.080 132.890 371.040 133.120 ;
        RECT 371.370 132.890 373.330 133.120 ;
        RECT 373.660 132.890 375.620 133.120 ;
        RECT 375.950 132.890 377.910 133.120 ;
        RECT 378.240 133.000 380.200 133.120 ;
        RECT 383.620 133.100 384.620 136.610 ;
        RECT 392.900 136.120 393.130 136.940 ;
        RECT 393.470 136.120 394.200 136.270 ;
        RECT 392.900 135.480 394.200 136.120 ;
        RECT 383.510 133.000 384.640 133.100 ;
        RECT 378.240 132.890 384.640 133.000 ;
        RECT 379.440 132.260 384.640 132.890 ;
        RECT 383.510 132.020 384.640 132.260 ;
        RECT 392.900 129.800 393.130 135.480 ;
        RECT 393.470 135.360 394.200 135.480 ;
        RECT 397.480 136.080 397.710 136.940 ;
        RECT 398.120 136.080 398.850 136.240 ;
        RECT 397.480 135.440 398.850 136.080 ;
        RECT 397.480 129.800 397.710 135.440 ;
        RECT 398.120 135.330 398.850 135.440 ;
        RECT 405.270 133.450 406.310 138.980 ;
        RECT 405.270 133.000 407.020 133.450 ;
        RECT 411.990 133.385 412.220 148.870 ;
        RECT 416.570 148.800 417.750 149.430 ;
        RECT 421.150 148.830 422.320 149.460 ;
        RECT 416.570 133.385 416.800 148.800 ;
        RECT 421.150 133.385 421.380 148.830 ;
        RECT 410.060 133.180 410.750 133.190 ;
        RECT 409.980 133.000 411.940 133.180 ;
        RECT 405.270 132.950 411.940 133.000 ;
        RECT 412.270 132.950 414.230 133.180 ;
        RECT 414.560 132.950 416.520 133.180 ;
        RECT 416.850 132.950 418.810 133.180 ;
        RECT 419.140 132.950 421.100 133.180 ;
        RECT 421.430 132.950 423.390 133.180 ;
        RECT 405.270 132.810 410.750 132.950 ;
        RECT 405.270 132.300 410.700 132.810 ;
        RECT 429.100 132.550 430.130 149.660 ;
        RECT 434.270 133.385 434.500 157.390 ;
        RECT 436.560 135.050 436.790 158.385 ;
        RECT 438.850 157.960 439.080 158.385 ;
        RECT 439.720 157.960 440.610 158.100 ;
        RECT 438.850 157.440 440.610 157.960 ;
        RECT 437.180 135.050 438.120 135.350 ;
        RECT 436.560 134.230 438.120 135.050 ;
        RECT 436.560 133.385 436.790 134.230 ;
        RECT 438.850 133.385 439.080 157.440 ;
        RECT 439.720 157.240 440.610 157.440 ;
        RECT 441.140 135.380 441.370 158.385 ;
        RECT 443.430 157.960 443.660 158.385 ;
        RECT 444.390 157.960 445.280 158.100 ;
        RECT 443.430 157.440 445.280 157.960 ;
        RECT 441.700 135.380 442.640 135.710 ;
        RECT 441.140 134.590 442.640 135.380 ;
        RECT 441.140 134.560 442.240 134.590 ;
        RECT 441.140 133.385 441.370 134.560 ;
        RECT 443.430 133.385 443.660 157.440 ;
        RECT 444.390 157.240 445.280 157.440 ;
        RECT 445.720 135.440 445.950 158.385 ;
        RECT 448.010 157.990 448.240 158.385 ;
        RECT 449.010 157.990 449.900 158.120 ;
        RECT 448.010 157.470 449.900 157.990 ;
        RECT 446.420 135.440 447.360 135.710 ;
        RECT 445.720 134.620 447.360 135.440 ;
        RECT 445.720 133.385 445.950 134.620 ;
        RECT 446.420 134.590 447.360 134.620 ;
        RECT 448.010 133.385 448.240 157.470 ;
        RECT 449.010 157.260 449.900 157.470 ;
        RECT 450.300 135.550 450.530 158.385 ;
        RECT 452.590 158.010 452.820 158.385 ;
        RECT 453.340 158.010 454.230 158.120 ;
        RECT 452.590 157.490 454.230 158.010 ;
        RECT 450.960 135.550 451.900 135.850 ;
        RECT 450.300 134.730 451.900 135.550 ;
        RECT 450.300 133.385 450.530 134.730 ;
        RECT 452.590 133.385 452.820 157.490 ;
        RECT 453.340 157.260 454.230 157.490 ;
        RECT 454.880 135.700 455.110 158.385 ;
        RECT 457.170 158.150 457.400 158.385 ;
        RECT 458.350 158.150 458.670 160.660 ;
        RECT 457.170 157.570 458.670 158.150 ;
        RECT 455.590 135.700 456.530 136.010 ;
        RECT 454.880 134.890 456.530 135.700 ;
        RECT 454.880 134.880 456.050 134.890 ;
        RECT 454.880 133.385 455.110 134.880 ;
        RECT 457.170 133.385 457.400 157.570 ;
        RECT 434.550 132.950 436.510 133.180 ;
        RECT 436.840 132.950 438.800 133.180 ;
        RECT 439.130 132.950 441.090 133.180 ;
        RECT 441.420 132.950 443.380 133.180 ;
        RECT 443.710 132.950 445.670 133.180 ;
        RECT 446.000 132.950 447.960 133.180 ;
        RECT 448.290 132.950 450.250 133.180 ;
        RECT 450.580 132.950 452.540 133.180 ;
        RECT 452.870 132.950 454.830 133.180 ;
        RECT 455.160 132.950 457.120 133.180 ;
        RECT 465.620 133.170 467.580 133.180 ;
        RECT 467.910 133.170 469.870 133.180 ;
        RECT 470.200 133.170 472.160 133.180 ;
        RECT 472.490 133.170 474.450 133.180 ;
        RECT 474.780 133.170 476.740 133.180 ;
        RECT 477.070 133.170 479.030 133.180 ;
        RECT 479.360 133.170 481.320 133.180 ;
        RECT 481.650 133.170 483.610 133.180 ;
        RECT 483.940 133.170 485.900 133.180 ;
        RECT 486.230 133.170 488.190 133.180 ;
        RECT 488.520 133.170 490.480 133.180 ;
        RECT 490.810 133.170 492.770 133.180 ;
        RECT 493.100 133.170 495.060 133.180 ;
        RECT 495.390 133.170 497.350 133.180 ;
        RECT 497.680 133.170 499.640 133.180 ;
        RECT 499.970 133.170 501.930 133.180 ;
        RECT 502.260 133.170 504.220 133.180 ;
        RECT 504.550 133.170 506.510 133.180 ;
        RECT 464.470 132.950 506.510 133.170 ;
        RECT 405.270 131.950 407.020 132.300 ;
        RECT 427.720 130.560 430.190 132.550 ;
        RECT 464.470 132.260 506.480 132.950 ;
        RECT 464.470 132.250 506.470 132.260 ;
        RECT 455.330 131.480 458.010 131.730 ;
        RECT 464.480 131.480 465.370 132.250 ;
        RECT 455.330 131.470 464.220 131.480 ;
        RECT 464.470 131.470 465.370 131.480 ;
        RECT 455.330 130.690 465.370 131.470 ;
        RECT 429.100 130.500 430.130 130.560 ;
        RECT 390.890 129.570 399.720 129.640 ;
        RECT 405.110 129.590 406.630 130.500 ;
        RECT 455.330 130.190 458.010 130.690 ;
        RECT 464.480 130.680 465.370 130.690 ;
        RECT 402.170 129.580 406.630 129.590 ;
        RECT 400.250 129.570 406.630 129.580 ;
        RECT 390.890 129.410 406.630 129.570 ;
        RECT 397.320 129.130 406.630 129.410 ;
        RECT 399.470 129.040 406.630 129.130 ;
        RECT 400.250 129.020 402.550 129.040 ;
        RECT 403.090 128.030 404.000 129.040 ;
        RECT 405.110 128.710 406.630 129.040 ;
        RECT 407.640 128.030 415.650 128.050 ;
        RECT 403.090 127.920 415.650 128.030 ;
        RECT 368.260 127.820 376.710 127.840 ;
        RECT 379.270 127.820 381.770 127.900 ;
        RECT 368.260 127.570 381.820 127.820 ;
        RECT 366.790 127.400 381.820 127.570 ;
        RECT 366.790 127.340 368.750 127.400 ;
        RECT 369.080 127.340 371.040 127.400 ;
        RECT 371.370 127.340 373.330 127.400 ;
        RECT 373.660 127.340 375.620 127.400 ;
        RECT 379.290 127.300 381.820 127.400 ;
        RECT 403.090 127.470 432.650 127.920 ;
        RECT 403.090 127.430 416.520 127.470 ;
        RECT 351.730 125.560 353.600 126.160 ;
        RECT 351.730 125.320 352.510 125.560 ;
        RECT 353.370 124.195 353.600 125.560 ;
        RECT 342.200 123.950 355.610 123.990 ;
        RECT 342.200 123.760 355.720 123.950 ;
        RECT 342.410 123.730 355.720 123.760 ;
        RECT 343.100 123.230 355.720 123.730 ;
        RECT 343.100 122.970 352.790 123.230 ;
        RECT 343.060 122.500 352.790 122.970 ;
        RECT 354.910 122.830 355.720 123.230 ;
        RECT 343.060 122.240 352.560 122.500 ;
        RECT 343.060 122.190 343.790 122.240 ;
        RECT 347.130 122.130 352.560 122.240 ;
        RECT 347.130 122.050 347.920 122.130 ;
        RECT 351.770 122.080 352.560 122.130 ;
        RECT 355.040 122.260 355.720 122.830 ;
        RECT 355.040 121.310 355.760 122.260 ;
        RECT 355.060 120.880 355.760 121.310 ;
        RECT 368.800 121.250 369.030 127.180 ;
        RECT 369.260 121.250 370.290 121.450 ;
        RECT 355.060 120.840 355.750 120.880 ;
        RECT 351.620 120.610 353.090 120.640 ;
        RECT 355.010 120.610 355.750 120.840 ;
        RECT 343.860 120.510 355.750 120.610 ;
        RECT 339.830 120.470 355.750 120.510 ;
        RECT 368.800 120.620 370.290 121.250 ;
        RECT 373.380 121.330 373.610 127.180 ;
        RECT 379.290 127.050 381.770 127.300 ;
        RECT 379.270 125.770 381.770 127.050 ;
        RECT 403.090 126.560 403.990 127.430 ;
        RECT 408.260 127.400 416.520 127.430 ;
        RECT 416.850 127.400 418.810 127.470 ;
        RECT 419.140 127.400 421.100 127.470 ;
        RECT 421.430 127.400 423.390 127.470 ;
        RECT 423.720 127.400 425.680 127.470 ;
        RECT 426.010 127.400 427.970 127.470 ;
        RECT 428.300 127.400 430.260 127.470 ;
        RECT 430.590 127.400 432.550 127.470 ;
        RECT 403.090 126.010 404.000 126.560 ;
        RECT 390.890 125.710 404.000 126.010 ;
        RECT 390.890 125.300 403.980 125.710 ;
        RECT 390.890 125.280 399.720 125.300 ;
        RECT 390.890 125.260 392.850 125.280 ;
        RECT 393.180 125.260 395.140 125.280 ;
        RECT 395.470 125.260 397.430 125.280 ;
        RECT 397.760 125.260 399.720 125.280 ;
        RECT 392.900 124.620 393.130 125.100 ;
        RECT 393.480 124.620 394.440 124.630 ;
        RECT 392.900 123.780 394.440 124.620 ;
        RECT 397.480 124.500 397.710 125.100 ;
        RECT 397.480 124.460 398.820 124.500 ;
        RECT 392.900 123.730 394.210 123.780 ;
        RECT 374.090 121.330 375.120 121.540 ;
        RECT 373.380 120.800 375.120 121.330 ;
        RECT 368.800 120.580 369.940 120.620 ;
        RECT 358.530 120.470 360.850 120.480 ;
        RECT 339.830 119.650 360.850 120.470 ;
        RECT 368.800 120.040 369.030 120.580 ;
        RECT 373.380 120.040 373.610 120.800 ;
        RECT 374.090 120.710 375.120 120.800 ;
        RECT 366.790 119.650 368.750 119.880 ;
        RECT 369.080 119.650 371.040 119.880 ;
        RECT 371.370 119.650 373.330 119.880 ;
        RECT 373.660 119.650 375.620 119.880 ;
        RECT 339.830 119.570 346.550 119.650 ;
        RECT 339.860 117.940 340.680 119.570 ;
        RECT 343.860 119.550 346.550 119.570 ;
        RECT 347.000 119.600 360.850 119.650 ;
        RECT 347.000 119.570 357.500 119.600 ;
        RECT 347.000 119.550 355.590 119.570 ;
        RECT 347.000 119.450 348.470 119.550 ;
        RECT 351.620 119.480 353.090 119.550 ;
        RECT 342.200 118.210 344.160 118.440 ;
        RECT 344.490 118.210 346.450 118.440 ;
        RECT 346.780 118.210 348.740 118.440 ;
        RECT 349.070 118.210 351.030 118.440 ;
        RECT 351.360 118.210 353.320 118.440 ;
        RECT 353.650 118.210 355.610 118.440 ;
        RECT 341.920 117.940 342.150 118.005 ;
        RECT 339.860 116.870 342.150 117.940 ;
        RECT 339.920 116.840 342.150 116.870 ;
        RECT 341.920 101.335 342.150 116.840 ;
        RECT 344.210 103.120 344.440 118.005 ;
        RECT 346.500 117.090 346.730 118.005 ;
        RECT 347.170 117.090 348.370 117.350 ;
        RECT 346.500 116.120 348.370 117.090 ;
        RECT 344.200 102.160 345.440 103.120 ;
        RECT 344.210 101.335 344.440 102.160 ;
        RECT 346.500 101.335 346.730 116.120 ;
        RECT 347.170 116.100 348.370 116.120 ;
        RECT 348.790 103.070 349.020 118.005 ;
        RECT 351.080 117.230 351.310 118.005 ;
        RECT 351.960 117.340 352.640 117.350 ;
        RECT 351.680 117.230 352.730 117.340 ;
        RECT 351.080 116.380 352.730 117.230 ;
        RECT 348.790 102.110 350.070 103.070 ;
        RECT 348.790 101.335 349.020 102.110 ;
        RECT 351.080 101.335 351.310 116.380 ;
        RECT 351.680 116.320 352.730 116.380 ;
        RECT 353.370 102.950 353.600 118.005 ;
        RECT 355.660 117.810 355.890 118.005 ;
        RECT 356.980 117.810 357.500 119.570 ;
        RECT 355.660 116.940 357.500 117.810 ;
        RECT 355.660 116.910 357.340 116.940 ;
        RECT 353.370 101.990 354.660 102.950 ;
        RECT 353.370 101.335 353.600 101.990 ;
        RECT 355.660 101.335 355.890 116.910 ;
        RECT 360.020 115.110 360.820 119.600 ;
        RECT 392.900 117.960 393.130 123.730 ;
        RECT 397.480 123.610 399.130 124.460 ;
        RECT 397.480 117.960 397.710 123.610 ;
        RECT 390.890 117.570 392.850 117.800 ;
        RECT 393.180 117.570 395.140 117.800 ;
        RECT 395.470 117.570 397.430 117.800 ;
        RECT 397.760 117.570 399.720 117.800 ;
        RECT 359.620 112.820 362.130 115.110 ;
        RECT 403.250 111.350 403.940 125.300 ;
        RECT 397.600 111.300 403.940 111.350 ;
        RECT 397.420 110.810 403.940 111.300 ;
        RECT 391.950 109.300 395.690 110.350 ;
        RECT 397.420 110.210 403.950 110.810 ;
        RECT 397.420 109.300 403.980 110.210 ;
        RECT 391.950 108.220 403.980 109.300 ;
        RECT 391.950 107.690 395.690 108.220 ;
        RECT 397.410 107.980 403.980 108.220 ;
        RECT 397.410 105.610 403.820 107.980 ;
        RECT 397.420 105.530 403.820 105.610 ;
        RECT 397.420 105.510 400.410 105.530 ;
        RECT 403.300 105.510 403.820 105.530 ;
        RECT 390.890 104.020 394.850 104.250 ;
        RECT 395.180 104.020 399.140 104.250 ;
        RECT 394.900 103.390 395.130 103.815 ;
        RECT 395.760 103.390 396.900 103.410 ;
        RECT 394.880 102.760 396.900 103.390 ;
        RECT 394.900 102.720 396.900 102.760 ;
        RECT 347.070 101.130 347.900 101.140 ;
        RECT 342.200 101.070 344.160 101.130 ;
        RECT 344.490 101.070 346.450 101.130 ;
        RECT 346.780 101.070 348.740 101.130 ;
        RECT 349.070 101.070 351.030 101.130 ;
        RECT 351.360 101.070 353.320 101.130 ;
        RECT 353.650 101.070 355.610 101.130 ;
        RECT 342.200 100.900 355.610 101.070 ;
        RECT 347.070 99.860 347.900 100.900 ;
        RECT 380.000 100.060 383.100 101.230 ;
        RECT 394.900 100.415 395.130 102.720 ;
        RECT 395.760 102.390 396.900 102.720 ;
        RECT 409.980 101.140 411.940 101.370 ;
        RECT 412.270 101.140 414.230 101.370 ;
        RECT 414.560 101.140 416.520 101.370 ;
        RECT 416.850 101.140 418.810 101.370 ;
        RECT 419.140 101.140 421.100 101.370 ;
        RECT 421.430 101.140 423.390 101.370 ;
        RECT 423.720 101.140 425.680 101.370 ;
        RECT 426.010 101.140 427.970 101.370 ;
        RECT 428.300 101.140 430.260 101.370 ;
        RECT 430.590 101.140 432.550 101.370 ;
        RECT 347.060 99.510 347.940 99.860 ;
        RECT 347.050 98.760 347.970 99.510 ;
        RECT 379.940 99.430 383.100 100.060 ;
        RECT 390.750 100.210 394.190 100.230 ;
        RECT 396.910 100.210 399.120 100.230 ;
        RECT 390.750 100.190 394.850 100.210 ;
        RECT 395.180 100.190 399.140 100.210 ;
        RECT 390.750 99.980 399.140 100.190 ;
        RECT 390.750 99.640 399.120 99.980 ;
        RECT 379.940 98.650 382.140 99.430 ;
        RECT 394.570 98.720 395.750 99.640 ;
        RECT 376.650 98.420 384.900 98.650 ;
        RECT 379.940 97.930 382.140 98.420 ;
        RECT 380.070 96.870 381.870 97.930 ;
        RECT 380.660 78.215 380.890 96.870 ;
        RECT 393.600 93.640 396.480 95.140 ;
        RECT 394.250 92.830 395.840 93.640 ;
        RECT 392.330 92.660 395.840 92.830 ;
        RECT 392.330 92.655 396.400 92.660 ;
        RECT 390.895 92.425 399.145 92.655 ;
        RECT 394.250 92.420 395.950 92.425 ;
        RECT 394.250 92.400 394.470 92.420 ;
        RECT 394.905 91.550 395.135 92.265 ;
        RECT 394.850 91.540 395.950 91.550 ;
        RECT 396.980 91.540 398.170 91.550 ;
        RECT 394.850 89.830 398.170 91.540 ;
        RECT 394.905 82.265 395.135 89.830 ;
        RECT 390.895 81.875 394.855 82.105 ;
        RECT 395.185 81.875 399.145 82.105 ;
        RECT 376.650 77.780 380.610 78.010 ;
        RECT 380.940 77.780 384.900 78.010 ;
      LAYER via ;
        RECT 239.980 7.060 574.650 292 ;
        RECT 395.490 230.330 396.820 231.490 ;
        RECT 408.070 227.420 408.860 228.250 ;
        RECT 395.530 210.360 396.280 210.710 ;
        RECT 409.490 209.020 410.550 209.750 ;
        RECT 434.980 209.940 446.700 210.430 ;
        RECT 396.640 206.420 397.110 207.060 ;
        RECT 401.790 205.930 403.040 206.580 ;
        RECT 394.290 195.260 395.540 195.610 ;
        RECT 414.220 191.550 415.090 192.340 ;
        RECT 393.490 185.660 393.910 185.960 ;
        RECT 437.460 207.090 437.880 207.600 ;
        RECT 442.090 206.950 442.510 207.460 ;
        RECT 439.490 192.250 439.840 192.600 ;
        RECT 446.550 206.780 446.970 207.290 ;
        RECT 444.020 192.400 444.370 192.750 ;
        RECT 439.650 189.590 440.000 189.940 ;
        RECT 444.290 189.530 444.640 189.880 ;
        RECT 398.290 185.450 398.710 185.750 ;
        RECT 401.710 183.660 402.090 184.090 ;
        RECT 381.800 182.140 382.460 183.020 ;
        RECT 417.510 183.010 417.780 183.340 ;
        RECT 435.430 186.790 436.000 187.160 ;
        RECT 439.820 186.820 440.370 187.300 ;
        RECT 444.500 186.820 445.050 187.300 ;
        RECT 435.490 184.440 435.910 184.850 ;
        RECT 422.170 182.950 422.440 183.280 ;
        RECT 404.280 180.850 405.800 180.860 ;
        RECT 404.280 179.960 405.830 180.850 ;
        RECT 404.280 179.920 405.800 179.960 ;
        RECT 338.110 177.780 338.670 178.240 ;
        RECT 351.080 177.830 351.690 178.160 ;
        RECT 338.190 175.020 338.830 175.540 ;
        RECT 335.930 152.310 336.310 152.910 ;
        RECT 342.920 175.050 343.560 175.570 ;
        RECT 340.480 152.320 340.860 152.920 ;
        RECT 347.470 174.990 348.110 175.510 ;
        RECT 345.040 152.450 345.420 153.050 ;
        RECT 352.110 174.970 352.750 175.490 ;
        RECT 349.760 152.380 350.140 152.980 ;
        RECT 354.130 152.520 354.510 153.120 ;
        RECT 369.310 160.110 369.920 160.650 ;
        RECT 393.560 173.980 393.980 174.360 ;
        RECT 398.200 173.970 398.620 174.350 ;
        RECT 386.120 169.190 387.110 170.470 ;
        RECT 393.590 170.500 394.010 170.880 ;
        RECT 398.120 170.610 398.540 170.990 ;
        RECT 394.630 168.980 395.450 169.710 ;
        RECT 405.190 169.710 405.970 170.660 ;
        RECT 389.450 167.880 389.730 168.140 ;
        RECT 374.170 160.180 374.780 160.720 ;
        RECT 378.830 160.180 379.440 160.720 ;
        RECT 389.400 166.080 389.710 166.350 ;
        RECT 396.130 164.930 396.520 165.340 ;
        RECT 394.050 159.150 394.460 159.720 ;
        RECT 373.170 156.910 373.930 157.530 ;
        RECT 384.620 157.450 385.470 158.240 ;
        RECT 400.340 165.110 400.690 165.610 ;
        RECT 412.640 160.260 413.230 160.810 ;
        RECT 405.000 159.350 405.490 159.930 ;
        RECT 417.430 160.440 418.020 160.990 ;
        RECT 422.170 160.380 422.760 160.930 ;
        RECT 397.210 157.180 397.910 157.740 ;
        RECT 405.010 154.820 405.950 155.590 ;
        RECT 393.890 153.310 394.510 153.670 ;
        RECT 369.380 149.010 369.760 149.450 ;
        RECT 336.320 144.540 338.330 145.530 ;
        RECT 328.190 132.090 329.430 134.370 ;
        RECT 343.140 125.370 343.590 125.870 ;
        RECT 347.230 125.350 347.630 125.780 ;
        RECT 374.230 148.730 374.610 149.170 ;
        RECT 378.970 148.640 379.350 149.080 ;
        RECT 389.260 148.630 389.790 149.360 ;
        RECT 397.700 151.640 398.240 152.080 ;
        RECT 408.300 152.910 409.310 153.710 ;
        RECT 416.400 151.670 417.430 152.350 ;
        RECT 396.300 148.770 396.800 149.300 ;
        RECT 401.870 149.470 402.220 149.800 ;
        RECT 407.620 149.670 408.450 150.410 ;
        RECT 412.410 149.000 412.820 149.310 ;
        RECT 439.860 184.030 440.340 184.560 ;
        RECT 444.700 184.030 445.180 184.560 ;
        RECT 435.750 160.100 436.600 160.570 ;
        RECT 455.020 160.640 455.760 161.500 ;
        RECT 416.980 148.980 417.390 149.290 ;
        RECT 392.020 140.590 392.500 141.020 ;
        RECT 394.780 140.870 395.450 140.920 ;
        RECT 394.750 140.300 395.450 140.870 ;
        RECT 398.400 140.640 398.880 141.070 ;
        RECT 394.750 140.210 395.390 140.300 ;
        RECT 392.070 139.280 392.600 139.760 ;
        RECT 398.250 139.340 398.890 139.760 ;
        RECT 393.640 138.110 394.020 138.420 ;
        RECT 398.250 138.180 398.630 138.490 ;
        RECT 393.640 135.620 394.020 135.930 ;
        RECT 383.670 132.270 384.460 132.930 ;
        RECT 398.210 135.610 398.590 135.920 ;
        RECT 421.640 149.000 422.050 149.310 ;
        RECT 405.460 132.010 406.790 133.040 ;
        RECT 439.870 157.440 440.300 157.820 ;
        RECT 437.370 134.420 437.860 134.970 ;
        RECT 444.650 157.440 445.080 157.820 ;
        RECT 441.900 134.820 442.390 135.370 ;
        RECT 446.700 134.850 447.190 135.400 ;
        RECT 449.170 157.440 449.600 157.820 ;
        RECT 453.540 157.500 453.970 157.880 ;
        RECT 451.250 135.000 451.740 135.550 ;
        RECT 455.950 135.090 456.440 135.640 ;
        RECT 428.320 131.100 429.590 132.000 ;
        RECT 456.110 130.690 457.260 131.440 ;
        RECT 405.310 128.980 406.520 130.200 ;
        RECT 351.890 125.580 352.290 126.010 ;
        RECT 343.250 122.330 343.620 122.760 ;
        RECT 347.350 122.270 347.750 122.700 ;
        RECT 351.970 122.330 352.370 122.760 ;
        RECT 369.500 120.890 370.090 121.190 ;
        RECT 347.240 119.750 348.030 120.440 ;
        RECT 351.910 119.860 352.700 120.550 ;
        RECT 379.770 126.240 381.130 127.490 ;
        RECT 403.310 126.560 403.900 127.000 ;
        RECT 393.740 123.930 394.140 124.380 ;
        RECT 398.460 123.750 398.860 124.200 ;
        RECT 374.420 120.990 375.010 121.290 ;
        RECT 347.380 116.430 348.110 117.030 ;
        RECT 344.750 102.370 345.240 102.950 ;
        RECT 351.830 116.580 352.610 117.070 ;
        RECT 349.530 102.390 350.020 102.970 ;
        RECT 354.030 102.240 354.520 102.820 ;
        RECT 360.080 113.590 361.610 114.380 ;
        RECT 392.760 108.220 395.080 109.830 ;
        RECT 397.600 105.760 398.250 106.360 ;
        RECT 380.640 99.880 382.410 100.810 ;
        RECT 395.940 102.700 396.750 103.200 ;
        RECT 347.240 98.880 347.800 99.350 ;
        RECT 394.860 98.930 395.510 99.810 ;
        RECT 394.340 93.990 395.830 94.830 ;
        RECT 396.420 90.200 397.690 91.360 ;
      LAYER met2 ;
        RECT 239.980 7.060 574.650 292 ;
        RECT 395.090 231.120 397.400 231.860 ;
        RECT 385.450 231.060 397.400 231.120 ;
        RECT 385.310 230.990 397.400 231.060 ;
        RECT 385.310 230.230 402.660 230.990 ;
        RECT 385.310 230.170 397.400 230.230 ;
        RECT 379.370 220.440 381.630 220.470 ;
        RECT 385.310 220.440 386.540 230.170 ;
        RECT 395.090 229.840 397.400 230.170 ;
        RECT 401.800 228.270 402.660 230.230 ;
        RECT 407.800 228.270 409.200 228.490 ;
        RECT 401.800 227.430 409.200 228.270 ;
        RECT 401.800 227.420 403.140 227.430 ;
        RECT 379.370 219.070 386.540 220.440 ;
        RECT 347.150 215.830 348.440 215.860 ;
        RECT 347.150 215.590 354.490 215.830 ;
        RECT 379.370 215.590 381.630 219.070 ;
        RECT 347.150 214.640 381.630 215.590 ;
        RECT 273.320 191.330 286.520 191.600 ;
        RECT 347.150 191.330 348.440 214.640 ;
        RECT 352.170 214.400 381.630 214.640 ;
        RECT 401.810 213.600 403.140 227.420 ;
        RECT 407.800 227.130 409.200 227.430 ;
        RECT 401.810 213.380 403.200 213.600 ;
        RECT 351.020 211.310 383.150 212.390 ;
        RECT 351.040 209.720 351.850 211.310 ;
        RECT 351.040 209.460 351.880 209.720 ;
        RECT 273.320 189.750 348.560 191.330 ;
        RECT 273.320 189.470 286.520 189.750 ;
        RECT 347.150 189.680 348.440 189.750 ;
        RECT 273.320 122.200 274.830 189.470 ;
        RECT 337.900 178.190 339.110 178.580 ;
        RECT 351.060 178.190 351.880 209.460 ;
        RECT 382.030 197.240 383.150 211.310 ;
        RECT 395.680 212.270 403.200 213.380 ;
        RECT 395.680 210.940 396.290 212.270 ;
        RECT 395.370 210.190 396.510 210.940 ;
        RECT 402.540 209.760 403.200 212.270 ;
        RECT 422.250 212.390 454.250 213.600 ;
        RECT 422.250 212.360 449.380 212.390 ;
        RECT 422.250 211.840 424.070 212.360 ;
        RECT 452.950 212.250 454.250 212.390 ;
        RECT 408.930 209.760 411.070 210.010 ;
        RECT 402.540 209.260 411.070 209.760 ;
        RECT 408.930 208.650 411.070 209.260 ;
        RECT 396.400 206.720 397.610 207.590 ;
        RECT 401.460 206.720 403.700 207.030 ;
        RECT 396.400 206.280 403.700 206.720 ;
        RECT 396.400 206.170 397.610 206.280 ;
        RECT 401.460 205.430 403.700 206.280 ;
        RECT 422.310 197.880 424.070 211.840 ;
        RECT 452.980 211.620 454.250 212.250 ;
        RECT 426.560 210.740 434.150 210.750 ;
        RECT 426.560 209.650 447.980 210.740 ;
        RECT 426.560 209.610 434.150 209.650 ;
        RECT 426.560 208.060 427.490 209.610 ;
        RECT 422.320 197.250 424.070 197.880 ;
        RECT 411.880 197.240 424.070 197.250 ;
        RECT 381.990 196.200 424.070 197.240 ;
        RECT 426.500 207.310 427.490 208.060 ;
        RECT 437.540 207.700 437.920 209.650 ;
        RECT 381.990 196.180 411.690 196.200 ;
        RECT 393.660 195.440 396.570 195.810 ;
        RECT 402.630 195.440 403.460 195.530 ;
        RECT 393.660 195.130 403.460 195.440 ;
        RECT 393.660 195.040 396.570 195.130 ;
        RECT 393.870 195.020 394.340 195.040 ;
        RECT 402.630 192.470 403.460 195.130 ;
        RECT 401.620 192.460 403.460 192.470 ;
        RECT 413.900 192.460 415.500 192.680 ;
        RECT 401.620 191.760 415.500 192.460 ;
        RECT 401.620 191.740 403.460 191.760 ;
        RECT 393.370 185.490 394.150 186.160 ;
        RECT 393.470 183.470 393.910 185.490 ;
        RECT 398.110 185.140 398.860 186.080 ;
        RECT 381.530 183.230 382.790 183.360 ;
        RECT 381.530 183.200 386.590 183.230 ;
        RECT 393.310 183.200 393.910 183.470 ;
        RECT 381.530 183.170 393.910 183.200 ;
        RECT 398.270 183.170 398.730 185.140 ;
        RECT 401.640 184.410 402.280 191.740 ;
        RECT 413.900 191.290 415.500 191.760 ;
        RECT 426.500 190.150 427.410 207.310 ;
        RECT 437.170 206.880 438.130 207.700 ;
        RECT 442.220 207.620 442.600 209.650 ;
        RECT 441.860 206.800 442.820 207.620 ;
        RECT 446.600 207.450 446.980 209.650 ;
        RECT 446.350 206.630 447.310 207.450 ;
        RECT 439.350 192.120 440.080 192.770 ;
        RECT 443.870 192.270 444.600 192.920 ;
        RECT 426.500 190.130 427.440 190.150 ;
        RECT 426.500 189.190 427.450 190.130 ;
        RECT 439.610 190.030 440.060 192.120 ;
        RECT 444.070 190.090 444.520 192.270 ;
        RECT 439.440 189.380 440.170 190.030 ;
        RECT 444.040 189.440 444.770 190.090 ;
        RECT 381.530 183.150 398.730 183.170 ;
        RECT 401.350 183.480 402.370 184.410 ;
        RECT 401.350 183.150 402.010 183.480 ;
        RECT 381.530 183.120 402.010 183.150 ;
        RECT 381.530 182.490 402.060 183.120 ;
        RECT 417.380 182.860 417.970 183.520 ;
        RECT 381.530 182.450 386.590 182.490 ;
        RECT 381.530 181.750 382.790 182.450 ;
        RECT 403.590 179.490 406.320 181.190 ;
        RECT 417.490 179.910 417.820 182.860 ;
        RECT 422.050 182.790 422.640 183.450 ;
        RECT 422.180 180.080 422.470 182.790 ;
        RECT 422.190 179.910 422.470 180.080 ;
        RECT 426.500 179.950 427.440 189.190 ;
        RECT 435.220 186.560 436.250 187.390 ;
        RECT 439.590 186.640 440.680 187.590 ;
        RECT 444.200 186.650 445.290 187.600 ;
        RECT 435.440 184.990 435.940 186.560 ;
        RECT 435.350 184.250 436.070 184.990 ;
        RECT 439.810 184.820 440.430 186.640 ;
        RECT 444.460 184.830 445.080 186.650 ;
        RECT 439.630 183.860 440.530 184.820 ;
        RECT 444.430 183.870 445.310 184.830 ;
        RECT 424.640 179.910 427.480 179.950 ;
        RECT 417.490 179.610 417.890 179.910 ;
        RECT 422.190 179.610 427.480 179.910 ;
        RECT 417.490 179.570 427.480 179.610 ;
        RECT 417.500 179.180 427.480 179.570 ;
        RECT 426.860 178.850 427.480 179.180 ;
        RECT 426.840 178.590 427.480 178.850 ;
        RECT 337.900 177.720 352.740 178.190 ;
        RECT 337.900 177.590 339.110 177.720 ;
        RECT 338.270 175.820 338.780 177.590 ;
        RECT 342.960 175.860 343.470 177.720 ;
        RECT 338.010 174.830 339.040 175.820 ;
        RECT 342.660 174.870 343.690 175.860 ;
        RECT 347.410 175.850 347.920 177.720 ;
        RECT 347.240 174.860 348.270 175.850 ;
        RECT 352.230 175.690 352.740 177.720 ;
        RECT 351.880 174.700 352.910 175.690 ;
        RECT 393.380 173.750 394.170 174.590 ;
        RECT 397.910 173.760 398.700 174.600 ;
        RECT 385.510 170.820 387.600 171.260 ;
        RECT 393.390 171.190 394.130 173.750 ;
        RECT 385.510 170.120 387.580 170.820 ;
        RECT 393.390 170.540 394.190 171.190 ;
        RECT 397.990 171.070 398.700 173.760 ;
        RECT 393.410 170.360 394.190 170.540 ;
        RECT 397.810 170.450 398.840 171.070 ;
        RECT 404.940 170.930 406.290 170.940 ;
        RECT 393.420 170.350 394.190 170.360 ;
        RECT 381.900 170.100 387.580 170.120 ;
        RECT 381.870 169.850 387.580 170.100 ;
        RECT 381.870 169.450 387.590 169.850 ;
        RECT 381.870 168.760 387.600 169.450 ;
        RECT 394.370 168.830 395.650 170.020 ;
        RECT 404.940 169.980 408.040 170.930 ;
        RECT 404.940 169.310 406.290 169.980 ;
        RECT 406.760 169.970 408.040 169.980 ;
        RECT 381.870 168.730 387.310 168.760 ;
        RECT 369.160 157.700 370.140 160.750 ;
        RECT 373.940 157.700 374.920 160.780 ;
        RECT 378.680 157.700 379.660 160.780 ;
        RECT 381.870 157.700 382.780 168.730 ;
        RECT 389.410 167.920 389.840 168.200 ;
        RECT 389.400 167.780 389.840 167.920 ;
        RECT 389.400 166.370 389.650 167.780 ;
        RECT 389.360 166.020 389.790 166.370 ;
        RECT 400.190 165.500 400.740 165.780 ;
        RECT 396.140 165.490 400.740 165.500 ;
        RECT 395.990 165.480 400.740 165.490 ;
        RECT 395.980 164.920 400.740 165.480 ;
        RECT 395.980 164.830 400.630 164.920 ;
        RECT 393.820 159.000 394.620 159.810 ;
        RECT 395.980 159.390 396.590 164.830 ;
        RECT 404.900 160.060 405.610 160.070 ;
        RECT 404.900 159.910 405.780 160.060 ;
        RECT 369.110 156.770 382.780 157.700 ;
        RECT 384.560 157.840 385.620 158.530 ;
        RECT 394.030 157.840 394.610 159.000 ;
        RECT 384.560 157.300 394.610 157.840 ;
        RECT 369.160 156.760 370.140 156.770 ;
        RECT 394.030 155.770 394.610 157.300 ;
        RECT 394.030 153.870 394.620 155.770 ;
        RECT 395.980 154.860 396.580 159.390 ;
        RECT 404.900 159.250 405.790 159.910 ;
        RECT 397.010 156.990 398.090 157.920 ;
        RECT 335.700 152.120 336.520 153.130 ;
        RECT 340.240 152.140 341.060 153.150 ;
        RECT 344.810 152.270 345.630 153.280 ;
        RECT 335.930 148.060 336.370 152.120 ;
        RECT 340.340 148.060 340.780 152.140 ;
        RECT 345.010 148.060 345.450 152.270 ;
        RECT 349.580 152.250 350.400 153.260 ;
        RECT 353.970 152.410 354.790 153.420 ;
        RECT 393.730 153.140 394.740 153.870 ;
        RECT 349.750 148.060 350.190 152.250 ;
        RECT 354.220 148.060 354.660 152.410 ;
        RECT 370.000 152.390 381.920 152.420 ;
        RECT 370.000 152.380 387.130 152.390 ;
        RECT 363.620 152.340 387.130 152.380 ;
        RECT 395.970 152.340 396.590 154.860 ;
        RECT 363.620 151.730 396.590 152.340 ;
        RECT 363.620 151.700 364.730 151.730 ;
        RECT 363.620 150.140 364.540 151.700 ;
        RECT 369.410 151.650 396.590 151.730 ;
        RECT 363.620 149.570 364.500 150.140 ;
        RECT 369.420 149.630 369.980 151.650 ;
        RECT 363.290 148.770 364.500 149.570 ;
        RECT 369.280 149.010 369.980 149.630 ;
        RECT 374.220 149.320 374.780 151.650 ;
        RECT 369.280 148.940 369.960 149.010 ;
        RECT 328.130 148.040 354.660 148.060 ;
        RECT 327.890 147.760 354.660 148.040 ;
        RECT 363.270 147.760 364.500 148.770 ;
        RECT 374.070 148.690 374.780 149.320 ;
        RECT 378.900 149.230 379.460 151.650 ;
        RECT 380.810 151.620 396.590 151.650 ;
        RECT 395.940 151.350 396.590 151.620 ;
        RECT 397.550 152.380 398.090 156.990 ;
        RECT 404.980 156.540 405.790 159.250 ;
        RECT 404.960 156.230 405.790 156.540 ;
        RECT 407.170 157.520 408.040 169.970 ;
        RECT 412.500 160.050 413.400 160.980 ;
        RECT 417.280 160.230 418.180 161.160 ;
        RECT 412.630 157.520 413.190 160.050 ;
        RECT 417.390 157.520 417.950 160.230 ;
        RECT 421.950 160.170 422.850 161.100 ;
        RECT 426.790 160.610 427.480 178.590 ;
        RECT 452.980 170.620 454.270 211.620 ;
        RECT 454.910 170.620 456.380 170.740 ;
        RECT 452.980 169.210 456.380 170.620 ;
        RECT 453.150 169.150 456.380 169.210 ;
        RECT 454.910 163.420 456.380 169.150 ;
        RECT 458.860 163.420 460.090 163.450 ;
        RECT 454.910 162.180 460.090 163.420 ;
        RECT 454.910 161.740 456.380 162.180 ;
        RECT 454.720 161.570 456.390 161.740 ;
        RECT 439.980 161.410 456.390 161.570 ;
        RECT 439.920 161.120 456.390 161.410 ;
        RECT 435.380 160.610 436.700 160.770 ;
        RECT 422.220 157.530 422.780 160.170 ;
        RECT 426.790 160.060 436.700 160.610 ;
        RECT 421.920 157.520 423.900 157.530 ;
        RECT 407.170 156.530 423.900 157.520 ;
        RECT 407.170 156.470 408.040 156.530 ;
        RECT 416.240 156.470 417.300 156.530 ;
        RECT 404.960 155.770 405.780 156.230 ;
        RECT 421.920 155.940 423.900 156.530 ;
        RECT 404.800 154.630 406.080 155.770 ;
        RECT 407.770 153.760 409.620 154.320 ;
        RECT 426.790 153.760 427.480 160.060 ;
        RECT 435.380 159.780 436.700 160.060 ;
        RECT 439.920 158.100 440.270 161.120 ;
        RECT 444.770 158.100 445.120 161.120 ;
        RECT 449.220 158.120 449.570 161.120 ;
        RECT 453.560 158.120 453.910 161.120 ;
        RECT 454.720 160.250 456.390 161.120 ;
        RECT 458.860 161.680 460.090 162.180 ;
        RECT 439.720 157.240 440.610 158.100 ;
        RECT 444.390 157.240 445.280 158.100 ;
        RECT 449.010 157.260 449.900 158.120 ;
        RECT 453.340 157.260 454.230 158.120 ;
        RECT 407.770 152.910 427.480 153.760 ;
        RECT 407.770 152.580 409.620 152.910 ;
        RECT 397.550 151.930 398.460 152.380 ;
        RECT 397.550 151.890 399.100 151.930 ;
        RECT 416.310 151.890 417.940 152.590 ;
        RECT 397.550 151.470 422.310 151.890 ;
        RECT 426.100 151.730 428.060 152.080 ;
        RECT 426.100 151.500 428.810 151.730 ;
        RECT 397.550 151.450 407.750 151.470 ;
        RECT 398.980 151.440 407.750 151.450 ;
        RECT 398.980 151.430 402.120 151.440 ;
        RECT 395.970 149.650 396.590 151.350 ;
        RECT 401.810 149.880 402.100 151.430 ;
        RECT 374.070 148.630 374.750 148.690 ;
        RECT 378.780 148.540 379.460 149.230 ;
        RECT 389.090 149.450 390.100 149.510 ;
        RECT 395.390 149.450 395.580 149.460 ;
        RECT 395.820 149.450 397.080 149.650 ;
        RECT 389.090 149.410 392.680 149.450 ;
        RECT 393.820 149.410 397.080 149.450 ;
        RECT 389.090 148.920 397.080 149.410 ;
        RECT 401.690 149.380 402.240 149.880 ;
        RECT 407.190 149.450 408.560 150.610 ;
        RECT 412.450 149.500 413.000 151.470 ;
        RECT 417.120 151.460 417.690 151.470 ;
        RECT 389.090 148.910 392.680 148.920 ;
        RECT 393.820 148.910 397.080 148.920 ;
        RECT 389.090 148.470 390.100 148.910 ;
        RECT 395.170 148.900 395.630 148.910 ;
        RECT 395.820 148.360 397.080 148.910 ;
        RECT 327.890 147.030 364.500 147.760 ;
        RECT 327.890 135.140 329.950 147.030 ;
        RECT 335.410 144.120 338.960 145.980 ;
        RECT 327.890 131.750 330.410 135.140 ;
        RECT 327.890 131.650 329.950 131.750 ;
        RECT 324.490 122.200 327.790 122.270 ;
        RECT 273.320 120.690 327.790 122.200 ;
        RECT 324.490 94.610 327.790 120.690 ;
        RECT 335.940 101.730 337.440 144.120 ;
        RECT 395.800 141.570 396.170 141.620 ;
        RECT 391.820 140.990 392.680 141.220 ;
        RECT 394.430 140.990 396.170 141.570 ;
        RECT 391.820 140.980 397.510 140.990 ;
        RECT 398.190 140.980 399.050 141.300 ;
        RECT 391.820 140.600 399.050 140.980 ;
        RECT 391.820 140.430 392.680 140.600 ;
        RECT 394.430 140.590 399.050 140.600 ;
        RECT 394.430 140.580 397.510 140.590 ;
        RECT 391.850 139.670 392.710 140.020 ;
        RECT 394.430 140.010 396.170 140.580 ;
        RECT 398.190 140.510 399.050 140.590 ;
        RECT 398.110 139.700 399.060 139.940 ;
        RECT 397.700 139.670 399.060 139.700 ;
        RECT 391.850 139.270 399.060 139.670 ;
        RECT 391.850 139.260 398.120 139.270 ;
        RECT 391.850 139.150 392.720 139.260 ;
        RECT 391.850 139.140 392.710 139.150 ;
        RECT 393.460 137.970 394.200 138.590 ;
        RECT 398.030 138.000 398.790 138.620 ;
        RECT 407.390 138.390 408.150 149.450 ;
        RECT 412.050 148.870 413.160 149.500 ;
        RECT 417.140 149.430 417.690 151.460 ;
        RECT 421.730 149.460 422.280 151.470 ;
        RECT 426.100 151.380 431.980 151.500 ;
        RECT 426.100 150.540 432.310 151.380 ;
        RECT 426.100 150.390 430.410 150.540 ;
        RECT 426.100 150.180 428.550 150.390 ;
        RECT 426.100 150.120 428.060 150.180 ;
        RECT 416.640 148.800 417.750 149.430 ;
        RECT 421.210 148.830 422.320 149.460 ;
        RECT 401.940 138.290 408.150 138.390 ;
        RECT 393.680 136.270 394.000 137.970 ;
        RECT 393.470 135.360 394.200 136.270 ;
        RECT 398.290 136.240 398.610 138.000 ;
        RECT 401.640 137.480 408.150 138.290 ;
        RECT 401.640 137.350 408.100 137.480 ;
        RECT 401.640 136.950 402.980 137.350 ;
        RECT 398.120 135.330 398.850 136.240 ;
        RECT 383.510 132.020 384.640 133.100 ;
        RECT 405.270 131.950 407.020 133.450 ;
        RECT 431.080 132.840 432.310 150.540 ;
        RECT 458.860 137.590 460.100 161.680 ;
        RECT 437.180 134.230 438.120 135.350 ;
        RECT 441.700 134.590 442.640 135.710 ;
        RECT 446.420 134.590 447.360 135.710 ;
        RECT 450.960 134.730 451.900 135.850 ;
        RECT 455.590 134.890 456.530 136.010 ;
        RECT 431.080 132.780 432.460 132.840 ;
        RECT 427.720 131.640 430.190 132.550 ;
        RECT 427.740 131.080 430.190 131.640 ;
        RECT 427.720 130.660 430.190 131.080 ;
        RECT 427.800 130.560 430.190 130.660 ;
        RECT 430.960 131.330 432.460 132.780 ;
        RECT 437.310 131.330 437.770 134.230 ;
        RECT 441.780 131.370 442.240 134.590 ;
        RECT 446.640 131.370 447.100 134.590 ;
        RECT 450.960 131.370 451.690 134.730 ;
        RECT 455.630 131.900 456.360 134.890 ;
        RECT 458.250 133.400 461.320 137.590 ;
        RECT 455.630 131.730 456.340 131.900 ;
        RECT 455.330 131.370 458.010 131.730 ;
        RECT 441.780 131.330 458.010 131.370 ;
        RECT 405.110 128.710 406.630 130.500 ;
        RECT 427.800 130.350 429.040 130.560 ;
        RECT 430.960 130.500 458.010 131.330 ;
        RECT 430.960 130.490 442.920 130.500 ;
        RECT 430.960 130.430 432.460 130.490 ;
        RECT 431.200 130.370 432.460 130.430 ;
        RECT 427.800 129.910 428.910 130.350 ;
        RECT 455.330 130.190 458.010 130.500 ;
        RECT 407.240 129.860 407.770 129.910 ;
        RECT 427.770 129.860 428.910 129.910 ;
        RECT 407.240 129.330 428.910 129.860 ;
        RECT 379.270 127.400 381.770 127.900 ;
        RECT 407.240 127.490 407.770 129.330 ;
        RECT 379.290 127.050 381.770 127.400 ;
        RECT 343.010 125.240 343.680 126.030 ;
        RECT 347.080 125.250 347.830 126.130 ;
        RECT 351.730 125.320 352.510 126.200 ;
        RECT 379.270 125.770 381.770 127.050 ;
        RECT 393.780 127.010 397.800 127.080 ;
        RECT 403.130 127.030 403.990 127.260 ;
        RECT 398.410 127.010 403.990 127.030 ;
        RECT 393.780 126.560 403.990 127.010 ;
        RECT 393.780 126.450 404.010 126.560 ;
        RECT 393.780 126.440 399.040 126.450 ;
        RECT 384.710 125.760 385.850 125.810 ;
        RECT 343.130 122.970 343.490 125.240 ;
        RECT 343.060 122.190 343.790 122.970 ;
        RECT 347.360 122.930 347.680 125.250 ;
        RECT 351.980 122.960 352.300 125.320 ;
        RECT 384.620 123.920 386.590 125.760 ;
        RECT 393.810 124.630 394.360 126.440 ;
        RECT 347.130 122.050 347.920 122.930 ;
        RECT 351.770 122.080 352.560 122.960 ;
        RECT 347.000 119.450 348.470 120.610 ;
        RECT 351.620 119.480 353.090 120.640 ;
        RECT 369.260 120.620 370.290 121.450 ;
        RECT 374.090 120.710 375.120 121.540 ;
        RECT 347.380 117.350 348.050 119.450 ;
        RECT 347.170 116.100 348.370 117.350 ;
        RECT 351.970 117.340 352.680 119.480 ;
        RECT 358.190 117.480 358.570 117.520 ;
        RECT 358.160 117.440 361.410 117.480 ;
        RECT 369.570 117.450 370.040 120.620 ;
        RECT 374.520 117.480 374.850 120.710 ;
        RECT 385.020 117.530 386.260 123.920 ;
        RECT 393.480 123.780 394.440 124.630 ;
        RECT 398.490 124.460 399.040 126.440 ;
        RECT 403.130 126.300 404.010 126.450 ;
        RECT 398.170 123.610 399.130 124.460 ;
        RECT 383.230 117.480 386.260 117.530 ;
        RECT 374.260 117.450 386.260 117.480 ;
        RECT 369.570 117.440 386.260 117.450 ;
        RECT 351.680 116.320 352.730 117.340 ;
        RECT 358.160 116.990 386.260 117.440 ;
        RECT 344.620 102.260 345.370 103.030 ;
        RECT 336.020 99.440 337.440 101.730 ;
        RECT 344.760 99.520 345.340 102.260 ;
        RECT 349.300 102.240 350.050 103.010 ;
        RECT 346.980 99.520 347.920 99.540 ;
        RECT 349.310 99.520 349.890 102.240 ;
        RECT 353.860 102.140 354.610 102.910 ;
        RECT 358.190 102.570 358.570 116.990 ;
        RECT 360.730 116.980 386.260 116.990 ;
        RECT 369.570 116.950 386.260 116.980 ;
        RECT 369.570 116.900 386.060 116.950 ;
        RECT 359.620 114.010 362.130 115.110 ;
        RECT 407.160 114.070 407.770 127.490 ;
        RECT 365.280 114.010 407.770 114.070 ;
        RECT 359.620 113.000 407.770 114.010 ;
        RECT 359.620 112.910 406.300 113.000 ;
        RECT 359.620 112.820 366.680 112.910 ;
        RECT 391.950 107.690 395.690 110.350 ;
        RECT 397.410 106.090 398.510 106.750 ;
        RECT 396.140 106.000 398.510 106.090 ;
        RECT 396.070 105.610 398.510 106.000 ;
        RECT 396.070 105.570 398.500 105.610 ;
        RECT 396.070 103.410 396.620 105.570 ;
        RECT 353.940 99.520 354.520 102.140 ;
        RECT 358.180 100.540 358.590 102.570 ;
        RECT 395.760 102.390 396.900 103.410 ;
        RECT 380.000 101.140 383.100 101.230 ;
        RECT 379.990 101.010 383.100 101.140 ;
        RECT 358.150 99.770 358.590 100.540 ;
        RECT 371.680 100.750 383.100 101.010 ;
        RECT 371.680 99.940 388.910 100.750 ;
        RECT 358.150 99.530 358.550 99.770 ;
        RECT 355.720 99.520 358.610 99.530 ;
        RECT 340.570 99.440 358.610 99.520 ;
        RECT 336.020 98.710 358.610 99.440 ;
        RECT 356.580 98.690 358.610 98.710 ;
        RECT 371.680 94.610 372.860 99.940 ;
        RECT 373.860 99.930 388.910 99.940 ;
        RECT 373.860 99.920 387.480 99.930 ;
        RECT 373.860 99.900 383.100 99.920 ;
        RECT 380.000 99.430 383.100 99.900 ;
        RECT 388.070 97.870 388.910 99.930 ;
        RECT 394.570 98.720 395.750 99.940 ;
        RECT 388.100 97.050 388.910 97.870 ;
        RECT 394.900 97.050 395.420 98.720 ;
        RECT 388.100 96.360 395.480 97.050 ;
        RECT 388.100 96.290 388.910 96.360 ;
        RECT 394.900 95.140 395.420 96.360 ;
        RECT 324.490 92.650 372.860 94.610 ;
        RECT 393.600 94.290 396.480 95.140 ;
        RECT 396.820 94.290 397.700 94.310 ;
        RECT 393.600 93.680 397.700 94.290 ;
        RECT 393.600 93.640 396.480 93.680 ;
        RECT 324.490 92.630 372.840 92.650 ;
        RECT 396.820 91.550 397.700 93.680 ;
        RECT 396.820 91.540 398.170 91.550 ;
        RECT 395.970 89.830 398.170 91.540 ;
      LAYER via2 ;
        RECT 239.980 7.060 574.650 292 ;
        RECT 404.280 180.850 405.800 180.860 ;
        RECT 404.280 179.960 405.830 180.850 ;
        RECT 404.280 179.920 405.800 179.960 ;
        RECT 394.630 168.980 395.450 169.710 ;
        RECT 422.150 156.370 423.610 157.110 ;
        RECT 394.770 140.870 395.530 140.990 ;
        RECT 394.750 140.220 395.530 140.870 ;
        RECT 394.750 140.210 395.390 140.220 ;
        RECT 426.440 150.570 427.630 151.710 ;
        RECT 401.940 137.300 402.620 138.060 ;
        RECT 458.530 133.730 460.980 136.580 ;
        RECT 405.340 128.910 406.460 130.110 ;
        RECT 379.770 126.240 381.130 127.490 ;
        RECT 385.170 124.470 386.210 125.510 ;
        RECT 392.760 108.220 395.080 109.830 ;
      LAYER met3 ;
        RECT 239.980 7.060 574.650 292 ;
        RECT 403.780 181.190 406.460 181.300 ;
        RECT 403.590 179.490 406.650 181.190 ;
        RECT 405.600 179.230 406.650 179.490 ;
        RECT 405.600 173.920 406.640 179.230 ;
        RECT 394.370 168.830 395.650 170.020 ;
        RECT 394.790 143.780 395.420 168.830 ;
        RECT 405.650 156.770 406.640 173.920 ;
        RECT 405.620 154.050 406.640 156.770 ;
        RECT 421.920 157.080 423.900 157.530 ;
        RECT 421.920 156.370 427.130 157.080 ;
        RECT 421.920 155.940 423.900 156.370 ;
        RECT 394.800 141.620 395.400 143.780 ;
        RECT 394.430 140.010 396.170 141.620 ;
        RECT 401.640 138.160 402.980 138.290 ;
        RECT 401.540 136.950 402.980 138.160 ;
        RECT 379.270 127.400 381.770 127.900 ;
        RECT 401.540 127.630 402.950 136.950 ;
        RECT 405.650 134.010 406.640 154.050 ;
        RECT 426.230 152.210 427.130 156.370 ;
        RECT 426.230 152.080 427.580 152.210 ;
        RECT 426.100 150.120 428.060 152.080 ;
        RECT 405.640 131.280 406.640 134.010 ;
        RECT 458.250 133.440 461.320 137.590 ;
        RECT 458.250 133.400 458.590 133.440 ;
        RECT 405.650 130.840 406.640 131.280 ;
        RECT 405.650 130.500 406.630 130.840 ;
        RECT 405.110 128.710 406.630 130.500 ;
        RECT 388.030 127.600 402.950 127.630 ;
        RECT 379.290 127.050 381.770 127.400 ;
        RECT 379.270 125.770 381.770 127.050 ;
        RECT 387.880 126.640 402.950 127.600 ;
        RECT 387.880 126.620 402.520 126.640 ;
        RECT 379.880 109.630 381.020 125.770 ;
        RECT 384.620 125.510 386.590 125.760 ;
        RECT 387.880 125.510 389.040 126.620 ;
        RECT 384.620 124.370 389.040 125.510 ;
        RECT 384.620 123.920 386.590 124.370 ;
        RECT 387.880 124.350 389.040 124.370 ;
        RECT 391.950 109.630 395.690 110.350 ;
        RECT 379.830 107.780 395.690 109.630 ;
        RECT 379.880 107.750 381.020 107.780 ;
        RECT 391.950 107.690 395.690 107.780 ;
        RECT 439.250 98.250 471.110 125.650 ;
        RECT 473.300 98.160 505.160 125.560 ;
        RECT 439.270 69.500 471.130 96.900 ;
        RECT 473.340 69.380 505.200 96.780 ;
      LAYER via3 ;
        RECT 239.980 7.060 574.650 292 ;
        RECT 459.000 134.110 460.750 136.520 ;
        RECT 470.690 98.390 471.010 125.510 ;
        RECT 504.740 98.300 505.060 125.420 ;
        RECT 470.710 69.640 471.030 96.760 ;
        RECT 504.780 69.520 505.100 96.640 ;
      LAYER met4 ;
        RECT 239.980 7.060 574.650 292 ;
        RECT 458.390 133.710 461.160 137.330 ;
        RECT 459.110 133.400 461.050 133.710 ;
        RECT 459.110 133.350 460.240 133.400 ;
        RECT 459.280 129.070 460.240 133.350 ;
        RECT 459.280 128.530 461.110 129.070 ;
        RECT 464.210 128.670 470.030 128.800 ;
        RECT 464.210 128.570 471.430 128.670 ;
        RECT 463.790 128.530 471.430 128.570 ;
        RECT 459.280 128.400 471.430 128.530 ;
        RECT 459.280 128.200 505.340 128.400 ;
        RECT 459.280 127.780 505.430 128.200 ;
        RECT 463.790 127.590 505.430 127.780 ;
        RECT 464.210 127.490 505.430 127.590 ;
        RECT 469.250 127.370 505.430 127.490 ;
        RECT 469.250 127.110 470.120 127.370 ;
        RECT 470.640 125.590 471.370 127.370 ;
        RECT 470.610 124.990 471.370 125.590 ;
        RECT 504.850 125.500 505.430 127.370 ;
        RECT 470.610 100.180 471.090 124.990 ;
        RECT 504.660 124.690 505.430 125.500 ;
        RECT 470.610 98.310 471.430 100.180 ;
        RECT 504.660 100.100 505.140 124.690 ;
        RECT 470.680 96.840 471.430 98.310 ;
        RECT 470.630 96.340 471.430 96.840 ;
        RECT 470.630 69.560 471.110 96.340 ;
        RECT 504.590 95.600 506.010 100.100 ;
        RECT 504.700 69.440 505.180 95.600 ;
  END
END sdmay26_23_opamp
END LIBRARY

